VERSION 5.7 ;
  NOWIREEXTENSIONATPIN ON ;
  DIVIDERCHAR "/" ;
  BUSBITCHARS "[]" ;
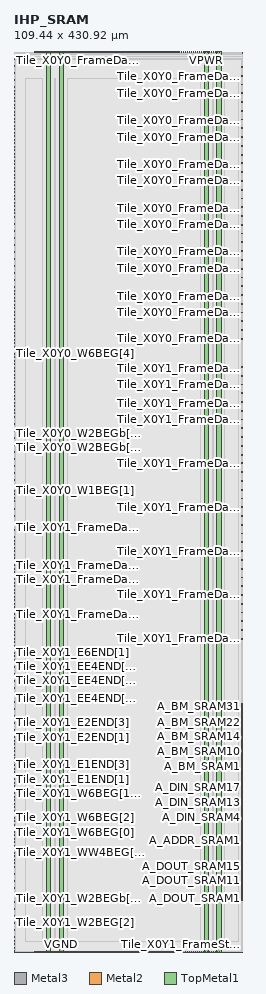
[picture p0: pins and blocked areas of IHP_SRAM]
MACRO IHP_SRAM
  CLASS BLOCK ;
  FOREIGN IHP_SRAM ;
  ORIGIN 0.000 0.000 ;
  SIZE 109.440 BY 430.920 ;
  PIN A_ADDR_SRAM0
    DIRECTION OUTPUT ;
    USE SIGNAL ;
    ANTENNADIFFAREA 0.708600 ;
    PORT
      LAYER Metal3 ;
        RECT 109.040 52.300 109.440 52.700 ;
    END
  END A_ADDR_SRAM0
  PIN A_ADDR_SRAM1
    DIRECTION OUTPUT ;
    USE SIGNAL ;
    ANTENNADIFFAREA 0.708600 ;
    PORT
      LAYER Metal3 ;
        RECT 109.040 53.140 109.440 53.540 ;
    END
  END A_ADDR_SRAM1
  PIN A_ADDR_SRAM2
    DIRECTION OUTPUT ;
    USE SIGNAL ;
    ANTENNADIFFAREA 0.708600 ;
    PORT
      LAYER Metal3 ;
        RECT 109.040 53.980 109.440 54.380 ;
    END
  END A_ADDR_SRAM2
  PIN A_ADDR_SRAM3
    DIRECTION OUTPUT ;
    USE SIGNAL ;
    ANTENNADIFFAREA 0.708600 ;
    PORT
      LAYER Metal3 ;
        RECT 109.040 54.820 109.440 55.220 ;
    END
  END A_ADDR_SRAM3
  PIN A_ADDR_SRAM4
    DIRECTION OUTPUT ;
    USE SIGNAL ;
    ANTENNADIFFAREA 0.708600 ;
    PORT
      LAYER Metal3 ;
        RECT 109.040 55.660 109.440 56.060 ;
    END
  END A_ADDR_SRAM4
  PIN A_ADDR_SRAM5
    DIRECTION OUTPUT ;
    USE SIGNAL ;
    ANTENNADIFFAREA 0.708600 ;
    PORT
      LAYER Metal3 ;
        RECT 109.040 56.500 109.440 56.900 ;
    END
  END A_ADDR_SRAM5
  PIN A_ADDR_SRAM6
    DIRECTION OUTPUT ;
    USE SIGNAL ;
    ANTENNADIFFAREA 0.708600 ;
    PORT
      LAYER Metal3 ;
        RECT 109.040 57.340 109.440 57.740 ;
    END
  END A_ADDR_SRAM6
  PIN A_ADDR_SRAM7
    DIRECTION OUTPUT ;
    USE SIGNAL ;
    ANTENNADIFFAREA 0.708600 ;
    PORT
      LAYER Metal3 ;
        RECT 109.040 58.180 109.440 58.580 ;
    END
  END A_ADDR_SRAM7
  PIN A_ADDR_SRAM8
    DIRECTION OUTPUT ;
    USE SIGNAL ;
    ANTENNADIFFAREA 0.708600 ;
    PORT
      LAYER Metal3 ;
        RECT 109.040 59.020 109.440 59.420 ;
    END
  END A_ADDR_SRAM8
  PIN A_ADDR_SRAM9
    DIRECTION OUTPUT ;
    USE SIGNAL ;
    ANTENNADIFFAREA 0.708600 ;
    PORT
      LAYER Metal3 ;
        RECT 109.040 59.860 109.440 60.260 ;
    END
  END A_ADDR_SRAM9
  PIN A_BM_SRAM0
    DIRECTION OUTPUT ;
    USE SIGNAL ;
    ANTENNADIFFAREA 0.708600 ;
    PORT
      LAYER Metal3 ;
        RECT 109.040 87.580 109.440 87.980 ;
    END
  END A_BM_SRAM0
  PIN A_BM_SRAM1
    DIRECTION OUTPUT ;
    USE SIGNAL ;
    ANTENNADIFFAREA 0.708600 ;
    PORT
      LAYER Metal3 ;
        RECT 109.040 88.420 109.440 88.820 ;
    END
  END A_BM_SRAM1
  PIN A_BM_SRAM10
    DIRECTION OUTPUT ;
    USE SIGNAL ;
    ANTENNADIFFAREA 0.708600 ;
    PORT
      LAYER Metal3 ;
        RECT 109.040 95.980 109.440 96.380 ;
    END
  END A_BM_SRAM10
  PIN A_BM_SRAM11
    DIRECTION OUTPUT ;
    USE SIGNAL ;
    ANTENNADIFFAREA 0.708600 ;
    PORT
      LAYER Metal3 ;
        RECT 109.040 96.820 109.440 97.220 ;
    END
  END A_BM_SRAM11
  PIN A_BM_SRAM12
    DIRECTION OUTPUT ;
    USE SIGNAL ;
    ANTENNADIFFAREA 0.708600 ;
    PORT
      LAYER Metal3 ;
        RECT 109.040 97.660 109.440 98.060 ;
    END
  END A_BM_SRAM12
  PIN A_BM_SRAM13
    DIRECTION OUTPUT ;
    USE SIGNAL ;
    ANTENNADIFFAREA 0.708600 ;
    PORT
      LAYER Metal3 ;
        RECT 109.040 98.500 109.440 98.900 ;
    END
  END A_BM_SRAM13
  PIN A_BM_SRAM14
    DIRECTION OUTPUT ;
    USE SIGNAL ;
    ANTENNADIFFAREA 0.708600 ;
    PORT
      LAYER Metal3 ;
        RECT 109.040 99.340 109.440 99.740 ;
    END
  END A_BM_SRAM14
  PIN A_BM_SRAM15
    DIRECTION OUTPUT ;
    USE SIGNAL ;
    ANTENNADIFFAREA 0.708600 ;
    PORT
      LAYER Metal3 ;
        RECT 109.040 100.180 109.440 100.580 ;
    END
  END A_BM_SRAM15
  PIN A_BM_SRAM16
    DIRECTION OUTPUT ;
    USE SIGNAL ;
    ANTENNADIFFAREA 0.708600 ;
    PORT
      LAYER Metal3 ;
        RECT 109.040 101.020 109.440 101.420 ;
    END
  END A_BM_SRAM16
  PIN A_BM_SRAM17
    DIRECTION OUTPUT ;
    USE SIGNAL ;
    ANTENNADIFFAREA 0.708600 ;
    PORT
      LAYER Metal3 ;
        RECT 109.040 101.860 109.440 102.260 ;
    END
  END A_BM_SRAM17
  PIN A_BM_SRAM18
    DIRECTION OUTPUT ;
    USE SIGNAL ;
    ANTENNADIFFAREA 0.708600 ;
    PORT
      LAYER Metal3 ;
        RECT 109.040 102.700 109.440 103.100 ;
    END
  END A_BM_SRAM18
  PIN A_BM_SRAM19
    DIRECTION OUTPUT ;
    USE SIGNAL ;
    ANTENNADIFFAREA 0.708600 ;
    PORT
      LAYER Metal3 ;
        RECT 109.040 103.540 109.440 103.940 ;
    END
  END A_BM_SRAM19
  PIN A_BM_SRAM2
    DIRECTION OUTPUT ;
    USE SIGNAL ;
    ANTENNADIFFAREA 0.708600 ;
    PORT
      LAYER Metal3 ;
        RECT 109.040 89.260 109.440 89.660 ;
    END
  END A_BM_SRAM2
  PIN A_BM_SRAM20
    DIRECTION OUTPUT ;
    USE SIGNAL ;
    ANTENNADIFFAREA 0.708600 ;
    PORT
      LAYER Metal3 ;
        RECT 109.040 104.380 109.440 104.780 ;
    END
  END A_BM_SRAM20
  PIN A_BM_SRAM21
    DIRECTION OUTPUT ;
    USE SIGNAL ;
    ANTENNADIFFAREA 0.708600 ;
    PORT
      LAYER Metal3 ;
        RECT 109.040 105.220 109.440 105.620 ;
    END
  END A_BM_SRAM21
  PIN A_BM_SRAM22
    DIRECTION OUTPUT ;
    USE SIGNAL ;
    ANTENNADIFFAREA 0.708600 ;
    PORT
      LAYER Metal3 ;
        RECT 109.040 106.060 109.440 106.460 ;
    END
  END A_BM_SRAM22
  PIN A_BM_SRAM23
    DIRECTION OUTPUT ;
    USE SIGNAL ;
    ANTENNADIFFAREA 0.708600 ;
    PORT
      LAYER Metal3 ;
        RECT 109.040 106.900 109.440 107.300 ;
    END
  END A_BM_SRAM23
  PIN A_BM_SRAM24
    DIRECTION OUTPUT ;
    USE SIGNAL ;
    ANTENNADIFFAREA 0.708600 ;
    PORT
      LAYER Metal3 ;
        RECT 109.040 107.740 109.440 108.140 ;
    END
  END A_BM_SRAM24
  PIN A_BM_SRAM25
    DIRECTION OUTPUT ;
    USE SIGNAL ;
    ANTENNADIFFAREA 0.708600 ;
    PORT
      LAYER Metal3 ;
        RECT 109.040 108.580 109.440 108.980 ;
    END
  END A_BM_SRAM25
  PIN A_BM_SRAM26
    DIRECTION OUTPUT ;
    USE SIGNAL ;
    ANTENNADIFFAREA 0.708600 ;
    PORT
      LAYER Metal3 ;
        RECT 109.040 109.420 109.440 109.820 ;
    END
  END A_BM_SRAM26
  PIN A_BM_SRAM27
    DIRECTION OUTPUT ;
    USE SIGNAL ;
    ANTENNADIFFAREA 0.708600 ;
    PORT
      LAYER Metal3 ;
        RECT 109.040 110.260 109.440 110.660 ;
    END
  END A_BM_SRAM27
  PIN A_BM_SRAM28
    DIRECTION OUTPUT ;
    USE SIGNAL ;
    ANTENNADIFFAREA 0.708600 ;
    PORT
      LAYER Metal3 ;
        RECT 109.040 111.100 109.440 111.500 ;
    END
  END A_BM_SRAM28
  PIN A_BM_SRAM29
    DIRECTION OUTPUT ;
    USE SIGNAL ;
    ANTENNADIFFAREA 0.708600 ;
    PORT
      LAYER Metal3 ;
        RECT 109.040 111.940 109.440 112.340 ;
    END
  END A_BM_SRAM29
  PIN A_BM_SRAM3
    DIRECTION OUTPUT ;
    USE SIGNAL ;
    ANTENNADIFFAREA 0.708600 ;
    PORT
      LAYER Metal3 ;
        RECT 109.040 90.100 109.440 90.500 ;
    END
  END A_BM_SRAM3
  PIN A_BM_SRAM30
    DIRECTION OUTPUT ;
    USE SIGNAL ;
    ANTENNADIFFAREA 0.708600 ;
    PORT
      LAYER Metal3 ;
        RECT 109.040 112.780 109.440 113.180 ;
    END
  END A_BM_SRAM30
  PIN A_BM_SRAM31
    DIRECTION OUTPUT ;
    USE SIGNAL ;
    ANTENNADIFFAREA 0.708600 ;
    PORT
      LAYER Metal3 ;
        RECT 109.040 113.620 109.440 114.020 ;
    END
  END A_BM_SRAM31
  PIN A_BM_SRAM4
    DIRECTION OUTPUT ;
    USE SIGNAL ;
    ANTENNADIFFAREA 0.708600 ;
    PORT
      LAYER Metal3 ;
        RECT 109.040 90.940 109.440 91.340 ;
    END
  END A_BM_SRAM4
  PIN A_BM_SRAM5
    DIRECTION OUTPUT ;
    USE SIGNAL ;
    ANTENNADIFFAREA 0.708600 ;
    PORT
      LAYER Metal3 ;
        RECT 109.040 91.780 109.440 92.180 ;
    END
  END A_BM_SRAM5
  PIN A_BM_SRAM6
    DIRECTION OUTPUT ;
    USE SIGNAL ;
    ANTENNADIFFAREA 0.708600 ;
    PORT
      LAYER Metal3 ;
        RECT 109.040 92.620 109.440 93.020 ;
    END
  END A_BM_SRAM6
  PIN A_BM_SRAM7
    DIRECTION OUTPUT ;
    USE SIGNAL ;
    ANTENNADIFFAREA 0.708600 ;
    PORT
      LAYER Metal3 ;
        RECT 109.040 93.460 109.440 93.860 ;
    END
  END A_BM_SRAM7
  PIN A_BM_SRAM8
    DIRECTION OUTPUT ;
    USE SIGNAL ;
    ANTENNADIFFAREA 0.708600 ;
    PORT
      LAYER Metal3 ;
        RECT 109.040 94.300 109.440 94.700 ;
    END
  END A_BM_SRAM8
  PIN A_BM_SRAM9
    DIRECTION OUTPUT ;
    USE SIGNAL ;
    ANTENNADIFFAREA 0.708600 ;
    PORT
      LAYER Metal3 ;
        RECT 109.040 95.140 109.440 95.540 ;
    END
  END A_BM_SRAM9
  PIN A_CLK_SRAM
    DIRECTION OUTPUT ;
    USE SIGNAL ;
    ANTENNADIFFAREA 0.708600 ;
    PORT
      LAYER Metal3 ;
        RECT 109.040 116.980 109.440 117.380 ;
    END
  END A_CLK_SRAM
  PIN A_DIN_SRAM0
    DIRECTION OUTPUT ;
    USE SIGNAL ;
    ANTENNADIFFAREA 0.708600 ;
    PORT
      LAYER Metal3 ;
        RECT 109.040 60.700 109.440 61.100 ;
    END
  END A_DIN_SRAM0
  PIN A_DIN_SRAM1
    DIRECTION OUTPUT ;
    USE SIGNAL ;
    ANTENNADIFFAREA 0.708600 ;
    PORT
      LAYER Metal3 ;
        RECT 109.040 61.540 109.440 61.940 ;
    END
  END A_DIN_SRAM1
  PIN A_DIN_SRAM10
    DIRECTION OUTPUT ;
    USE SIGNAL ;
    ANTENNADIFFAREA 0.708600 ;
    PORT
      LAYER Metal3 ;
        RECT 109.040 69.100 109.440 69.500 ;
    END
  END A_DIN_SRAM10
  PIN A_DIN_SRAM11
    DIRECTION OUTPUT ;
    USE SIGNAL ;
    ANTENNADIFFAREA 0.708600 ;
    PORT
      LAYER Metal3 ;
        RECT 109.040 69.940 109.440 70.340 ;
    END
  END A_DIN_SRAM11
  PIN A_DIN_SRAM12
    DIRECTION OUTPUT ;
    USE SIGNAL ;
    ANTENNADIFFAREA 0.708600 ;
    PORT
      LAYER Metal3 ;
        RECT 109.040 70.780 109.440 71.180 ;
    END
  END A_DIN_SRAM12
  PIN A_DIN_SRAM13
    DIRECTION OUTPUT ;
    USE SIGNAL ;
    ANTENNADIFFAREA 0.708600 ;
    PORT
      LAYER Metal3 ;
        RECT 109.040 71.620 109.440 72.020 ;
    END
  END A_DIN_SRAM13
  PIN A_DIN_SRAM14
    DIRECTION OUTPUT ;
    USE SIGNAL ;
    ANTENNADIFFAREA 0.708600 ;
    PORT
      LAYER Metal3 ;
        RECT 109.040 72.460 109.440 72.860 ;
    END
  END A_DIN_SRAM14
  PIN A_DIN_SRAM15
    DIRECTION OUTPUT ;
    USE SIGNAL ;
    ANTENNADIFFAREA 0.708600 ;
    PORT
      LAYER Metal3 ;
        RECT 109.040 73.300 109.440 73.700 ;
    END
  END A_DIN_SRAM15
  PIN A_DIN_SRAM16
    DIRECTION OUTPUT ;
    USE SIGNAL ;
    ANTENNADIFFAREA 0.708600 ;
    PORT
      LAYER Metal3 ;
        RECT 109.040 74.140 109.440 74.540 ;
    END
  END A_DIN_SRAM16
  PIN A_DIN_SRAM17
    DIRECTION OUTPUT ;
    USE SIGNAL ;
    ANTENNADIFFAREA 0.708600 ;
    PORT
      LAYER Metal3 ;
        RECT 109.040 74.980 109.440 75.380 ;
    END
  END A_DIN_SRAM17
  PIN A_DIN_SRAM18
    DIRECTION OUTPUT ;
    USE SIGNAL ;
    ANTENNADIFFAREA 0.708600 ;
    PORT
      LAYER Metal3 ;
        RECT 109.040 75.820 109.440 76.220 ;
    END
  END A_DIN_SRAM18
  PIN A_DIN_SRAM19
    DIRECTION OUTPUT ;
    USE SIGNAL ;
    ANTENNADIFFAREA 0.708600 ;
    PORT
      LAYER Metal3 ;
        RECT 109.040 76.660 109.440 77.060 ;
    END
  END A_DIN_SRAM19
  PIN A_DIN_SRAM2
    DIRECTION OUTPUT ;
    USE SIGNAL ;
    ANTENNADIFFAREA 0.708600 ;
    PORT
      LAYER Metal3 ;
        RECT 109.040 62.380 109.440 62.780 ;
    END
  END A_DIN_SRAM2
  PIN A_DIN_SRAM20
    DIRECTION OUTPUT ;
    USE SIGNAL ;
    ANTENNADIFFAREA 0.708600 ;
    PORT
      LAYER Metal3 ;
        RECT 109.040 77.500 109.440 77.900 ;
    END
  END A_DIN_SRAM20
  PIN A_DIN_SRAM21
    DIRECTION OUTPUT ;
    USE SIGNAL ;
    ANTENNADIFFAREA 0.708600 ;
    PORT
      LAYER Metal3 ;
        RECT 109.040 78.340 109.440 78.740 ;
    END
  END A_DIN_SRAM21
  PIN A_DIN_SRAM22
    DIRECTION OUTPUT ;
    USE SIGNAL ;
    ANTENNADIFFAREA 0.708600 ;
    PORT
      LAYER Metal3 ;
        RECT 109.040 79.180 109.440 79.580 ;
    END
  END A_DIN_SRAM22
  PIN A_DIN_SRAM23
    DIRECTION OUTPUT ;
    USE SIGNAL ;
    ANTENNADIFFAREA 0.708600 ;
    PORT
      LAYER Metal3 ;
        RECT 109.040 80.020 109.440 80.420 ;
    END
  END A_DIN_SRAM23
  PIN A_DIN_SRAM24
    DIRECTION OUTPUT ;
    USE SIGNAL ;
    ANTENNADIFFAREA 0.708600 ;
    PORT
      LAYER Metal3 ;
        RECT 109.040 80.860 109.440 81.260 ;
    END
  END A_DIN_SRAM24
  PIN A_DIN_SRAM25
    DIRECTION OUTPUT ;
    USE SIGNAL ;
    ANTENNADIFFAREA 0.708600 ;
    PORT
      LAYER Metal3 ;
        RECT 109.040 81.700 109.440 82.100 ;
    END
  END A_DIN_SRAM25
  PIN A_DIN_SRAM26
    DIRECTION OUTPUT ;
    USE SIGNAL ;
    ANTENNADIFFAREA 0.708600 ;
    PORT
      LAYER Metal3 ;
        RECT 109.040 82.540 109.440 82.940 ;
    END
  END A_DIN_SRAM26
  PIN A_DIN_SRAM27
    DIRECTION OUTPUT ;
    USE SIGNAL ;
    ANTENNADIFFAREA 0.708600 ;
    PORT
      LAYER Metal3 ;
        RECT 109.040 83.380 109.440 83.780 ;
    END
  END A_DIN_SRAM27
  PIN A_DIN_SRAM28
    DIRECTION OUTPUT ;
    USE SIGNAL ;
    ANTENNADIFFAREA 0.708600 ;
    PORT
      LAYER Metal3 ;
        RECT 109.040 84.220 109.440 84.620 ;
    END
  END A_DIN_SRAM28
  PIN A_DIN_SRAM29
    DIRECTION OUTPUT ;
    USE SIGNAL ;
    ANTENNADIFFAREA 0.708600 ;
    PORT
      LAYER Metal3 ;
        RECT 109.040 85.060 109.440 85.460 ;
    END
  END A_DIN_SRAM29
  PIN A_DIN_SRAM3
    DIRECTION OUTPUT ;
    USE SIGNAL ;
    ANTENNADIFFAREA 0.708600 ;
    PORT
      LAYER Metal3 ;
        RECT 109.040 63.220 109.440 63.620 ;
    END
  END A_DIN_SRAM3
  PIN A_DIN_SRAM30
    DIRECTION OUTPUT ;
    USE SIGNAL ;
    ANTENNADIFFAREA 0.708600 ;
    PORT
      LAYER Metal3 ;
        RECT 109.040 85.900 109.440 86.300 ;
    END
  END A_DIN_SRAM30
  PIN A_DIN_SRAM31
    DIRECTION OUTPUT ;
    USE SIGNAL ;
    ANTENNADIFFAREA 0.708600 ;
    PORT
      LAYER Metal3 ;
        RECT 109.040 86.740 109.440 87.140 ;
    END
  END A_DIN_SRAM31
  PIN A_DIN_SRAM4
    DIRECTION OUTPUT ;
    USE SIGNAL ;
    ANTENNADIFFAREA 0.708600 ;
    PORT
      LAYER Metal3 ;
        RECT 109.040 64.060 109.440 64.460 ;
    END
  END A_DIN_SRAM4
  PIN A_DIN_SRAM5
    DIRECTION OUTPUT ;
    USE SIGNAL ;
    ANTENNADIFFAREA 0.708600 ;
    PORT
      LAYER Metal3 ;
        RECT 109.040 64.900 109.440 65.300 ;
    END
  END A_DIN_SRAM5
  PIN A_DIN_SRAM6
    DIRECTION OUTPUT ;
    USE SIGNAL ;
    ANTENNADIFFAREA 0.708600 ;
    PORT
      LAYER Metal3 ;
        RECT 109.040 65.740 109.440 66.140 ;
    END
  END A_DIN_SRAM6
  PIN A_DIN_SRAM7
    DIRECTION OUTPUT ;
    USE SIGNAL ;
    ANTENNADIFFAREA 0.708600 ;
    PORT
      LAYER Metal3 ;
        RECT 109.040 66.580 109.440 66.980 ;
    END
  END A_DIN_SRAM7
  PIN A_DIN_SRAM8
    DIRECTION OUTPUT ;
    USE SIGNAL ;
    ANTENNADIFFAREA 0.708600 ;
    PORT
      LAYER Metal3 ;
        RECT 109.040 67.420 109.440 67.820 ;
    END
  END A_DIN_SRAM8
  PIN A_DIN_SRAM9
    DIRECTION OUTPUT ;
    USE SIGNAL ;
    ANTENNADIFFAREA 0.708600 ;
    PORT
      LAYER Metal3 ;
        RECT 109.040 68.260 109.440 68.660 ;
    END
  END A_DIN_SRAM9
  PIN A_DOUT_SRAM0
    DIRECTION INPUT ;
    USE SIGNAL ;
    ANTENNAGATEAREA 1.279200 ;
    PORT
      LAYER Metal3 ;
        RECT 109.040 24.580 109.440 24.980 ;
    END
  END A_DOUT_SRAM0
  PIN A_DOUT_SRAM1
    DIRECTION INPUT ;
    USE SIGNAL ;
    ANTENNAGATEAREA 1.279200 ;
    PORT
      LAYER Metal3 ;
        RECT 109.040 25.420 109.440 25.820 ;
    END
  END A_DOUT_SRAM1
  PIN A_DOUT_SRAM10
    DIRECTION INPUT ;
    USE SIGNAL ;
    ANTENNAGATEAREA 0.852800 ;
    PORT
      LAYER Metal3 ;
        RECT 109.040 32.980 109.440 33.380 ;
    END
  END A_DOUT_SRAM10
  PIN A_DOUT_SRAM11
    DIRECTION INPUT ;
    USE SIGNAL ;
    ANTENNAGATEAREA 0.852800 ;
    PORT
      LAYER Metal3 ;
        RECT 109.040 33.820 109.440 34.220 ;
    END
  END A_DOUT_SRAM11
  PIN A_DOUT_SRAM12
    DIRECTION INPUT ;
    USE SIGNAL ;
    ANTENNAGATEAREA 0.852800 ;
    PORT
      LAYER Metal3 ;
        RECT 109.040 34.660 109.440 35.060 ;
    END
  END A_DOUT_SRAM12
  PIN A_DOUT_SRAM13
    DIRECTION INPUT ;
    USE SIGNAL ;
    ANTENNAGATEAREA 0.852800 ;
    PORT
      LAYER Metal3 ;
        RECT 109.040 35.500 109.440 35.900 ;
    END
  END A_DOUT_SRAM13
  PIN A_DOUT_SRAM14
    DIRECTION INPUT ;
    USE SIGNAL ;
    ANTENNAGATEAREA 0.852800 ;
    PORT
      LAYER Metal3 ;
        RECT 109.040 36.340 109.440 36.740 ;
    END
  END A_DOUT_SRAM14
  PIN A_DOUT_SRAM15
    DIRECTION INPUT ;
    USE SIGNAL ;
    ANTENNAGATEAREA 0.852800 ;
    PORT
      LAYER Metal3 ;
        RECT 109.040 37.180 109.440 37.580 ;
    END
  END A_DOUT_SRAM15
  PIN A_DOUT_SRAM16
    DIRECTION INPUT ;
    USE SIGNAL ;
    ANTENNAGATEAREA 1.279200 ;
    PORT
      LAYER Metal3 ;
        RECT 109.040 38.020 109.440 38.420 ;
    END
  END A_DOUT_SRAM16
  PIN A_DOUT_SRAM17
    DIRECTION INPUT ;
    USE SIGNAL ;
    ANTENNAGATEAREA 1.279200 ;
    PORT
      LAYER Metal3 ;
        RECT 109.040 38.860 109.440 39.260 ;
    END
  END A_DOUT_SRAM17
  PIN A_DOUT_SRAM18
    DIRECTION INPUT ;
    USE SIGNAL ;
    ANTENNAGATEAREA 5.538000 ;
    ANTENNADIFFAREA 14.107800 ;
    PORT
      LAYER Metal3 ;
        RECT 109.040 39.700 109.440 40.100 ;
    END
  END A_DOUT_SRAM18
  PIN A_DOUT_SRAM19
    DIRECTION INPUT ;
    USE SIGNAL ;
    ANTENNAGATEAREA 4.929600 ;
    ANTENNADIFFAREA 12.092400 ;
    PORT
      LAYER Metal3 ;
        RECT 109.040 40.540 109.440 40.940 ;
    END
  END A_DOUT_SRAM19
  PIN A_DOUT_SRAM2
    DIRECTION INPUT ;
    USE SIGNAL ;
    ANTENNAGATEAREA 1.279200 ;
    PORT
      LAYER Metal3 ;
        RECT 109.040 26.260 109.440 26.660 ;
    END
  END A_DOUT_SRAM2
  PIN A_DOUT_SRAM20
    DIRECTION INPUT ;
    USE SIGNAL ;
    ANTENNAGATEAREA 1.279200 ;
    PORT
      LAYER Metal3 ;
        RECT 109.040 41.380 109.440 41.780 ;
    END
  END A_DOUT_SRAM20
  PIN A_DOUT_SRAM21
    DIRECTION INPUT ;
    USE SIGNAL ;
    ANTENNAGATEAREA 1.279200 ;
    PORT
      LAYER Metal3 ;
        RECT 109.040 42.220 109.440 42.620 ;
    END
  END A_DOUT_SRAM21
  PIN A_DOUT_SRAM22
    DIRECTION INPUT ;
    USE SIGNAL ;
    ANTENNAGATEAREA 1.279200 ;
    PORT
      LAYER Metal3 ;
        RECT 109.040 43.060 109.440 43.460 ;
    END
  END A_DOUT_SRAM22
  PIN A_DOUT_SRAM23
    DIRECTION INPUT ;
    USE SIGNAL ;
    ANTENNAGATEAREA 1.279200 ;
    PORT
      LAYER Metal3 ;
        RECT 109.040 43.900 109.440 44.300 ;
    END
  END A_DOUT_SRAM23
  PIN A_DOUT_SRAM24
    DIRECTION INPUT ;
    USE SIGNAL ;
    ANTENNAGATEAREA 1.066000 ;
    PORT
      LAYER Metal3 ;
        RECT 109.040 44.740 109.440 45.140 ;
    END
  END A_DOUT_SRAM24
  PIN A_DOUT_SRAM25
    DIRECTION INPUT ;
    USE SIGNAL ;
    ANTENNAGATEAREA 0.639600 ;
    PORT
      LAYER Metal3 ;
        RECT 109.040 45.580 109.440 45.980 ;
    END
  END A_DOUT_SRAM25
  PIN A_DOUT_SRAM26
    DIRECTION INPUT ;
    USE SIGNAL ;
    ANTENNAGATEAREA 0.852800 ;
    PORT
      LAYER Metal3 ;
        RECT 109.040 46.420 109.440 46.820 ;
    END
  END A_DOUT_SRAM26
  PIN A_DOUT_SRAM27
    DIRECTION INPUT ;
    USE SIGNAL ;
    ANTENNAGATEAREA 0.852800 ;
    PORT
      LAYER Metal3 ;
        RECT 109.040 47.260 109.440 47.660 ;
    END
  END A_DOUT_SRAM27
  PIN A_DOUT_SRAM28
    DIRECTION INPUT ;
    USE SIGNAL ;
    ANTENNAGATEAREA 3.894800 ;
    ANTENNADIFFAREA 10.077000 ;
    PORT
      LAYER Metal3 ;
        RECT 109.040 48.100 109.440 48.500 ;
    END
  END A_DOUT_SRAM28
  PIN A_DOUT_SRAM29
    DIRECTION INPUT ;
    USE SIGNAL ;
    ANTENNAGATEAREA 0.852800 ;
    PORT
      LAYER Metal3 ;
        RECT 109.040 48.940 109.440 49.340 ;
    END
  END A_DOUT_SRAM29
  PIN A_DOUT_SRAM3
    DIRECTION INPUT ;
    USE SIGNAL ;
    ANTENNAGATEAREA 1.279200 ;
    PORT
      LAYER Metal3 ;
        RECT 109.040 27.100 109.440 27.500 ;
    END
  END A_DOUT_SRAM3
  PIN A_DOUT_SRAM30
    DIRECTION INPUT ;
    USE SIGNAL ;
    ANTENNAGATEAREA 0.852800 ;
    PORT
      LAYER Metal3 ;
        RECT 109.040 49.780 109.440 50.180 ;
    END
  END A_DOUT_SRAM30
  PIN A_DOUT_SRAM31
    DIRECTION INPUT ;
    USE SIGNAL ;
    ANTENNAGATEAREA 0.852800 ;
    PORT
      LAYER Metal3 ;
        RECT 109.040 50.620 109.440 51.020 ;
    END
  END A_DOUT_SRAM31
  PIN A_DOUT_SRAM4
    DIRECTION INPUT ;
    USE SIGNAL ;
    ANTENNAGATEAREA 1.279200 ;
    PORT
      LAYER Metal3 ;
        RECT 109.040 27.940 109.440 28.340 ;
    END
  END A_DOUT_SRAM4
  PIN A_DOUT_SRAM5
    DIRECTION INPUT ;
    USE SIGNAL ;
    ANTENNAGATEAREA 1.279200 ;
    PORT
      LAYER Metal3 ;
        RECT 109.040 28.780 109.440 29.180 ;
    END
  END A_DOUT_SRAM5
  PIN A_DOUT_SRAM6
    DIRECTION INPUT ;
    USE SIGNAL ;
    ANTENNAGATEAREA 1.279200 ;
    PORT
      LAYER Metal3 ;
        RECT 109.040 29.620 109.440 30.020 ;
    END
  END A_DOUT_SRAM6
  PIN A_DOUT_SRAM7
    DIRECTION INPUT ;
    USE SIGNAL ;
    ANTENNAGATEAREA 1.279200 ;
    PORT
      LAYER Metal3 ;
        RECT 109.040 30.460 109.440 30.860 ;
    END
  END A_DOUT_SRAM7
  PIN A_DOUT_SRAM8
    DIRECTION INPUT ;
    USE SIGNAL ;
    ANTENNAGATEAREA 0.852800 ;
    PORT
      LAYER Metal3 ;
        RECT 109.040 31.300 109.440 31.700 ;
    END
  END A_DOUT_SRAM8
  PIN A_DOUT_SRAM9
    DIRECTION INPUT ;
    USE SIGNAL ;
    ANTENNAGATEAREA 0.852800 ;
    PORT
      LAYER Metal3 ;
        RECT 109.040 32.140 109.440 32.540 ;
    END
  END A_DOUT_SRAM9
  PIN A_MEN_SRAM
    DIRECTION OUTPUT ;
    USE SIGNAL ;
    ANTENNADIFFAREA 0.708600 ;
    PORT
      LAYER Metal3 ;
        RECT 109.040 115.300 109.440 115.700 ;
    END
  END A_MEN_SRAM
  PIN A_REN_SRAM
    DIRECTION OUTPUT ;
    USE SIGNAL ;
    ANTENNADIFFAREA 0.708600 ;
    PORT
      LAYER Metal3 ;
        RECT 109.040 116.140 109.440 116.540 ;
    END
  END A_REN_SRAM
  PIN A_TIE_HIGH_SRAM
    DIRECTION OUTPUT ;
    USE SIGNAL ;
    ANTENNADIFFAREA 0.392700 ;
    PORT
      LAYER Metal3 ;
        RECT 109.040 117.820 109.440 118.220 ;
    END
  END A_TIE_HIGH_SRAM
  PIN A_TIE_LOW_SRAM
    DIRECTION OUTPUT ;
    USE SIGNAL ;
    ANTENNADIFFAREA 0.299200 ;
    PORT
      LAYER Metal3 ;
        RECT 109.040 118.660 109.440 119.060 ;
    END
  END A_TIE_LOW_SRAM
  PIN A_WEN_SRAM
    DIRECTION OUTPUT ;
    USE SIGNAL ;
    ANTENNADIFFAREA 0.708600 ;
    PORT
      LAYER Metal3 ;
        RECT 109.040 114.460 109.440 114.860 ;
    END
  END A_WEN_SRAM
  PIN CONFIGURED_top
    DIRECTION INPUT ;
    USE SIGNAL ;
    ANTENNAGATEAREA 0.279000 ;
    PORT
      LAYER Metal3 ;
        RECT 109.040 51.460 109.440 51.860 ;
    END
  END CONFIGURED_top
  PIN Tile_X0Y0_E1END[0]
    DIRECTION INPUT ;
    USE SIGNAL ;
    ANTENNAGATEAREA 1.492400 ;
    PORT
      LAYER Metal3 ;
        RECT 0.000 296.320 0.400 296.720 ;
    END
  END Tile_X0Y0_E1END[0]
  PIN Tile_X0Y0_E1END[1]
    DIRECTION INPUT ;
    USE SIGNAL ;
    ANTENNAGATEAREA 1.492400 ;
    PORT
      LAYER Metal3 ;
        RECT 0.000 298.000 0.400 298.400 ;
    END
  END Tile_X0Y0_E1END[1]
  PIN Tile_X0Y0_E1END[2]
    DIRECTION INPUT ;
    USE SIGNAL ;
    ANTENNAGATEAREA 1.492400 ;
    PORT
      LAYER Metal3 ;
        RECT 0.000 299.680 0.400 300.080 ;
    END
  END Tile_X0Y0_E1END[2]
  PIN Tile_X0Y0_E1END[3]
    DIRECTION INPUT ;
    USE SIGNAL ;
    ANTENNAGATEAREA 1.492400 ;
    PORT
      LAYER Metal3 ;
        RECT 0.000 301.360 0.400 301.760 ;
    END
  END Tile_X0Y0_E1END[3]
  PIN Tile_X0Y0_E2END[0]
    DIRECTION INPUT ;
    USE SIGNAL ;
    ANTENNAGATEAREA 0.668200 ;
    PORT
      LAYER Metal3 ;
        RECT 0.000 316.480 0.400 316.880 ;
    END
  END Tile_X0Y0_E2END[0]
  PIN Tile_X0Y0_E2END[1]
    DIRECTION INPUT ;
    USE SIGNAL ;
    ANTENNAGATEAREA 0.668200 ;
    PORT
      LAYER Metal3 ;
        RECT 0.000 318.160 0.400 318.560 ;
    END
  END Tile_X0Y0_E2END[1]
  PIN Tile_X0Y0_E2END[2]
    DIRECTION INPUT ;
    USE SIGNAL ;
    ANTENNAGATEAREA 0.668200 ;
    PORT
      LAYER Metal3 ;
        RECT 0.000 319.840 0.400 320.240 ;
    END
  END Tile_X0Y0_E2END[2]
  PIN Tile_X0Y0_E2END[3]
    DIRECTION INPUT ;
    USE SIGNAL ;
    ANTENNAGATEAREA 0.668200 ;
    PORT
      LAYER Metal3 ;
        RECT 0.000 321.520 0.400 321.920 ;
    END
  END Tile_X0Y0_E2END[3]
  PIN Tile_X0Y0_E2END[4]
    DIRECTION INPUT ;
    USE SIGNAL ;
    ANTENNAGATEAREA 0.668200 ;
    PORT
      LAYER Metal3 ;
        RECT 0.000 323.200 0.400 323.600 ;
    END
  END Tile_X0Y0_E2END[4]
  PIN Tile_X0Y0_E2END[5]
    DIRECTION INPUT ;
    USE SIGNAL ;
    ANTENNAGATEAREA 0.426400 ;
    PORT
      LAYER Metal3 ;
        RECT 0.000 324.880 0.400 325.280 ;
    END
  END Tile_X0Y0_E2END[5]
  PIN Tile_X0Y0_E2END[6]
    DIRECTION INPUT ;
    USE SIGNAL ;
    ANTENNAGATEAREA 0.426400 ;
    PORT
      LAYER Metal3 ;
        RECT 0.000 326.560 0.400 326.960 ;
    END
  END Tile_X0Y0_E2END[6]
  PIN Tile_X0Y0_E2END[7]
    DIRECTION INPUT ;
    USE SIGNAL ;
    ANTENNAGATEAREA 0.426400 ;
    PORT
      LAYER Metal3 ;
        RECT 0.000 328.240 0.400 328.640 ;
    END
  END Tile_X0Y0_E2END[7]
  PIN Tile_X0Y0_E2MID[0]
    DIRECTION INPUT ;
    USE SIGNAL ;
    ANTENNAGATEAREA 0.672100 ;
    PORT
      LAYER Metal3 ;
        RECT 0.000 303.040 0.400 303.440 ;
    END
  END Tile_X0Y0_E2MID[0]
  PIN Tile_X0Y0_E2MID[1]
    DIRECTION INPUT ;
    USE SIGNAL ;
    ANTENNAGATEAREA 0.672100 ;
    PORT
      LAYER Metal3 ;
        RECT 0.000 304.720 0.400 305.120 ;
    END
  END Tile_X0Y0_E2MID[1]
  PIN Tile_X0Y0_E2MID[2]
    DIRECTION INPUT ;
    USE SIGNAL ;
    ANTENNAGATEAREA 0.672100 ;
    PORT
      LAYER Metal3 ;
        RECT 0.000 306.400 0.400 306.800 ;
    END
  END Tile_X0Y0_E2MID[2]
  PIN Tile_X0Y0_E2MID[3]
    DIRECTION INPUT ;
    USE SIGNAL ;
    ANTENNAGATEAREA 0.672100 ;
    PORT
      LAYER Metal3 ;
        RECT 0.000 308.080 0.400 308.480 ;
    END
  END Tile_X0Y0_E2MID[3]
  PIN Tile_X0Y0_E2MID[4]
    DIRECTION INPUT ;
    USE SIGNAL ;
    ANTENNAGATEAREA 0.672100 ;
    PORT
      LAYER Metal3 ;
        RECT 0.000 309.760 0.400 310.160 ;
    END
  END Tile_X0Y0_E2MID[4]
  PIN Tile_X0Y0_E2MID[5]
    DIRECTION INPUT ;
    USE SIGNAL ;
    ANTENNAGATEAREA 0.426400 ;
    PORT
      LAYER Metal3 ;
        RECT 0.000 311.440 0.400 311.840 ;
    END
  END Tile_X0Y0_E2MID[5]
  PIN Tile_X0Y0_E2MID[6]
    DIRECTION INPUT ;
    USE SIGNAL ;
    ANTENNAGATEAREA 0.426400 ;
    PORT
      LAYER Metal3 ;
        RECT 0.000 313.120 0.400 313.520 ;
    END
  END Tile_X0Y0_E2MID[6]
  PIN Tile_X0Y0_E2MID[7]
    DIRECTION INPUT ;
    USE SIGNAL ;
    ANTENNAGATEAREA 0.426400 ;
    PORT
      LAYER Metal3 ;
        RECT 0.000 314.800 0.400 315.200 ;
    END
  END Tile_X0Y0_E2MID[7]
  PIN Tile_X0Y0_E6END[0]
    DIRECTION INPUT ;
    USE SIGNAL ;
    ANTENNAGATEAREA 0.881400 ;
    PORT
      LAYER Metal3 ;
        RECT 0.000 356.800 0.400 357.200 ;
    END
  END Tile_X0Y0_E6END[0]
  PIN Tile_X0Y0_E6END[10]
    DIRECTION INPUT ;
    USE SIGNAL ;
    ANTENNAGATEAREA 1.066000 ;
    PORT
      LAYER Metal3 ;
        RECT 0.000 373.600 0.400 374.000 ;
    END
  END Tile_X0Y0_E6END[10]
  PIN Tile_X0Y0_E6END[11]
    DIRECTION INPUT ;
    USE SIGNAL ;
    ANTENNAGATEAREA 1.066000 ;
    PORT
      LAYER Metal3 ;
        RECT 0.000 375.280 0.400 375.680 ;
    END
  END Tile_X0Y0_E6END[11]
  PIN Tile_X0Y0_E6END[1]
    DIRECTION INPUT ;
    USE SIGNAL ;
    ANTENNAGATEAREA 0.881400 ;
    PORT
      LAYER Metal3 ;
        RECT 0.000 358.480 0.400 358.880 ;
    END
  END Tile_X0Y0_E6END[1]
  PIN Tile_X0Y0_E6END[2]
    DIRECTION INPUT ;
    USE SIGNAL ;
    ANTENNAGATEAREA 0.881400 ;
    PORT
      LAYER Metal3 ;
        RECT 0.000 360.160 0.400 360.560 ;
    END
  END Tile_X0Y0_E6END[2]
  PIN Tile_X0Y0_E6END[3]
    DIRECTION INPUT ;
    USE SIGNAL ;
    ANTENNAGATEAREA 0.881400 ;
    PORT
      LAYER Metal3 ;
        RECT 0.000 361.840 0.400 362.240 ;
    END
  END Tile_X0Y0_E6END[3]
  PIN Tile_X0Y0_E6END[4]
    DIRECTION INPUT ;
    USE SIGNAL ;
    ANTENNAGATEAREA 1.066000 ;
    PORT
      LAYER Metal3 ;
        RECT 0.000 363.520 0.400 363.920 ;
    END
  END Tile_X0Y0_E6END[4]
  PIN Tile_X0Y0_E6END[5]
    DIRECTION INPUT ;
    USE SIGNAL ;
    ANTENNAGATEAREA 1.066000 ;
    PORT
      LAYER Metal3 ;
        RECT 0.000 365.200 0.400 365.600 ;
    END
  END Tile_X0Y0_E6END[5]
  PIN Tile_X0Y0_E6END[6]
    DIRECTION INPUT ;
    USE SIGNAL ;
    ANTENNAGATEAREA 1.066000 ;
    PORT
      LAYER Metal3 ;
        RECT 0.000 366.880 0.400 367.280 ;
    END
  END Tile_X0Y0_E6END[6]
  PIN Tile_X0Y0_E6END[7]
    DIRECTION INPUT ;
    USE SIGNAL ;
    ANTENNAGATEAREA 1.066000 ;
    PORT
      LAYER Metal3 ;
        RECT 0.000 368.560 0.400 368.960 ;
    END
  END Tile_X0Y0_E6END[7]
  PIN Tile_X0Y0_E6END[8]
    DIRECTION INPUT ;
    USE SIGNAL ;
    ANTENNAGATEAREA 1.066000 ;
    PORT
      LAYER Metal3 ;
        RECT 0.000 370.240 0.400 370.640 ;
    END
  END Tile_X0Y0_E6END[8]
  PIN Tile_X0Y0_E6END[9]
    DIRECTION INPUT ;
    USE SIGNAL ;
    ANTENNAGATEAREA 1.066000 ;
    PORT
      LAYER Metal3 ;
        RECT 0.000 371.920 0.400 372.320 ;
    END
  END Tile_X0Y0_E6END[9]
  PIN Tile_X0Y0_EE4END[0]
    DIRECTION INPUT ;
    USE SIGNAL ;
    ANTENNAGATEAREA 1.066000 ;
    PORT
      LAYER Metal3 ;
        RECT 0.000 329.920 0.400 330.320 ;
    END
  END Tile_X0Y0_EE4END[0]
  PIN Tile_X0Y0_EE4END[10]
    DIRECTION INPUT ;
    USE SIGNAL ;
    ANTENNAGATEAREA 0.852800 ;
    PORT
      LAYER Metal3 ;
        RECT 0.000 346.720 0.400 347.120 ;
    END
  END Tile_X0Y0_EE4END[10]
  PIN Tile_X0Y0_EE4END[11]
    DIRECTION INPUT ;
    USE SIGNAL ;
    ANTENNAGATEAREA 0.852800 ;
    PORT
      LAYER Metal3 ;
        RECT 0.000 348.400 0.400 348.800 ;
    END
  END Tile_X0Y0_EE4END[11]
  PIN Tile_X0Y0_EE4END[12]
    DIRECTION INPUT ;
    USE SIGNAL ;
    ANTENNAGATEAREA 1.066000 ;
    PORT
      LAYER Metal3 ;
        RECT 0.000 350.080 0.400 350.480 ;
    END
  END Tile_X0Y0_EE4END[12]
  PIN Tile_X0Y0_EE4END[13]
    DIRECTION INPUT ;
    USE SIGNAL ;
    ANTENNAGATEAREA 1.066000 ;
    PORT
      LAYER Metal3 ;
        RECT 0.000 351.760 0.400 352.160 ;
    END
  END Tile_X0Y0_EE4END[13]
  PIN Tile_X0Y0_EE4END[14]
    DIRECTION INPUT ;
    USE SIGNAL ;
    ANTENNAGATEAREA 1.066000 ;
    PORT
      LAYER Metal3 ;
        RECT 0.000 353.440 0.400 353.840 ;
    END
  END Tile_X0Y0_EE4END[14]
  PIN Tile_X0Y0_EE4END[15]
    DIRECTION INPUT ;
    USE SIGNAL ;
    ANTENNAGATEAREA 1.066000 ;
    PORT
      LAYER Metal3 ;
        RECT 0.000 355.120 0.400 355.520 ;
    END
  END Tile_X0Y0_EE4END[15]
  PIN Tile_X0Y0_EE4END[1]
    DIRECTION INPUT ;
    USE SIGNAL ;
    ANTENNAGATEAREA 1.066000 ;
    PORT
      LAYER Metal3 ;
        RECT 0.000 331.600 0.400 332.000 ;
    END
  END Tile_X0Y0_EE4END[1]
  PIN Tile_X0Y0_EE4END[2]
    DIRECTION INPUT ;
    USE SIGNAL ;
    ANTENNAGATEAREA 1.066000 ;
    PORT
      LAYER Metal3 ;
        RECT 0.000 333.280 0.400 333.680 ;
    END
  END Tile_X0Y0_EE4END[2]
  PIN Tile_X0Y0_EE4END[3]
    DIRECTION INPUT ;
    USE SIGNAL ;
    ANTENNAGATEAREA 1.066000 ;
    PORT
      LAYER Metal3 ;
        RECT 0.000 334.960 0.400 335.360 ;
    END
  END Tile_X0Y0_EE4END[3]
  PIN Tile_X0Y0_EE4END[4]
    DIRECTION INPUT ;
    USE SIGNAL ;
    ANTENNAGATEAREA 0.852800 ;
    PORT
      LAYER Metal3 ;
        RECT 0.000 336.640 0.400 337.040 ;
    END
  END Tile_X0Y0_EE4END[4]
  PIN Tile_X0Y0_EE4END[5]
    DIRECTION INPUT ;
    USE SIGNAL ;
    ANTENNAGATEAREA 0.852800 ;
    PORT
      LAYER Metal3 ;
        RECT 0.000 338.320 0.400 338.720 ;
    END
  END Tile_X0Y0_EE4END[5]
  PIN Tile_X0Y0_EE4END[6]
    DIRECTION INPUT ;
    USE SIGNAL ;
    ANTENNAGATEAREA 0.852800 ;
    PORT
      LAYER Metal3 ;
        RECT 0.000 340.000 0.400 340.400 ;
    END
  END Tile_X0Y0_EE4END[6]
  PIN Tile_X0Y0_EE4END[7]
    DIRECTION INPUT ;
    USE SIGNAL ;
    ANTENNAGATEAREA 0.852800 ;
    PORT
      LAYER Metal3 ;
        RECT 0.000 341.680 0.400 342.080 ;
    END
  END Tile_X0Y0_EE4END[7]
  PIN Tile_X0Y0_EE4END[8]
    DIRECTION INPUT ;
    USE SIGNAL ;
    ANTENNAGATEAREA 0.852800 ;
    PORT
      LAYER Metal3 ;
        RECT 0.000 343.360 0.400 343.760 ;
    END
  END Tile_X0Y0_EE4END[8]
  PIN Tile_X0Y0_EE4END[9]
    DIRECTION INPUT ;
    USE SIGNAL ;
    ANTENNAGATEAREA 0.852800 ;
    PORT
      LAYER Metal3 ;
        RECT 0.000 345.040 0.400 345.440 ;
    END
  END Tile_X0Y0_EE4END[9]
  PIN Tile_X0Y0_FrameData[0]
    DIRECTION INPUT ;
    USE SIGNAL ;
    ANTENNAGATEAREA 1.807000 ;
    PORT
      LAYER Metal3 ;
        RECT 0.000 376.960 0.400 377.360 ;
    END
  END Tile_X0Y0_FrameData[0]
  PIN Tile_X0Y0_FrameData[10]
    DIRECTION INPUT ;
    USE SIGNAL ;
    ANTENNAGATEAREA 1.807000 ;
    PORT
      LAYER Metal3 ;
        RECT 0.000 393.760 0.400 394.160 ;
    END
  END Tile_X0Y0_FrameData[10]
  PIN Tile_X0Y0_FrameData[11]
    DIRECTION INPUT ;
    USE SIGNAL ;
    ANTENNAGATEAREA 1.807000 ;
    PORT
      LAYER Metal3 ;
        RECT 0.000 395.440 0.400 395.840 ;
    END
  END Tile_X0Y0_FrameData[11]
  PIN Tile_X0Y0_FrameData[12]
    DIRECTION INPUT ;
    USE SIGNAL ;
    ANTENNAGATEAREA 1.807000 ;
    PORT
      LAYER Metal3 ;
        RECT 0.000 397.120 0.400 397.520 ;
    END
  END Tile_X0Y0_FrameData[12]
  PIN Tile_X0Y0_FrameData[13]
    DIRECTION INPUT ;
    USE SIGNAL ;
    ANTENNAGATEAREA 1.807000 ;
    PORT
      LAYER Metal3 ;
        RECT 0.000 398.800 0.400 399.200 ;
    END
  END Tile_X0Y0_FrameData[13]
  PIN Tile_X0Y0_FrameData[14]
    DIRECTION INPUT ;
    USE SIGNAL ;
    ANTENNAGATEAREA 1.807000 ;
    PORT
      LAYER Metal3 ;
        RECT 0.000 400.480 0.400 400.880 ;
    END
  END Tile_X0Y0_FrameData[14]
  PIN Tile_X0Y0_FrameData[15]
    DIRECTION INPUT ;
    USE SIGNAL ;
    ANTENNAGATEAREA 1.807000 ;
    PORT
      LAYER Metal3 ;
        RECT 0.000 402.160 0.400 402.560 ;
    END
  END Tile_X0Y0_FrameData[15]
  PIN Tile_X0Y0_FrameData[16]
    DIRECTION INPUT ;
    USE SIGNAL ;
    ANTENNAGATEAREA 1.807000 ;
    PORT
      LAYER Metal3 ;
        RECT 0.000 403.840 0.400 404.240 ;
    END
  END Tile_X0Y0_FrameData[16]
  PIN Tile_X0Y0_FrameData[17]
    DIRECTION INPUT ;
    USE SIGNAL ;
    ANTENNAGATEAREA 1.807000 ;
    PORT
      LAYER Metal3 ;
        RECT 0.000 405.520 0.400 405.920 ;
    END
  END Tile_X0Y0_FrameData[17]
  PIN Tile_X0Y0_FrameData[18]
    DIRECTION INPUT ;
    USE SIGNAL ;
    ANTENNAGATEAREA 1.807000 ;
    PORT
      LAYER Metal3 ;
        RECT 0.000 407.200 0.400 407.600 ;
    END
  END Tile_X0Y0_FrameData[18]
  PIN Tile_X0Y0_FrameData[19]
    DIRECTION INPUT ;
    USE SIGNAL ;
    ANTENNAGATEAREA 1.807000 ;
    PORT
      LAYER Metal3 ;
        RECT 0.000 408.880 0.400 409.280 ;
    END
  END Tile_X0Y0_FrameData[19]
  PIN Tile_X0Y0_FrameData[1]
    DIRECTION INPUT ;
    USE SIGNAL ;
    ANTENNAGATEAREA 1.807000 ;
    PORT
      LAYER Metal3 ;
        RECT 0.000 378.640 0.400 379.040 ;
    END
  END Tile_X0Y0_FrameData[1]
  PIN Tile_X0Y0_FrameData[20]
    DIRECTION INPUT ;
    USE SIGNAL ;
    ANTENNAGATEAREA 1.807000 ;
    PORT
      LAYER Metal3 ;
        RECT 0.000 410.560 0.400 410.960 ;
    END
  END Tile_X0Y0_FrameData[20]
  PIN Tile_X0Y0_FrameData[21]
    DIRECTION INPUT ;
    USE SIGNAL ;
    ANTENNAGATEAREA 1.807000 ;
    PORT
      LAYER Metal3 ;
        RECT 0.000 412.240 0.400 412.640 ;
    END
  END Tile_X0Y0_FrameData[21]
  PIN Tile_X0Y0_FrameData[22]
    DIRECTION INPUT ;
    USE SIGNAL ;
    ANTENNAGATEAREA 1.987700 ;
    PORT
      LAYER Metal3 ;
        RECT 0.000 413.920 0.400 414.320 ;
    END
  END Tile_X0Y0_FrameData[22]
  PIN Tile_X0Y0_FrameData[23]
    DIRECTION INPUT ;
    USE SIGNAL ;
    ANTENNAGATEAREA 1.987700 ;
    PORT
      LAYER Metal3 ;
        RECT 0.000 415.600 0.400 416.000 ;
    END
  END Tile_X0Y0_FrameData[23]
  PIN Tile_X0Y0_FrameData[24]
    DIRECTION INPUT ;
    USE SIGNAL ;
    ANTENNAGATEAREA 1.987700 ;
    PORT
      LAYER Metal3 ;
        RECT 0.000 417.280 0.400 417.680 ;
    END
  END Tile_X0Y0_FrameData[24]
  PIN Tile_X0Y0_FrameData[25]
    DIRECTION INPUT ;
    USE SIGNAL ;
    ANTENNAGATEAREA 1.987700 ;
    PORT
      LAYER Metal3 ;
        RECT 0.000 418.960 0.400 419.360 ;
    END
  END Tile_X0Y0_FrameData[25]
  PIN Tile_X0Y0_FrameData[26]
    DIRECTION INPUT ;
    USE SIGNAL ;
    ANTENNAGATEAREA 1.987700 ;
    PORT
      LAYER Metal3 ;
        RECT 0.000 420.640 0.400 421.040 ;
    END
  END Tile_X0Y0_FrameData[26]
  PIN Tile_X0Y0_FrameData[27]
    DIRECTION INPUT ;
    USE SIGNAL ;
    ANTENNAGATEAREA 1.987700 ;
    PORT
      LAYER Metal3 ;
        RECT 0.000 422.320 0.400 422.720 ;
    END
  END Tile_X0Y0_FrameData[27]
  PIN Tile_X0Y0_FrameData[28]
    DIRECTION INPUT ;
    USE SIGNAL ;
    ANTENNAGATEAREA 1.987700 ;
    PORT
      LAYER Metal3 ;
        RECT 0.000 424.000 0.400 424.400 ;
    END
  END Tile_X0Y0_FrameData[28]
  PIN Tile_X0Y0_FrameData[29]
    DIRECTION INPUT ;
    USE SIGNAL ;
    ANTENNAGATEAREA 1.987700 ;
    PORT
      LAYER Metal3 ;
        RECT 0.000 425.680 0.400 426.080 ;
    END
  END Tile_X0Y0_FrameData[29]
  PIN Tile_X0Y0_FrameData[2]
    DIRECTION INPUT ;
    USE SIGNAL ;
    ANTENNAGATEAREA 1.807000 ;
    PORT
      LAYER Metal3 ;
        RECT 0.000 380.320 0.400 380.720 ;
    END
  END Tile_X0Y0_FrameData[2]
  PIN Tile_X0Y0_FrameData[30]
    DIRECTION INPUT ;
    USE SIGNAL ;
    ANTENNAGATEAREA 1.987700 ;
    PORT
      LAYER Metal3 ;
        RECT 0.000 427.360 0.400 427.760 ;
    END
  END Tile_X0Y0_FrameData[30]
  PIN Tile_X0Y0_FrameData[31]
    DIRECTION INPUT ;
    USE SIGNAL ;
    ANTENNAGATEAREA 1.987700 ;
    PORT
      LAYER Metal3 ;
        RECT 0.000 429.040 0.400 429.440 ;
    END
  END Tile_X0Y0_FrameData[31]
  PIN Tile_X0Y0_FrameData[3]
    DIRECTION INPUT ;
    USE SIGNAL ;
    ANTENNAGATEAREA 1.807000 ;
    PORT
      LAYER Metal3 ;
        RECT 0.000 382.000 0.400 382.400 ;
    END
  END Tile_X0Y0_FrameData[3]
  PIN Tile_X0Y0_FrameData[4]
    DIRECTION INPUT ;
    USE SIGNAL ;
    ANTENNAGATEAREA 1.807000 ;
    PORT
      LAYER Metal3 ;
        RECT 0.000 383.680 0.400 384.080 ;
    END
  END Tile_X0Y0_FrameData[4]
  PIN Tile_X0Y0_FrameData[5]
    DIRECTION INPUT ;
    USE SIGNAL ;
    ANTENNAGATEAREA 1.807000 ;
    PORT
      LAYER Metal3 ;
        RECT 0.000 385.360 0.400 385.760 ;
    END
  END Tile_X0Y0_FrameData[5]
  PIN Tile_X0Y0_FrameData[6]
    DIRECTION INPUT ;
    USE SIGNAL ;
    ANTENNAGATEAREA 1.807000 ;
    PORT
      LAYER Metal3 ;
        RECT 0.000 387.040 0.400 387.440 ;
    END
  END Tile_X0Y0_FrameData[6]
  PIN Tile_X0Y0_FrameData[7]
    DIRECTION INPUT ;
    USE SIGNAL ;
    ANTENNAGATEAREA 1.807000 ;
    PORT
      LAYER Metal3 ;
        RECT 0.000 388.720 0.400 389.120 ;
    END
  END Tile_X0Y0_FrameData[7]
  PIN Tile_X0Y0_FrameData[8]
    DIRECTION INPUT ;
    USE SIGNAL ;
    ANTENNAGATEAREA 1.807000 ;
    PORT
      LAYER Metal3 ;
        RECT 0.000 390.400 0.400 390.800 ;
    END
  END Tile_X0Y0_FrameData[8]
  PIN Tile_X0Y0_FrameData[9]
    DIRECTION INPUT ;
    USE SIGNAL ;
    ANTENNAGATEAREA 1.807000 ;
    PORT
      LAYER Metal3 ;
        RECT 0.000 392.080 0.400 392.480 ;
    END
  END Tile_X0Y0_FrameData[9]
  PIN Tile_X0Y0_FrameData_O[0]
    DIRECTION OUTPUT ;
    USE SIGNAL ;
    ANTENNADIFFAREA 0.708600 ;
    PORT
      LAYER Metal3 ;
        RECT 109.040 293.380 109.440 293.780 ;
    END
  END Tile_X0Y0_FrameData_O[0]
  PIN Tile_X0Y0_FrameData_O[10]
    DIRECTION OUTPUT ;
    USE SIGNAL ;
    ANTENNADIFFAREA 0.708600 ;
    PORT
      LAYER Metal3 ;
        RECT 109.040 335.380 109.440 335.780 ;
    END
  END Tile_X0Y0_FrameData_O[10]
  PIN Tile_X0Y0_FrameData_O[11]
    DIRECTION OUTPUT ;
    USE SIGNAL ;
    ANTENNADIFFAREA 0.708600 ;
    PORT
      LAYER Metal3 ;
        RECT 109.040 339.580 109.440 339.980 ;
    END
  END Tile_X0Y0_FrameData_O[11]
  PIN Tile_X0Y0_FrameData_O[12]
    DIRECTION OUTPUT ;
    USE SIGNAL ;
    ANTENNADIFFAREA 0.708600 ;
    PORT
      LAYER Metal3 ;
        RECT 109.040 343.780 109.440 344.180 ;
    END
  END Tile_X0Y0_FrameData_O[12]
  PIN Tile_X0Y0_FrameData_O[13]
    DIRECTION OUTPUT ;
    USE SIGNAL ;
    ANTENNADIFFAREA 0.708600 ;
    PORT
      LAYER Metal3 ;
        RECT 109.040 347.980 109.440 348.380 ;
    END
  END Tile_X0Y0_FrameData_O[13]
  PIN Tile_X0Y0_FrameData_O[14]
    DIRECTION OUTPUT ;
    USE SIGNAL ;
    ANTENNADIFFAREA 0.708600 ;
    PORT
      LAYER Metal3 ;
        RECT 109.040 352.180 109.440 352.580 ;
    END
  END Tile_X0Y0_FrameData_O[14]
  PIN Tile_X0Y0_FrameData_O[15]
    DIRECTION OUTPUT ;
    USE SIGNAL ;
    ANTENNADIFFAREA 0.708600 ;
    PORT
      LAYER Metal3 ;
        RECT 109.040 356.380 109.440 356.780 ;
    END
  END Tile_X0Y0_FrameData_O[15]
  PIN Tile_X0Y0_FrameData_O[16]
    DIRECTION OUTPUT ;
    USE SIGNAL ;
    ANTENNADIFFAREA 0.708600 ;
    PORT
      LAYER Metal3 ;
        RECT 109.040 360.580 109.440 360.980 ;
    END
  END Tile_X0Y0_FrameData_O[16]
  PIN Tile_X0Y0_FrameData_O[17]
    DIRECTION OUTPUT ;
    USE SIGNAL ;
    ANTENNADIFFAREA 0.708600 ;
    PORT
      LAYER Metal3 ;
        RECT 109.040 364.780 109.440 365.180 ;
    END
  END Tile_X0Y0_FrameData_O[17]
  PIN Tile_X0Y0_FrameData_O[18]
    DIRECTION OUTPUT ;
    USE SIGNAL ;
    ANTENNADIFFAREA 0.708600 ;
    PORT
      LAYER Metal3 ;
        RECT 109.040 368.980 109.440 369.380 ;
    END
  END Tile_X0Y0_FrameData_O[18]
  PIN Tile_X0Y0_FrameData_O[19]
    DIRECTION OUTPUT ;
    USE SIGNAL ;
    ANTENNADIFFAREA 0.708600 ;
    PORT
      LAYER Metal3 ;
        RECT 109.040 373.180 109.440 373.580 ;
    END
  END Tile_X0Y0_FrameData_O[19]
  PIN Tile_X0Y0_FrameData_O[1]
    DIRECTION OUTPUT ;
    USE SIGNAL ;
    ANTENNADIFFAREA 0.708600 ;
    PORT
      LAYER Metal3 ;
        RECT 109.040 297.580 109.440 297.980 ;
    END
  END Tile_X0Y0_FrameData_O[1]
  PIN Tile_X0Y0_FrameData_O[20]
    DIRECTION OUTPUT ;
    USE SIGNAL ;
    ANTENNADIFFAREA 0.708600 ;
    PORT
      LAYER Metal3 ;
        RECT 109.040 377.380 109.440 377.780 ;
    END
  END Tile_X0Y0_FrameData_O[20]
  PIN Tile_X0Y0_FrameData_O[21]
    DIRECTION OUTPUT ;
    USE SIGNAL ;
    ANTENNADIFFAREA 0.708600 ;
    PORT
      LAYER Metal3 ;
        RECT 109.040 381.580 109.440 381.980 ;
    END
  END Tile_X0Y0_FrameData_O[21]
  PIN Tile_X0Y0_FrameData_O[22]
    DIRECTION OUTPUT ;
    USE SIGNAL ;
    ANTENNADIFFAREA 0.708600 ;
    PORT
      LAYER Metal3 ;
        RECT 109.040 385.780 109.440 386.180 ;
    END
  END Tile_X0Y0_FrameData_O[22]
  PIN Tile_X0Y0_FrameData_O[23]
    DIRECTION OUTPUT ;
    USE SIGNAL ;
    ANTENNADIFFAREA 0.708600 ;
    PORT
      LAYER Metal3 ;
        RECT 109.040 389.980 109.440 390.380 ;
    END
  END Tile_X0Y0_FrameData_O[23]
  PIN Tile_X0Y0_FrameData_O[24]
    DIRECTION OUTPUT ;
    USE SIGNAL ;
    ANTENNADIFFAREA 0.708600 ;
    PORT
      LAYER Metal3 ;
        RECT 109.040 394.180 109.440 394.580 ;
    END
  END Tile_X0Y0_FrameData_O[24]
  PIN Tile_X0Y0_FrameData_O[25]
    DIRECTION OUTPUT ;
    USE SIGNAL ;
    ANTENNADIFFAREA 0.708600 ;
    PORT
      LAYER Metal3 ;
        RECT 109.040 398.380 109.440 398.780 ;
    END
  END Tile_X0Y0_FrameData_O[25]
  PIN Tile_X0Y0_FrameData_O[26]
    DIRECTION OUTPUT ;
    USE SIGNAL ;
    ANTENNADIFFAREA 0.708600 ;
    PORT
      LAYER Metal3 ;
        RECT 109.040 402.580 109.440 402.980 ;
    END
  END Tile_X0Y0_FrameData_O[26]
  PIN Tile_X0Y0_FrameData_O[27]
    DIRECTION OUTPUT ;
    USE SIGNAL ;
    ANTENNADIFFAREA 0.708600 ;
    PORT
      LAYER Metal3 ;
        RECT 109.040 406.780 109.440 407.180 ;
    END
  END Tile_X0Y0_FrameData_O[27]
  PIN Tile_X0Y0_FrameData_O[28]
    DIRECTION OUTPUT ;
    USE SIGNAL ;
    ANTENNADIFFAREA 0.708600 ;
    PORT
      LAYER Metal3 ;
        RECT 109.040 410.980 109.440 411.380 ;
    END
  END Tile_X0Y0_FrameData_O[28]
  PIN Tile_X0Y0_FrameData_O[29]
    DIRECTION OUTPUT ;
    USE SIGNAL ;
    ANTENNADIFFAREA 0.708600 ;
    PORT
      LAYER Metal3 ;
        RECT 109.040 415.180 109.440 415.580 ;
    END
  END Tile_X0Y0_FrameData_O[29]
  PIN Tile_X0Y0_FrameData_O[2]
    DIRECTION OUTPUT ;
    USE SIGNAL ;
    ANTENNADIFFAREA 0.708600 ;
    PORT
      LAYER Metal3 ;
        RECT 109.040 301.780 109.440 302.180 ;
    END
  END Tile_X0Y0_FrameData_O[2]
  PIN Tile_X0Y0_FrameData_O[30]
    DIRECTION OUTPUT ;
    USE SIGNAL ;
    ANTENNADIFFAREA 0.708600 ;
    PORT
      LAYER Metal3 ;
        RECT 109.040 419.380 109.440 419.780 ;
    END
  END Tile_X0Y0_FrameData_O[30]
  PIN Tile_X0Y0_FrameData_O[31]
    DIRECTION OUTPUT ;
    USE SIGNAL ;
    ANTENNADIFFAREA 0.708600 ;
    PORT
      LAYER Metal3 ;
        RECT 109.040 423.580 109.440 423.980 ;
    END
  END Tile_X0Y0_FrameData_O[31]
  PIN Tile_X0Y0_FrameData_O[3]
    DIRECTION OUTPUT ;
    USE SIGNAL ;
    ANTENNADIFFAREA 0.708600 ;
    PORT
      LAYER Metal3 ;
        RECT 109.040 305.980 109.440 306.380 ;
    END
  END Tile_X0Y0_FrameData_O[3]
  PIN Tile_X0Y0_FrameData_O[4]
    DIRECTION OUTPUT ;
    USE SIGNAL ;
    ANTENNADIFFAREA 0.708600 ;
    PORT
      LAYER Metal3 ;
        RECT 109.040 310.180 109.440 310.580 ;
    END
  END Tile_X0Y0_FrameData_O[4]
  PIN Tile_X0Y0_FrameData_O[5]
    DIRECTION OUTPUT ;
    USE SIGNAL ;
    ANTENNADIFFAREA 0.708600 ;
    PORT
      LAYER Metal3 ;
        RECT 109.040 314.380 109.440 314.780 ;
    END
  END Tile_X0Y0_FrameData_O[5]
  PIN Tile_X0Y0_FrameData_O[6]
    DIRECTION OUTPUT ;
    USE SIGNAL ;
    ANTENNADIFFAREA 0.708600 ;
    PORT
      LAYER Metal3 ;
        RECT 109.040 318.580 109.440 318.980 ;
    END
  END Tile_X0Y0_FrameData_O[6]
  PIN Tile_X0Y0_FrameData_O[7]
    DIRECTION OUTPUT ;
    USE SIGNAL ;
    ANTENNADIFFAREA 0.708600 ;
    PORT
      LAYER Metal3 ;
        RECT 109.040 322.780 109.440 323.180 ;
    END
  END Tile_X0Y0_FrameData_O[7]
  PIN Tile_X0Y0_FrameData_O[8]
    DIRECTION OUTPUT ;
    USE SIGNAL ;
    ANTENNADIFFAREA 0.708600 ;
    PORT
      LAYER Metal3 ;
        RECT 109.040 326.980 109.440 327.380 ;
    END
  END Tile_X0Y0_FrameData_O[8]
  PIN Tile_X0Y0_FrameData_O[9]
    DIRECTION OUTPUT ;
    USE SIGNAL ;
    ANTENNADIFFAREA 0.708600 ;
    PORT
      LAYER Metal3 ;
        RECT 109.040 331.180 109.440 331.580 ;
    END
  END Tile_X0Y0_FrameData_O[9]
  PIN Tile_X0Y0_FrameStrobe_O[0]
    DIRECTION OUTPUT ;
    USE SIGNAL ;
    ANTENNADIFFAREA 0.708600 ;
    PORT
      LAYER Metal2 ;
        RECT 79.960 430.520 80.360 430.920 ;
    END
  END Tile_X0Y0_FrameStrobe_O[0]
  PIN Tile_X0Y0_FrameStrobe_O[10]
    DIRECTION OUTPUT ;
    USE SIGNAL ;
    ANTENNADIFFAREA 0.708600 ;
    PORT
      LAYER Metal2 ;
        RECT 89.560 430.520 89.960 430.920 ;
    END
  END Tile_X0Y0_FrameStrobe_O[10]
  PIN Tile_X0Y0_FrameStrobe_O[11]
    DIRECTION OUTPUT ;
    USE SIGNAL ;
    ANTENNADIFFAREA 0.708600 ;
    PORT
      LAYER Metal2 ;
        RECT 90.520 430.520 90.920 430.920 ;
    END
  END Tile_X0Y0_FrameStrobe_O[11]
  PIN Tile_X0Y0_FrameStrobe_O[12]
    DIRECTION OUTPUT ;
    USE SIGNAL ;
    ANTENNADIFFAREA 0.708600 ;
    PORT
      LAYER Metal2 ;
        RECT 91.480 430.520 91.880 430.920 ;
    END
  END Tile_X0Y0_FrameStrobe_O[12]
  PIN Tile_X0Y0_FrameStrobe_O[13]
    DIRECTION OUTPUT ;
    USE SIGNAL ;
    ANTENNADIFFAREA 0.708600 ;
    PORT
      LAYER Metal2 ;
        RECT 92.440 430.520 92.840 430.920 ;
    END
  END Tile_X0Y0_FrameStrobe_O[13]
  PIN Tile_X0Y0_FrameStrobe_O[14]
    DIRECTION OUTPUT ;
    USE SIGNAL ;
    ANTENNADIFFAREA 0.708600 ;
    PORT
      LAYER Metal2 ;
        RECT 93.400 430.520 93.800 430.920 ;
    END
  END Tile_X0Y0_FrameStrobe_O[14]
  PIN Tile_X0Y0_FrameStrobe_O[15]
    DIRECTION OUTPUT ;
    USE SIGNAL ;
    ANTENNADIFFAREA 0.708600 ;
    PORT
      LAYER Metal2 ;
        RECT 94.360 430.520 94.760 430.920 ;
    END
  END Tile_X0Y0_FrameStrobe_O[15]
  PIN Tile_X0Y0_FrameStrobe_O[16]
    DIRECTION OUTPUT ;
    USE SIGNAL ;
    ANTENNADIFFAREA 0.708600 ;
    PORT
      LAYER Metal2 ;
        RECT 95.320 430.520 95.720 430.920 ;
    END
  END Tile_X0Y0_FrameStrobe_O[16]
  PIN Tile_X0Y0_FrameStrobe_O[17]
    DIRECTION OUTPUT ;
    USE SIGNAL ;
    ANTENNADIFFAREA 0.708600 ;
    PORT
      LAYER Metal2 ;
        RECT 96.280 430.520 96.680 430.920 ;
    END
  END Tile_X0Y0_FrameStrobe_O[17]
  PIN Tile_X0Y0_FrameStrobe_O[18]
    DIRECTION OUTPUT ;
    USE SIGNAL ;
    ANTENNADIFFAREA 0.708600 ;
    PORT
      LAYER Metal2 ;
        RECT 97.240 430.520 97.640 430.920 ;
    END
  END Tile_X0Y0_FrameStrobe_O[18]
  PIN Tile_X0Y0_FrameStrobe_O[19]
    DIRECTION OUTPUT ;
    USE SIGNAL ;
    ANTENNADIFFAREA 0.708600 ;
    PORT
      LAYER Metal2 ;
        RECT 98.200 430.520 98.600 430.920 ;
    END
  END Tile_X0Y0_FrameStrobe_O[19]
  PIN Tile_X0Y0_FrameStrobe_O[1]
    DIRECTION OUTPUT ;
    USE SIGNAL ;
    ANTENNADIFFAREA 0.708600 ;
    PORT
      LAYER Metal2 ;
        RECT 80.920 430.520 81.320 430.920 ;
    END
  END Tile_X0Y0_FrameStrobe_O[1]
  PIN Tile_X0Y0_FrameStrobe_O[2]
    DIRECTION OUTPUT ;
    USE SIGNAL ;
    ANTENNADIFFAREA 0.708600 ;
    PORT
      LAYER Metal2 ;
        RECT 81.880 430.520 82.280 430.920 ;
    END
  END Tile_X0Y0_FrameStrobe_O[2]
  PIN Tile_X0Y0_FrameStrobe_O[3]
    DIRECTION OUTPUT ;
    USE SIGNAL ;
    ANTENNADIFFAREA 0.708600 ;
    PORT
      LAYER Metal2 ;
        RECT 82.840 430.520 83.240 430.920 ;
    END
  END Tile_X0Y0_FrameStrobe_O[3]
  PIN Tile_X0Y0_FrameStrobe_O[4]
    DIRECTION OUTPUT ;
    USE SIGNAL ;
    ANTENNADIFFAREA 0.708600 ;
    PORT
      LAYER Metal2 ;
        RECT 83.800 430.520 84.200 430.920 ;
    END
  END Tile_X0Y0_FrameStrobe_O[4]
  PIN Tile_X0Y0_FrameStrobe_O[5]
    DIRECTION OUTPUT ;
    USE SIGNAL ;
    ANTENNADIFFAREA 0.708600 ;
    PORT
      LAYER Metal2 ;
        RECT 84.760 430.520 85.160 430.920 ;
    END
  END Tile_X0Y0_FrameStrobe_O[5]
  PIN Tile_X0Y0_FrameStrobe_O[6]
    DIRECTION OUTPUT ;
    USE SIGNAL ;
    ANTENNADIFFAREA 0.708600 ;
    PORT
      LAYER Metal2 ;
        RECT 85.720 430.520 86.120 430.920 ;
    END
  END Tile_X0Y0_FrameStrobe_O[6]
  PIN Tile_X0Y0_FrameStrobe_O[7]
    DIRECTION OUTPUT ;
    USE SIGNAL ;
    ANTENNADIFFAREA 0.708600 ;
    PORT
      LAYER Metal2 ;
        RECT 86.680 430.520 87.080 430.920 ;
    END
  END Tile_X0Y0_FrameStrobe_O[7]
  PIN Tile_X0Y0_FrameStrobe_O[8]
    DIRECTION OUTPUT ;
    USE SIGNAL ;
    ANTENNADIFFAREA 0.708600 ;
    PORT
      LAYER Metal2 ;
        RECT 87.640 430.520 88.040 430.920 ;
    END
  END Tile_X0Y0_FrameStrobe_O[8]
  PIN Tile_X0Y0_FrameStrobe_O[9]
    DIRECTION OUTPUT ;
    USE SIGNAL ;
    ANTENNADIFFAREA 0.708600 ;
    PORT
      LAYER Metal2 ;
        RECT 88.600 430.520 89.000 430.920 ;
    END
  END Tile_X0Y0_FrameStrobe_O[9]
  PIN Tile_X0Y0_N1BEG[0]
    DIRECTION OUTPUT ;
    USE SIGNAL ;
    ANTENNADIFFAREA 0.708600 ;
    PORT
      LAYER Metal2 ;
        RECT 9.880 430.520 10.280 430.920 ;
    END
  END Tile_X0Y0_N1BEG[0]
  PIN Tile_X0Y0_N1BEG[1]
    DIRECTION OUTPUT ;
    USE SIGNAL ;
    ANTENNADIFFAREA 0.708600 ;
    PORT
      LAYER Metal2 ;
        RECT 10.840 430.520 11.240 430.920 ;
    END
  END Tile_X0Y0_N1BEG[1]
  PIN Tile_X0Y0_N1BEG[2]
    DIRECTION OUTPUT ;
    USE SIGNAL ;
    ANTENNADIFFAREA 0.708600 ;
    PORT
      LAYER Metal2 ;
        RECT 11.800 430.520 12.200 430.920 ;
    END
  END Tile_X0Y0_N1BEG[2]
  PIN Tile_X0Y0_N1BEG[3]
    DIRECTION OUTPUT ;
    USE SIGNAL ;
    ANTENNADIFFAREA 0.708600 ;
    PORT
      LAYER Metal2 ;
        RECT 12.760 430.520 13.160 430.920 ;
    END
  END Tile_X0Y0_N1BEG[3]
  PIN Tile_X0Y0_N2BEG[0]
    DIRECTION OUTPUT ;
    USE SIGNAL ;
    ANTENNADIFFAREA 0.708600 ;
    PORT
      LAYER Metal2 ;
        RECT 13.720 430.520 14.120 430.920 ;
    END
  END Tile_X0Y0_N2BEG[0]
  PIN Tile_X0Y0_N2BEG[1]
    DIRECTION OUTPUT ;
    USE SIGNAL ;
    ANTENNADIFFAREA 0.708600 ;
    PORT
      LAYER Metal2 ;
        RECT 14.680 430.520 15.080 430.920 ;
    END
  END Tile_X0Y0_N2BEG[1]
  PIN Tile_X0Y0_N2BEG[2]
    DIRECTION OUTPUT ;
    USE SIGNAL ;
    ANTENNADIFFAREA 0.708600 ;
    PORT
      LAYER Metal2 ;
        RECT 15.640 430.520 16.040 430.920 ;
    END
  END Tile_X0Y0_N2BEG[2]
  PIN Tile_X0Y0_N2BEG[3]
    DIRECTION OUTPUT ;
    USE SIGNAL ;
    ANTENNADIFFAREA 0.708600 ;
    PORT
      LAYER Metal2 ;
        RECT 16.600 430.520 17.000 430.920 ;
    END
  END Tile_X0Y0_N2BEG[3]
  PIN Tile_X0Y0_N2BEG[4]
    DIRECTION OUTPUT ;
    USE SIGNAL ;
    ANTENNADIFFAREA 0.708600 ;
    PORT
      LAYER Metal2 ;
        RECT 17.560 430.520 17.960 430.920 ;
    END
  END Tile_X0Y0_N2BEG[4]
  PIN Tile_X0Y0_N2BEG[5]
    DIRECTION OUTPUT ;
    USE SIGNAL ;
    ANTENNADIFFAREA 0.708600 ;
    PORT
      LAYER Metal2 ;
        RECT 18.520 430.520 18.920 430.920 ;
    END
  END Tile_X0Y0_N2BEG[5]
  PIN Tile_X0Y0_N2BEG[6]
    DIRECTION OUTPUT ;
    USE SIGNAL ;
    ANTENNADIFFAREA 0.708600 ;
    PORT
      LAYER Metal2 ;
        RECT 19.480 430.520 19.880 430.920 ;
    END
  END Tile_X0Y0_N2BEG[6]
  PIN Tile_X0Y0_N2BEG[7]
    DIRECTION OUTPUT ;
    USE SIGNAL ;
    ANTENNADIFFAREA 0.708600 ;
    PORT
      LAYER Metal2 ;
        RECT 20.440 430.520 20.840 430.920 ;
    END
  END Tile_X0Y0_N2BEG[7]
  PIN Tile_X0Y0_N2BEGb[0]
    DIRECTION OUTPUT ;
    USE SIGNAL ;
    ANTENNADIFFAREA 0.708600 ;
    PORT
      LAYER Metal2 ;
        RECT 21.400 430.520 21.800 430.920 ;
    END
  END Tile_X0Y0_N2BEGb[0]
  PIN Tile_X0Y0_N2BEGb[1]
    DIRECTION OUTPUT ;
    USE SIGNAL ;
    ANTENNADIFFAREA 0.708600 ;
    PORT
      LAYER Metal2 ;
        RECT 22.360 430.520 22.760 430.920 ;
    END
  END Tile_X0Y0_N2BEGb[1]
  PIN Tile_X0Y0_N2BEGb[2]
    DIRECTION OUTPUT ;
    USE SIGNAL ;
    ANTENNADIFFAREA 0.708600 ;
    PORT
      LAYER Metal2 ;
        RECT 23.320 430.520 23.720 430.920 ;
    END
  END Tile_X0Y0_N2BEGb[2]
  PIN Tile_X0Y0_N2BEGb[3]
    DIRECTION OUTPUT ;
    USE SIGNAL ;
    ANTENNADIFFAREA 0.708600 ;
    PORT
      LAYER Metal2 ;
        RECT 24.280 430.520 24.680 430.920 ;
    END
  END Tile_X0Y0_N2BEGb[3]
  PIN Tile_X0Y0_N2BEGb[4]
    DIRECTION OUTPUT ;
    USE SIGNAL ;
    ANTENNADIFFAREA 0.708600 ;
    PORT
      LAYER Metal2 ;
        RECT 25.240 430.520 25.640 430.920 ;
    END
  END Tile_X0Y0_N2BEGb[4]
  PIN Tile_X0Y0_N2BEGb[5]
    DIRECTION OUTPUT ;
    USE SIGNAL ;
    ANTENNADIFFAREA 0.708600 ;
    PORT
      LAYER Metal2 ;
        RECT 26.200 430.520 26.600 430.920 ;
    END
  END Tile_X0Y0_N2BEGb[5]
  PIN Tile_X0Y0_N2BEGb[6]
    DIRECTION OUTPUT ;
    USE SIGNAL ;
    ANTENNADIFFAREA 0.708600 ;
    PORT
      LAYER Metal2 ;
        RECT 27.160 430.520 27.560 430.920 ;
    END
  END Tile_X0Y0_N2BEGb[6]
  PIN Tile_X0Y0_N2BEGb[7]
    DIRECTION OUTPUT ;
    USE SIGNAL ;
    ANTENNADIFFAREA 0.708600 ;
    PORT
      LAYER Metal2 ;
        RECT 28.120 430.520 28.520 430.920 ;
    END
  END Tile_X0Y0_N2BEGb[7]
  PIN Tile_X0Y0_N4BEG[0]
    DIRECTION OUTPUT ;
    USE SIGNAL ;
    ANTENNADIFFAREA 0.708600 ;
    PORT
      LAYER Metal2 ;
        RECT 29.080 430.520 29.480 430.920 ;
    END
  END Tile_X0Y0_N4BEG[0]
  PIN Tile_X0Y0_N4BEG[10]
    DIRECTION OUTPUT ;
    USE SIGNAL ;
    ANTENNADIFFAREA 0.708600 ;
    PORT
      LAYER Metal2 ;
        RECT 38.680 430.520 39.080 430.920 ;
    END
  END Tile_X0Y0_N4BEG[10]
  PIN Tile_X0Y0_N4BEG[11]
    DIRECTION OUTPUT ;
    USE SIGNAL ;
    ANTENNADIFFAREA 0.708600 ;
    PORT
      LAYER Metal2 ;
        RECT 39.640 430.520 40.040 430.920 ;
    END
  END Tile_X0Y0_N4BEG[11]
  PIN Tile_X0Y0_N4BEG[12]
    DIRECTION OUTPUT ;
    USE SIGNAL ;
    ANTENNADIFFAREA 0.708600 ;
    PORT
      LAYER Metal2 ;
        RECT 40.600 430.520 41.000 430.920 ;
    END
  END Tile_X0Y0_N4BEG[12]
  PIN Tile_X0Y0_N4BEG[13]
    DIRECTION OUTPUT ;
    USE SIGNAL ;
    ANTENNADIFFAREA 0.708600 ;
    PORT
      LAYER Metal2 ;
        RECT 41.560 430.520 41.960 430.920 ;
    END
  END Tile_X0Y0_N4BEG[13]
  PIN Tile_X0Y0_N4BEG[14]
    DIRECTION OUTPUT ;
    USE SIGNAL ;
    ANTENNADIFFAREA 0.708600 ;
    PORT
      LAYER Metal2 ;
        RECT 42.520 430.520 42.920 430.920 ;
    END
  END Tile_X0Y0_N4BEG[14]
  PIN Tile_X0Y0_N4BEG[15]
    DIRECTION OUTPUT ;
    USE SIGNAL ;
    ANTENNADIFFAREA 0.708600 ;
    PORT
      LAYER Metal2 ;
        RECT 43.480 430.520 43.880 430.920 ;
    END
  END Tile_X0Y0_N4BEG[15]
  PIN Tile_X0Y0_N4BEG[1]
    DIRECTION OUTPUT ;
    USE SIGNAL ;
    ANTENNADIFFAREA 0.708600 ;
    PORT
      LAYER Metal2 ;
        RECT 30.040 430.520 30.440 430.920 ;
    END
  END Tile_X0Y0_N4BEG[1]
  PIN Tile_X0Y0_N4BEG[2]
    DIRECTION OUTPUT ;
    USE SIGNAL ;
    ANTENNADIFFAREA 0.708600 ;
    PORT
      LAYER Metal2 ;
        RECT 31.000 430.520 31.400 430.920 ;
    END
  END Tile_X0Y0_N4BEG[2]
  PIN Tile_X0Y0_N4BEG[3]
    DIRECTION OUTPUT ;
    USE SIGNAL ;
    ANTENNADIFFAREA 0.708600 ;
    PORT
      LAYER Metal2 ;
        RECT 31.960 430.520 32.360 430.920 ;
    END
  END Tile_X0Y0_N4BEG[3]
  PIN Tile_X0Y0_N4BEG[4]
    DIRECTION OUTPUT ;
    USE SIGNAL ;
    ANTENNADIFFAREA 0.708600 ;
    PORT
      LAYER Metal2 ;
        RECT 32.920 430.520 33.320 430.920 ;
    END
  END Tile_X0Y0_N4BEG[4]
  PIN Tile_X0Y0_N4BEG[5]
    DIRECTION OUTPUT ;
    USE SIGNAL ;
    ANTENNADIFFAREA 0.708600 ;
    PORT
      LAYER Metal2 ;
        RECT 33.880 430.520 34.280 430.920 ;
    END
  END Tile_X0Y0_N4BEG[5]
  PIN Tile_X0Y0_N4BEG[6]
    DIRECTION OUTPUT ;
    USE SIGNAL ;
    ANTENNADIFFAREA 0.708600 ;
    PORT
      LAYER Metal2 ;
        RECT 34.840 430.520 35.240 430.920 ;
    END
  END Tile_X0Y0_N4BEG[6]
  PIN Tile_X0Y0_N4BEG[7]
    DIRECTION OUTPUT ;
    USE SIGNAL ;
    ANTENNADIFFAREA 0.708600 ;
    PORT
      LAYER Metal2 ;
        RECT 35.800 430.520 36.200 430.920 ;
    END
  END Tile_X0Y0_N4BEG[7]
  PIN Tile_X0Y0_N4BEG[8]
    DIRECTION OUTPUT ;
    USE SIGNAL ;
    ANTENNADIFFAREA 0.708600 ;
    PORT
      LAYER Metal2 ;
        RECT 36.760 430.520 37.160 430.920 ;
    END
  END Tile_X0Y0_N4BEG[8]
  PIN Tile_X0Y0_N4BEG[9]
    DIRECTION OUTPUT ;
    USE SIGNAL ;
    ANTENNADIFFAREA 0.708600 ;
    PORT
      LAYER Metal2 ;
        RECT 37.720 430.520 38.120 430.920 ;
    END
  END Tile_X0Y0_N4BEG[9]
  PIN Tile_X0Y0_S1END[0]
    DIRECTION INPUT ;
    USE SIGNAL ;
    ANTENNAGATEAREA 1.307800 ;
    PORT
      LAYER Metal2 ;
        RECT 44.440 430.520 44.840 430.920 ;
    END
  END Tile_X0Y0_S1END[0]
  PIN Tile_X0Y0_S1END[1]
    DIRECTION INPUT ;
    USE SIGNAL ;
    ANTENNAGATEAREA 1.307800 ;
    PORT
      LAYER Metal2 ;
        RECT 45.400 430.520 45.800 430.920 ;
    END
  END Tile_X0Y0_S1END[1]
  PIN Tile_X0Y0_S1END[2]
    DIRECTION INPUT ;
    USE SIGNAL ;
    ANTENNAGATEAREA 1.307800 ;
    PORT
      LAYER Metal2 ;
        RECT 46.360 430.520 46.760 430.920 ;
    END
  END Tile_X0Y0_S1END[2]
  PIN Tile_X0Y0_S1END[3]
    DIRECTION INPUT ;
    USE SIGNAL ;
    ANTENNAGATEAREA 1.307800 ;
    PORT
      LAYER Metal2 ;
        RECT 47.320 430.520 47.720 430.920 ;
    END
  END Tile_X0Y0_S1END[3]
  PIN Tile_X0Y0_S2END[0]
    DIRECTION INPUT ;
    USE SIGNAL ;
    ANTENNAGATEAREA 0.213200 ;
    PORT
      LAYER Metal2 ;
        RECT 55.960 430.520 56.360 430.920 ;
    END
  END Tile_X0Y0_S2END[0]
  PIN Tile_X0Y0_S2END[1]
    DIRECTION INPUT ;
    USE SIGNAL ;
    ANTENNAGATEAREA 0.213200 ;
    PORT
      LAYER Metal2 ;
        RECT 56.920 430.520 57.320 430.920 ;
    END
  END Tile_X0Y0_S2END[1]
  PIN Tile_X0Y0_S2END[2]
    DIRECTION INPUT ;
    USE SIGNAL ;
    ANTENNAGATEAREA 0.213200 ;
    PORT
      LAYER Metal2 ;
        RECT 57.880 430.520 58.280 430.920 ;
    END
  END Tile_X0Y0_S2END[2]
  PIN Tile_X0Y0_S2END[3]
    DIRECTION INPUT ;
    USE SIGNAL ;
    ANTENNAGATEAREA 0.213200 ;
    PORT
      LAYER Metal2 ;
        RECT 58.840 430.520 59.240 430.920 ;
    END
  END Tile_X0Y0_S2END[3]
  PIN Tile_X0Y0_S2END[4]
    DIRECTION INPUT ;
    USE SIGNAL ;
    ANTENNAGATEAREA 0.213200 ;
    PORT
      LAYER Metal2 ;
        RECT 59.800 430.520 60.200 430.920 ;
    END
  END Tile_X0Y0_S2END[4]
  PIN Tile_X0Y0_S2END[5]
    DIRECTION INPUT ;
    USE SIGNAL ;
    ANTENNAGATEAREA 0.213200 ;
    PORT
      LAYER Metal2 ;
        RECT 60.760 430.520 61.160 430.920 ;
    END
  END Tile_X0Y0_S2END[5]
  PIN Tile_X0Y0_S2END[6]
    DIRECTION INPUT ;
    USE SIGNAL ;
    ANTENNAGATEAREA 0.213200 ;
    PORT
      LAYER Metal2 ;
        RECT 61.720 430.520 62.120 430.920 ;
    END
  END Tile_X0Y0_S2END[6]
  PIN Tile_X0Y0_S2END[7]
    DIRECTION INPUT ;
    USE SIGNAL ;
    ANTENNAGATEAREA 0.213200 ;
    PORT
      LAYER Metal2 ;
        RECT 62.680 430.520 63.080 430.920 ;
    END
  END Tile_X0Y0_S2END[7]
  PIN Tile_X0Y0_S2MID[0]
    DIRECTION INPUT ;
    USE SIGNAL ;
    ANTENNAGATEAREA 0.426400 ;
    PORT
      LAYER Metal2 ;
        RECT 48.280 430.520 48.680 430.920 ;
    END
  END Tile_X0Y0_S2MID[0]
  PIN Tile_X0Y0_S2MID[1]
    DIRECTION INPUT ;
    USE SIGNAL ;
    ANTENNAGATEAREA 0.426400 ;
    PORT
      LAYER Metal2 ;
        RECT 49.240 430.520 49.640 430.920 ;
    END
  END Tile_X0Y0_S2MID[1]
  PIN Tile_X0Y0_S2MID[2]
    DIRECTION INPUT ;
    USE SIGNAL ;
    ANTENNAGATEAREA 0.910000 ;
    PORT
      LAYER Metal2 ;
        RECT 50.200 430.520 50.600 430.920 ;
    END
  END Tile_X0Y0_S2MID[2]
  PIN Tile_X0Y0_S2MID[3]
    DIRECTION INPUT ;
    USE SIGNAL ;
    ANTENNAGATEAREA 1.127900 ;
    PORT
      LAYER Metal2 ;
        RECT 51.160 430.520 51.560 430.920 ;
    END
  END Tile_X0Y0_S2MID[3]
  PIN Tile_X0Y0_S2MID[4]
    DIRECTION INPUT ;
    USE SIGNAL ;
    ANTENNAGATEAREA 0.426400 ;
    PORT
      LAYER Metal2 ;
        RECT 52.120 430.520 52.520 430.920 ;
    END
  END Tile_X0Y0_S2MID[4]
  PIN Tile_X0Y0_S2MID[5]
    DIRECTION INPUT ;
    USE SIGNAL ;
    ANTENNAGATEAREA 3.468400 ;
    ANTENNADIFFAREA 10.077000 ;
    PORT
      LAYER Metal2 ;
        RECT 53.080 430.520 53.480 430.920 ;
    END
  END Tile_X0Y0_S2MID[5]
  PIN Tile_X0Y0_S2MID[6]
    DIRECTION INPUT ;
    USE SIGNAL ;
    ANTENNAGATEAREA 0.426400 ;
    PORT
      LAYER Metal2 ;
        RECT 54.040 430.520 54.440 430.920 ;
    END
  END Tile_X0Y0_S2MID[6]
  PIN Tile_X0Y0_S2MID[7]
    DIRECTION INPUT ;
    USE SIGNAL ;
    ANTENNAGATEAREA 1.643200 ;
    ANTENNADIFFAREA 4.030800 ;
    PORT
      LAYER Metal2 ;
        RECT 55.000 430.520 55.400 430.920 ;
    END
  END Tile_X0Y0_S2MID[7]
  PIN Tile_X0Y0_S4END[0]
    DIRECTION INPUT ;
    USE SIGNAL ;
    ANTENNAGATEAREA 1.066000 ;
    PORT
      LAYER Metal2 ;
        RECT 63.640 430.520 64.040 430.920 ;
    END
  END Tile_X0Y0_S4END[0]
  PIN Tile_X0Y0_S4END[10]
    DIRECTION INPUT ;
    USE SIGNAL ;
    ANTENNAGATEAREA 2.005900 ;
    ANTENNADIFFAREA 6.046200 ;
    PORT
      LAYER Metal2 ;
        RECT 73.240 430.520 73.640 430.920 ;
    END
  END Tile_X0Y0_S4END[10]
  PIN Tile_X0Y0_S4END[11]
    DIRECTION INPUT ;
    USE SIGNAL ;
    ANTENNAGATEAREA 0.180700 ;
    PORT
      LAYER Metal2 ;
        RECT 74.200 430.520 74.600 430.920 ;
    END
  END Tile_X0Y0_S4END[11]
  PIN Tile_X0Y0_S4END[12]
    DIRECTION INPUT ;
    USE SIGNAL ;
    ANTENNAGATEAREA 0.180700 ;
    PORT
      LAYER Metal2 ;
        RECT 75.160 430.520 75.560 430.920 ;
    END
  END Tile_X0Y0_S4END[12]
  PIN Tile_X0Y0_S4END[13]
    DIRECTION INPUT ;
    USE SIGNAL ;
    ANTENNAGATEAREA 0.180700 ;
    PORT
      LAYER Metal2 ;
        RECT 76.120 430.520 76.520 430.920 ;
    END
  END Tile_X0Y0_S4END[13]
  PIN Tile_X0Y0_S4END[14]
    DIRECTION INPUT ;
    USE SIGNAL ;
    ANTENNAGATEAREA 0.180700 ;
    PORT
      LAYER Metal2 ;
        RECT 77.080 430.520 77.480 430.920 ;
    END
  END Tile_X0Y0_S4END[14]
  PIN Tile_X0Y0_S4END[15]
    DIRECTION INPUT ;
    USE SIGNAL ;
    ANTENNAGATEAREA 0.180700 ;
    PORT
      LAYER Metal2 ;
        RECT 78.040 430.520 78.440 430.920 ;
    END
  END Tile_X0Y0_S4END[15]
  PIN Tile_X0Y0_S4END[1]
    DIRECTION INPUT ;
    USE SIGNAL ;
    ANTENNAGATEAREA 1.066000 ;
    PORT
      LAYER Metal2 ;
        RECT 64.600 430.520 65.000 430.920 ;
    END
  END Tile_X0Y0_S4END[1]
  PIN Tile_X0Y0_S4END[2]
    DIRECTION INPUT ;
    USE SIGNAL ;
    ANTENNAGATEAREA 1.066000 ;
    PORT
      LAYER Metal2 ;
        RECT 65.560 430.520 65.960 430.920 ;
    END
  END Tile_X0Y0_S4END[2]
  PIN Tile_X0Y0_S4END[3]
    DIRECTION INPUT ;
    USE SIGNAL ;
    ANTENNAGATEAREA 1.066000 ;
    PORT
      LAYER Metal2 ;
        RECT 66.520 430.520 66.920 430.920 ;
    END
  END Tile_X0Y0_S4END[3]
  PIN Tile_X0Y0_S4END[4]
    DIRECTION INPUT ;
    USE SIGNAL ;
    ANTENNAGATEAREA 1.066000 ;
    PORT
      LAYER Metal2 ;
        RECT 67.480 430.520 67.880 430.920 ;
    END
  END Tile_X0Y0_S4END[4]
  PIN Tile_X0Y0_S4END[5]
    DIRECTION INPUT ;
    USE SIGNAL ;
    ANTENNAGATEAREA 1.066000 ;
    PORT
      LAYER Metal2 ;
        RECT 68.440 430.520 68.840 430.920 ;
    END
  END Tile_X0Y0_S4END[5]
  PIN Tile_X0Y0_S4END[6]
    DIRECTION INPUT ;
    USE SIGNAL ;
    ANTENNAGATEAREA 1.066000 ;
    PORT
      LAYER Metal2 ;
        RECT 69.400 430.520 69.800 430.920 ;
    END
  END Tile_X0Y0_S4END[6]
  PIN Tile_X0Y0_S4END[7]
    DIRECTION INPUT ;
    USE SIGNAL ;
    ANTENNAGATEAREA 1.066000 ;
    PORT
      LAYER Metal2 ;
        RECT 70.360 430.520 70.760 430.920 ;
    END
  END Tile_X0Y0_S4END[7]
  PIN Tile_X0Y0_S4END[8]
    DIRECTION INPUT ;
    USE SIGNAL ;
    ANTENNAGATEAREA 0.789100 ;
    ANTENNADIFFAREA 2.015400 ;
    PORT
      LAYER Metal2 ;
        RECT 71.320 430.520 71.720 430.920 ;
    END
  END Tile_X0Y0_S4END[8]
  PIN Tile_X0Y0_S4END[9]
    DIRECTION INPUT ;
    USE SIGNAL ;
    ANTENNAGATEAREA 0.789100 ;
    ANTENNADIFFAREA 2.015400 ;
    PORT
      LAYER Metal2 ;
        RECT 72.280 430.520 72.680 430.920 ;
    END
  END Tile_X0Y0_S4END[9]
  PIN Tile_X0Y0_UserCLKo
    DIRECTION OUTPUT ;
    USE SIGNAL ;
    ANTENNADIFFAREA 0.708600 ;
    PORT
      LAYER Metal2 ;
        RECT 79.000 430.520 79.400 430.920 ;
    END
  END Tile_X0Y0_UserCLKo
  PIN Tile_X0Y0_W1BEG[0]
    DIRECTION OUTPUT ;
    USE SIGNAL ;
    ANTENNADIFFAREA 0.708600 ;
    PORT
      LAYER Metal3 ;
        RECT 0.000 215.680 0.400 216.080 ;
    END
  END Tile_X0Y0_W1BEG[0]
  PIN Tile_X0Y0_W1BEG[1]
    DIRECTION OUTPUT ;
    USE SIGNAL ;
    ANTENNADIFFAREA 0.708600 ;
    PORT
      LAYER Metal3 ;
        RECT 0.000 217.360 0.400 217.760 ;
    END
  END Tile_X0Y0_W1BEG[1]
  PIN Tile_X0Y0_W1BEG[2]
    DIRECTION OUTPUT ;
    USE SIGNAL ;
    ANTENNADIFFAREA 0.708600 ;
    PORT
      LAYER Metal3 ;
        RECT 0.000 219.040 0.400 219.440 ;
    END
  END Tile_X0Y0_W1BEG[2]
  PIN Tile_X0Y0_W1BEG[3]
    DIRECTION OUTPUT ;
    USE SIGNAL ;
    ANTENNADIFFAREA 0.708600 ;
    PORT
      LAYER Metal3 ;
        RECT 0.000 220.720 0.400 221.120 ;
    END
  END Tile_X0Y0_W1BEG[3]
  PIN Tile_X0Y0_W2BEG[0]
    DIRECTION OUTPUT ;
    USE SIGNAL ;
    ANTENNADIFFAREA 0.708600 ;
    PORT
      LAYER Metal3 ;
        RECT 0.000 222.400 0.400 222.800 ;
    END
  END Tile_X0Y0_W2BEG[0]
  PIN Tile_X0Y0_W2BEG[1]
    DIRECTION OUTPUT ;
    USE SIGNAL ;
    ANTENNADIFFAREA 0.708600 ;
    PORT
      LAYER Metal3 ;
        RECT 0.000 224.080 0.400 224.480 ;
    END
  END Tile_X0Y0_W2BEG[1]
  PIN Tile_X0Y0_W2BEG[2]
    DIRECTION OUTPUT ;
    USE SIGNAL ;
    ANTENNADIFFAREA 0.708600 ;
    PORT
      LAYER Metal3 ;
        RECT 0.000 225.760 0.400 226.160 ;
    END
  END Tile_X0Y0_W2BEG[2]
  PIN Tile_X0Y0_W2BEG[3]
    DIRECTION OUTPUT ;
    USE SIGNAL ;
    ANTENNADIFFAREA 0.708600 ;
    PORT
      LAYER Metal3 ;
        RECT 0.000 227.440 0.400 227.840 ;
    END
  END Tile_X0Y0_W2BEG[3]
  PIN Tile_X0Y0_W2BEG[4]
    DIRECTION OUTPUT ;
    USE SIGNAL ;
    ANTENNADIFFAREA 0.708600 ;
    PORT
      LAYER Metal3 ;
        RECT 0.000 229.120 0.400 229.520 ;
    END
  END Tile_X0Y0_W2BEG[4]
  PIN Tile_X0Y0_W2BEG[5]
    DIRECTION OUTPUT ;
    USE SIGNAL ;
    ANTENNADIFFAREA 0.708600 ;
    PORT
      LAYER Metal3 ;
        RECT 0.000 230.800 0.400 231.200 ;
    END
  END Tile_X0Y0_W2BEG[5]
  PIN Tile_X0Y0_W2BEG[6]
    DIRECTION OUTPUT ;
    USE SIGNAL ;
    ANTENNADIFFAREA 0.708600 ;
    PORT
      LAYER Metal3 ;
        RECT 0.000 232.480 0.400 232.880 ;
    END
  END Tile_X0Y0_W2BEG[6]
  PIN Tile_X0Y0_W2BEG[7]
    DIRECTION OUTPUT ;
    USE SIGNAL ;
    ANTENNADIFFAREA 0.708600 ;
    PORT
      LAYER Metal3 ;
        RECT 0.000 234.160 0.400 234.560 ;
    END
  END Tile_X0Y0_W2BEG[7]
  PIN Tile_X0Y0_W2BEGb[0]
    DIRECTION OUTPUT ;
    USE SIGNAL ;
    ANTENNADIFFAREA 0.708600 ;
    PORT
      LAYER Metal3 ;
        RECT 0.000 235.840 0.400 236.240 ;
    END
  END Tile_X0Y0_W2BEGb[0]
  PIN Tile_X0Y0_W2BEGb[1]
    DIRECTION OUTPUT ;
    USE SIGNAL ;
    ANTENNADIFFAREA 0.708600 ;
    PORT
      LAYER Metal3 ;
        RECT 0.000 237.520 0.400 237.920 ;
    END
  END Tile_X0Y0_W2BEGb[1]
  PIN Tile_X0Y0_W2BEGb[2]
    DIRECTION OUTPUT ;
    USE SIGNAL ;
    ANTENNADIFFAREA 0.708600 ;
    PORT
      LAYER Metal3 ;
        RECT 0.000 239.200 0.400 239.600 ;
    END
  END Tile_X0Y0_W2BEGb[2]
  PIN Tile_X0Y0_W2BEGb[3]
    DIRECTION OUTPUT ;
    USE SIGNAL ;
    ANTENNADIFFAREA 0.708600 ;
    PORT
      LAYER Metal3 ;
        RECT 0.000 240.880 0.400 241.280 ;
    END
  END Tile_X0Y0_W2BEGb[3]
  PIN Tile_X0Y0_W2BEGb[4]
    DIRECTION OUTPUT ;
    USE SIGNAL ;
    ANTENNADIFFAREA 0.708600 ;
    PORT
      LAYER Metal3 ;
        RECT 0.000 242.560 0.400 242.960 ;
    END
  END Tile_X0Y0_W2BEGb[4]
  PIN Tile_X0Y0_W2BEGb[5]
    DIRECTION OUTPUT ;
    USE SIGNAL ;
    ANTENNADIFFAREA 0.708600 ;
    PORT
      LAYER Metal3 ;
        RECT 0.000 244.240 0.400 244.640 ;
    END
  END Tile_X0Y0_W2BEGb[5]
  PIN Tile_X0Y0_W2BEGb[6]
    DIRECTION OUTPUT ;
    USE SIGNAL ;
    ANTENNADIFFAREA 0.708600 ;
    PORT
      LAYER Metal3 ;
        RECT 0.000 245.920 0.400 246.320 ;
    END
  END Tile_X0Y0_W2BEGb[6]
  PIN Tile_X0Y0_W2BEGb[7]
    DIRECTION OUTPUT ;
    USE SIGNAL ;
    ANTENNADIFFAREA 0.708600 ;
    PORT
      LAYER Metal3 ;
        RECT 0.000 247.600 0.400 248.000 ;
    END
  END Tile_X0Y0_W2BEGb[7]
  PIN Tile_X0Y0_W6BEG[0]
    DIRECTION OUTPUT ;
    USE SIGNAL ;
    ANTENNADIFFAREA 0.708600 ;
    PORT
      LAYER Metal3 ;
        RECT 0.000 276.160 0.400 276.560 ;
    END
  END Tile_X0Y0_W6BEG[0]
  PIN Tile_X0Y0_W6BEG[10]
    DIRECTION OUTPUT ;
    USE SIGNAL ;
    ANTENNADIFFAREA 0.708600 ;
    PORT
      LAYER Metal3 ;
        RECT 0.000 292.960 0.400 293.360 ;
    END
  END Tile_X0Y0_W6BEG[10]
  PIN Tile_X0Y0_W6BEG[11]
    DIRECTION OUTPUT ;
    USE SIGNAL ;
    ANTENNADIFFAREA 0.708600 ;
    PORT
      LAYER Metal3 ;
        RECT 0.000 294.640 0.400 295.040 ;
    END
  END Tile_X0Y0_W6BEG[11]
  PIN Tile_X0Y0_W6BEG[1]
    DIRECTION OUTPUT ;
    USE SIGNAL ;
    ANTENNADIFFAREA 0.708600 ;
    PORT
      LAYER Metal3 ;
        RECT 0.000 277.840 0.400 278.240 ;
    END
  END Tile_X0Y0_W6BEG[1]
  PIN Tile_X0Y0_W6BEG[2]
    DIRECTION OUTPUT ;
    USE SIGNAL ;
    ANTENNADIFFAREA 0.708600 ;
    PORT
      LAYER Metal3 ;
        RECT 0.000 279.520 0.400 279.920 ;
    END
  END Tile_X0Y0_W6BEG[2]
  PIN Tile_X0Y0_W6BEG[3]
    DIRECTION OUTPUT ;
    USE SIGNAL ;
    ANTENNADIFFAREA 0.708600 ;
    PORT
      LAYER Metal3 ;
        RECT 0.000 281.200 0.400 281.600 ;
    END
  END Tile_X0Y0_W6BEG[3]
  PIN Tile_X0Y0_W6BEG[4]
    DIRECTION OUTPUT ;
    USE SIGNAL ;
    ANTENNADIFFAREA 0.708600 ;
    PORT
      LAYER Metal3 ;
        RECT 0.000 282.880 0.400 283.280 ;
    END
  END Tile_X0Y0_W6BEG[4]
  PIN Tile_X0Y0_W6BEG[5]
    DIRECTION OUTPUT ;
    USE SIGNAL ;
    ANTENNADIFFAREA 0.708600 ;
    PORT
      LAYER Metal3 ;
        RECT 0.000 284.560 0.400 284.960 ;
    END
  END Tile_X0Y0_W6BEG[5]
  PIN Tile_X0Y0_W6BEG[6]
    DIRECTION OUTPUT ;
    USE SIGNAL ;
    ANTENNADIFFAREA 0.708600 ;
    PORT
      LAYER Metal3 ;
        RECT 0.000 286.240 0.400 286.640 ;
    END
  END Tile_X0Y0_W6BEG[6]
  PIN Tile_X0Y0_W6BEG[7]
    DIRECTION OUTPUT ;
    USE SIGNAL ;
    ANTENNADIFFAREA 0.708600 ;
    PORT
      LAYER Metal3 ;
        RECT 0.000 287.920 0.400 288.320 ;
    END
  END Tile_X0Y0_W6BEG[7]
  PIN Tile_X0Y0_W6BEG[8]
    DIRECTION OUTPUT ;
    USE SIGNAL ;
    ANTENNADIFFAREA 0.708600 ;
    PORT
      LAYER Metal3 ;
        RECT 0.000 289.600 0.400 290.000 ;
    END
  END Tile_X0Y0_W6BEG[8]
  PIN Tile_X0Y0_W6BEG[9]
    DIRECTION OUTPUT ;
    USE SIGNAL ;
    ANTENNADIFFAREA 0.708600 ;
    PORT
      LAYER Metal3 ;
        RECT 0.000 291.280 0.400 291.680 ;
    END
  END Tile_X0Y0_W6BEG[9]
  PIN Tile_X0Y0_WW4BEG[0]
    DIRECTION OUTPUT ;
    USE SIGNAL ;
    ANTENNADIFFAREA 0.708600 ;
    PORT
      LAYER Metal3 ;
        RECT 0.000 249.280 0.400 249.680 ;
    END
  END Tile_X0Y0_WW4BEG[0]
  PIN Tile_X0Y0_WW4BEG[10]
    DIRECTION OUTPUT ;
    USE SIGNAL ;
    ANTENNADIFFAREA 0.708600 ;
    PORT
      LAYER Metal3 ;
        RECT 0.000 266.080 0.400 266.480 ;
    END
  END Tile_X0Y0_WW4BEG[10]
  PIN Tile_X0Y0_WW4BEG[11]
    DIRECTION OUTPUT ;
    USE SIGNAL ;
    ANTENNADIFFAREA 0.708600 ;
    PORT
      LAYER Metal3 ;
        RECT 0.000 267.760 0.400 268.160 ;
    END
  END Tile_X0Y0_WW4BEG[11]
  PIN Tile_X0Y0_WW4BEG[12]
    DIRECTION OUTPUT ;
    USE SIGNAL ;
    ANTENNADIFFAREA 0.708600 ;
    PORT
      LAYER Metal3 ;
        RECT 0.000 269.440 0.400 269.840 ;
    END
  END Tile_X0Y0_WW4BEG[12]
  PIN Tile_X0Y0_WW4BEG[13]
    DIRECTION OUTPUT ;
    USE SIGNAL ;
    ANTENNADIFFAREA 0.708600 ;
    PORT
      LAYER Metal3 ;
        RECT 0.000 271.120 0.400 271.520 ;
    END
  END Tile_X0Y0_WW4BEG[13]
  PIN Tile_X0Y0_WW4BEG[14]
    DIRECTION OUTPUT ;
    USE SIGNAL ;
    ANTENNADIFFAREA 0.708600 ;
    PORT
      LAYER Metal3 ;
        RECT 0.000 272.800 0.400 273.200 ;
    END
  END Tile_X0Y0_WW4BEG[14]
  PIN Tile_X0Y0_WW4BEG[15]
    DIRECTION OUTPUT ;
    USE SIGNAL ;
    ANTENNADIFFAREA 0.708600 ;
    PORT
      LAYER Metal3 ;
        RECT 0.000 274.480 0.400 274.880 ;
    END
  END Tile_X0Y0_WW4BEG[15]
  PIN Tile_X0Y0_WW4BEG[1]
    DIRECTION OUTPUT ;
    USE SIGNAL ;
    ANTENNADIFFAREA 0.708600 ;
    PORT
      LAYER Metal3 ;
        RECT 0.000 250.960 0.400 251.360 ;
    END
  END Tile_X0Y0_WW4BEG[1]
  PIN Tile_X0Y0_WW4BEG[2]
    DIRECTION OUTPUT ;
    USE SIGNAL ;
    ANTENNADIFFAREA 0.708600 ;
    PORT
      LAYER Metal3 ;
        RECT 0.000 252.640 0.400 253.040 ;
    END
  END Tile_X0Y0_WW4BEG[2]
  PIN Tile_X0Y0_WW4BEG[3]
    DIRECTION OUTPUT ;
    USE SIGNAL ;
    ANTENNADIFFAREA 0.708600 ;
    PORT
      LAYER Metal3 ;
        RECT 0.000 254.320 0.400 254.720 ;
    END
  END Tile_X0Y0_WW4BEG[3]
  PIN Tile_X0Y0_WW4BEG[4]
    DIRECTION OUTPUT ;
    USE SIGNAL ;
    ANTENNADIFFAREA 0.708600 ;
    PORT
      LAYER Metal3 ;
        RECT 0.000 256.000 0.400 256.400 ;
    END
  END Tile_X0Y0_WW4BEG[4]
  PIN Tile_X0Y0_WW4BEG[5]
    DIRECTION OUTPUT ;
    USE SIGNAL ;
    ANTENNADIFFAREA 0.708600 ;
    PORT
      LAYER Metal3 ;
        RECT 0.000 257.680 0.400 258.080 ;
    END
  END Tile_X0Y0_WW4BEG[5]
  PIN Tile_X0Y0_WW4BEG[6]
    DIRECTION OUTPUT ;
    USE SIGNAL ;
    ANTENNADIFFAREA 0.708600 ;
    PORT
      LAYER Metal3 ;
        RECT 0.000 259.360 0.400 259.760 ;
    END
  END Tile_X0Y0_WW4BEG[6]
  PIN Tile_X0Y0_WW4BEG[7]
    DIRECTION OUTPUT ;
    USE SIGNAL ;
    ANTENNADIFFAREA 0.708600 ;
    PORT
      LAYER Metal3 ;
        RECT 0.000 261.040 0.400 261.440 ;
    END
  END Tile_X0Y0_WW4BEG[7]
  PIN Tile_X0Y0_WW4BEG[8]
    DIRECTION OUTPUT ;
    USE SIGNAL ;
    ANTENNADIFFAREA 0.708600 ;
    PORT
      LAYER Metal3 ;
        RECT 0.000 262.720 0.400 263.120 ;
    END
  END Tile_X0Y0_WW4BEG[8]
  PIN Tile_X0Y0_WW4BEG[9]
    DIRECTION OUTPUT ;
    USE SIGNAL ;
    ANTENNADIFFAREA 0.708600 ;
    PORT
      LAYER Metal3 ;
        RECT 0.000 264.400 0.400 264.800 ;
    END
  END Tile_X0Y0_WW4BEG[9]
  PIN Tile_X0Y1_E1END[0]
    DIRECTION INPUT ;
    USE SIGNAL ;
    ANTENNAGATEAREA 1.518400 ;
    PORT
      LAYER Metal3 ;
        RECT 0.000 80.860 0.400 81.260 ;
    END
  END Tile_X0Y1_E1END[0]
  PIN Tile_X0Y1_E1END[1]
    DIRECTION INPUT ;
    USE SIGNAL ;
    ANTENNAGATEAREA 1.518400 ;
    PORT
      LAYER Metal3 ;
        RECT 0.000 82.540 0.400 82.940 ;
    END
  END Tile_X0Y1_E1END[1]
  PIN Tile_X0Y1_E1END[2]
    DIRECTION INPUT ;
    USE SIGNAL ;
    ANTENNAGATEAREA 1.518400 ;
    PORT
      LAYER Metal3 ;
        RECT 0.000 84.220 0.400 84.620 ;
    END
  END Tile_X0Y1_E1END[2]
  PIN Tile_X0Y1_E1END[3]
    DIRECTION INPUT ;
    USE SIGNAL ;
    ANTENNAGATEAREA 1.518400 ;
    PORT
      LAYER Metal3 ;
        RECT 0.000 85.900 0.400 86.300 ;
    END
  END Tile_X0Y1_E1END[3]
  PIN Tile_X0Y1_E2END[0]
    DIRECTION INPUT ;
    USE SIGNAL ;
    ANTENNAGATEAREA 0.668200 ;
    PORT
      LAYER Metal3 ;
        RECT 0.000 101.020 0.400 101.420 ;
    END
  END Tile_X0Y1_E2END[0]
  PIN Tile_X0Y1_E2END[1]
    DIRECTION INPUT ;
    USE SIGNAL ;
    ANTENNAGATEAREA 1.336400 ;
    PORT
      LAYER Metal3 ;
        RECT 0.000 102.700 0.400 103.100 ;
    END
  END Tile_X0Y1_E2END[1]
  PIN Tile_X0Y1_E2END[2]
    DIRECTION INPUT ;
    USE SIGNAL ;
    ANTENNAGATEAREA 1.336400 ;
    PORT
      LAYER Metal3 ;
        RECT 0.000 104.380 0.400 104.780 ;
    END
  END Tile_X0Y1_E2END[2]
  PIN Tile_X0Y1_E2END[3]
    DIRECTION INPUT ;
    USE SIGNAL ;
    ANTENNAGATEAREA 1.438600 ;
    PORT
      LAYER Metal3 ;
        RECT 0.000 106.060 0.400 106.460 ;
    END
  END Tile_X0Y1_E2END[3]
  PIN Tile_X0Y1_E2END[4]
    DIRECTION INPUT ;
    USE SIGNAL ;
    ANTENNAGATEAREA 1.357200 ;
    PORT
      LAYER Metal3 ;
        RECT 0.000 107.740 0.400 108.140 ;
    END
  END Tile_X0Y1_E2END[4]
  PIN Tile_X0Y1_E2END[5]
    DIRECTION INPUT ;
    USE SIGNAL ;
    ANTENNAGATEAREA 1.151800 ;
    PORT
      LAYER Metal3 ;
        RECT 0.000 109.420 0.400 109.820 ;
    END
  END Tile_X0Y1_E2END[5]
  PIN Tile_X0Y1_E2END[6]
    DIRECTION INPUT ;
    USE SIGNAL ;
    ANTENNAGATEAREA 0.426400 ;
    PORT
      LAYER Metal3 ;
        RECT 0.000 111.100 0.400 111.500 ;
    END
  END Tile_X0Y1_E2END[6]
  PIN Tile_X0Y1_E2END[7]
    DIRECTION INPUT ;
    USE SIGNAL ;
    ANTENNAGATEAREA 0.426400 ;
    PORT
      LAYER Metal3 ;
        RECT 0.000 112.780 0.400 113.180 ;
    END
  END Tile_X0Y1_E2END[7]
  PIN Tile_X0Y1_E2MID[0]
    DIRECTION INPUT ;
    USE SIGNAL ;
    ANTENNAGATEAREA 1.225900 ;
    PORT
      LAYER Metal3 ;
        RECT 0.000 87.580 0.400 87.980 ;
    END
  END Tile_X0Y1_E2MID[0]
  PIN Tile_X0Y1_E2MID[1]
    DIRECTION INPUT ;
    USE SIGNAL ;
    ANTENNAGATEAREA 0.607100 ;
    PORT
      LAYER Metal3 ;
        RECT 0.000 89.260 0.400 89.660 ;
    END
  END Tile_X0Y1_E2MID[1]
  PIN Tile_X0Y1_E2MID[2]
    DIRECTION INPUT ;
    USE SIGNAL ;
    ANTENNAGATEAREA 0.607100 ;
    PORT
      LAYER Metal3 ;
        RECT 0.000 90.940 0.400 91.340 ;
    END
  END Tile_X0Y1_E2MID[2]
  PIN Tile_X0Y1_E2MID[3]
    DIRECTION INPUT ;
    USE SIGNAL ;
    ANTENNAGATEAREA 1.123200 ;
    PORT
      LAYER Metal3 ;
        RECT 0.000 92.620 0.400 93.020 ;
    END
  END Tile_X0Y1_E2MID[3]
  PIN Tile_X0Y1_E2MID[4]
    DIRECTION INPUT ;
    USE SIGNAL ;
    ANTENNAGATEAREA 0.607100 ;
    PORT
      LAYER Metal3 ;
        RECT 0.000 94.300 0.400 94.700 ;
    END
  END Tile_X0Y1_E2MID[4]
  PIN Tile_X0Y1_E2MID[5]
    DIRECTION INPUT ;
    USE SIGNAL ;
    ANTENNAGATEAREA 0.426400 ;
    PORT
      LAYER Metal3 ;
        RECT 0.000 95.980 0.400 96.380 ;
    END
  END Tile_X0Y1_E2MID[5]
  PIN Tile_X0Y1_E2MID[6]
    DIRECTION INPUT ;
    USE SIGNAL ;
    ANTENNAGATEAREA 1.123200 ;
    PORT
      LAYER Metal3 ;
        RECT 0.000 97.660 0.400 98.060 ;
    END
  END Tile_X0Y1_E2MID[6]
  PIN Tile_X0Y1_E2MID[7]
    DIRECTION INPUT ;
    USE SIGNAL ;
    ANTENNAGATEAREA 0.426400 ;
    PORT
      LAYER Metal3 ;
        RECT 0.000 99.340 0.400 99.740 ;
    END
  END Tile_X0Y1_E2MID[7]
  PIN Tile_X0Y1_E6END[0]
    DIRECTION INPUT ;
    USE SIGNAL ;
    ANTENNAGATEAREA 0.881400 ;
    PORT
      LAYER Metal3 ;
        RECT 0.000 141.340 0.400 141.740 ;
    END
  END Tile_X0Y1_E6END[0]
  PIN Tile_X0Y1_E6END[10]
    DIRECTION INPUT ;
    USE SIGNAL ;
    ANTENNAGATEAREA 1.131800 ;
    PORT
      LAYER Metal3 ;
        RECT 0.000 158.140 0.400 158.540 ;
    END
  END Tile_X0Y1_E6END[10]
  PIN Tile_X0Y1_E6END[11]
    DIRECTION INPUT ;
    USE SIGNAL ;
    ANTENNAGATEAREA 1.131800 ;
    PORT
      LAYER Metal3 ;
        RECT 0.000 159.820 0.400 160.220 ;
    END
  END Tile_X0Y1_E6END[11]
  PIN Tile_X0Y1_E6END[1]
    DIRECTION INPUT ;
    USE SIGNAL ;
    ANTENNAGATEAREA 0.881400 ;
    PORT
      LAYER Metal3 ;
        RECT 0.000 143.020 0.400 143.420 ;
    END
  END Tile_X0Y1_E6END[1]
  PIN Tile_X0Y1_E6END[2]
    DIRECTION INPUT ;
    USE SIGNAL ;
    ANTENNAGATEAREA 0.881400 ;
    PORT
      LAYER Metal3 ;
        RECT 0.000 144.700 0.400 145.100 ;
    END
  END Tile_X0Y1_E6END[2]
  PIN Tile_X0Y1_E6END[3]
    DIRECTION INPUT ;
    USE SIGNAL ;
    ANTENNAGATEAREA 0.881400 ;
    PORT
      LAYER Metal3 ;
        RECT 0.000 146.380 0.400 146.780 ;
    END
  END Tile_X0Y1_E6END[3]
  PIN Tile_X0Y1_E6END[4]
    DIRECTION INPUT ;
    USE SIGNAL ;
    ANTENNAGATEAREA 1.131800 ;
    PORT
      LAYER Metal3 ;
        RECT 0.000 148.060 0.400 148.460 ;
    END
  END Tile_X0Y1_E6END[4]
  PIN Tile_X0Y1_E6END[5]
    DIRECTION INPUT ;
    USE SIGNAL ;
    ANTENNAGATEAREA 1.131800 ;
    PORT
      LAYER Metal3 ;
        RECT 0.000 149.740 0.400 150.140 ;
    END
  END Tile_X0Y1_E6END[5]
  PIN Tile_X0Y1_E6END[6]
    DIRECTION INPUT ;
    USE SIGNAL ;
    ANTENNAGATEAREA 1.131800 ;
    PORT
      LAYER Metal3 ;
        RECT 0.000 151.420 0.400 151.820 ;
    END
  END Tile_X0Y1_E6END[6]
  PIN Tile_X0Y1_E6END[7]
    DIRECTION INPUT ;
    USE SIGNAL ;
    ANTENNAGATEAREA 1.131800 ;
    PORT
      LAYER Metal3 ;
        RECT 0.000 153.100 0.400 153.500 ;
    END
  END Tile_X0Y1_E6END[7]
  PIN Tile_X0Y1_E6END[8]
    DIRECTION INPUT ;
    USE SIGNAL ;
    ANTENNAGATEAREA 1.131800 ;
    PORT
      LAYER Metal3 ;
        RECT 0.000 154.780 0.400 155.180 ;
    END
  END Tile_X0Y1_E6END[8]
  PIN Tile_X0Y1_E6END[9]
    DIRECTION INPUT ;
    USE SIGNAL ;
    ANTENNAGATEAREA 1.131800 ;
    PORT
      LAYER Metal3 ;
        RECT 0.000 156.460 0.400 156.860 ;
    END
  END Tile_X0Y1_E6END[9]
  PIN Tile_X0Y1_EE4END[0]
    DIRECTION INPUT ;
    USE SIGNAL ;
    ANTENNAGATEAREA 1.079000 ;
    PORT
      LAYER Metal3 ;
        RECT 0.000 114.460 0.400 114.860 ;
    END
  END Tile_X0Y1_EE4END[0]
  PIN Tile_X0Y1_EE4END[10]
    DIRECTION INPUT ;
    USE SIGNAL ;
    ANTENNAGATEAREA 0.852800 ;
    PORT
      LAYER Metal3 ;
        RECT 0.000 131.260 0.400 131.660 ;
    END
  END Tile_X0Y1_EE4END[10]
  PIN Tile_X0Y1_EE4END[11]
    DIRECTION INPUT ;
    USE SIGNAL ;
    ANTENNAGATEAREA 0.852800 ;
    PORT
      LAYER Metal3 ;
        RECT 0.000 132.940 0.400 133.340 ;
    END
  END Tile_X0Y1_EE4END[11]
  PIN Tile_X0Y1_EE4END[12]
    DIRECTION INPUT ;
    USE SIGNAL ;
    ANTENNAGATEAREA 1.079000 ;
    PORT
      LAYER Metal3 ;
        RECT 0.000 134.620 0.400 135.020 ;
    END
  END Tile_X0Y1_EE4END[12]
  PIN Tile_X0Y1_EE4END[13]
    DIRECTION INPUT ;
    USE SIGNAL ;
    ANTENNAGATEAREA 1.079000 ;
    PORT
      LAYER Metal3 ;
        RECT 0.000 136.300 0.400 136.700 ;
    END
  END Tile_X0Y1_EE4END[13]
  PIN Tile_X0Y1_EE4END[14]
    DIRECTION INPUT ;
    USE SIGNAL ;
    ANTENNAGATEAREA 1.079000 ;
    PORT
      LAYER Metal3 ;
        RECT 0.000 137.980 0.400 138.380 ;
    END
  END Tile_X0Y1_EE4END[14]
  PIN Tile_X0Y1_EE4END[15]
    DIRECTION INPUT ;
    USE SIGNAL ;
    ANTENNAGATEAREA 1.079000 ;
    PORT
      LAYER Metal3 ;
        RECT 0.000 139.660 0.400 140.060 ;
    END
  END Tile_X0Y1_EE4END[15]
  PIN Tile_X0Y1_EE4END[1]
    DIRECTION INPUT ;
    USE SIGNAL ;
    ANTENNAGATEAREA 1.079000 ;
    PORT
      LAYER Metal3 ;
        RECT 0.000 116.140 0.400 116.540 ;
    END
  END Tile_X0Y1_EE4END[1]
  PIN Tile_X0Y1_EE4END[2]
    DIRECTION INPUT ;
    USE SIGNAL ;
    ANTENNAGATEAREA 1.079000 ;
    PORT
      LAYER Metal3 ;
        RECT 0.000 117.820 0.400 118.220 ;
    END
  END Tile_X0Y1_EE4END[2]
  PIN Tile_X0Y1_EE4END[3]
    DIRECTION INPUT ;
    USE SIGNAL ;
    ANTENNAGATEAREA 1.079000 ;
    PORT
      LAYER Metal3 ;
        RECT 0.000 119.500 0.400 119.900 ;
    END
  END Tile_X0Y1_EE4END[3]
  PIN Tile_X0Y1_EE4END[4]
    DIRECTION INPUT ;
    USE SIGNAL ;
    ANTENNAGATEAREA 0.852800 ;
    PORT
      LAYER Metal3 ;
        RECT 0.000 121.180 0.400 121.580 ;
    END
  END Tile_X0Y1_EE4END[4]
  PIN Tile_X0Y1_EE4END[5]
    DIRECTION INPUT ;
    USE SIGNAL ;
    ANTENNAGATEAREA 0.852800 ;
    PORT
      LAYER Metal3 ;
        RECT 0.000 122.860 0.400 123.260 ;
    END
  END Tile_X0Y1_EE4END[5]
  PIN Tile_X0Y1_EE4END[6]
    DIRECTION INPUT ;
    USE SIGNAL ;
    ANTENNAGATEAREA 0.852800 ;
    PORT
      LAYER Metal3 ;
        RECT 0.000 124.540 0.400 124.940 ;
    END
  END Tile_X0Y1_EE4END[6]
  PIN Tile_X0Y1_EE4END[7]
    DIRECTION INPUT ;
    USE SIGNAL ;
    ANTENNAGATEAREA 0.852800 ;
    PORT
      LAYER Metal3 ;
        RECT 0.000 126.220 0.400 126.620 ;
    END
  END Tile_X0Y1_EE4END[7]
  PIN Tile_X0Y1_EE4END[8]
    DIRECTION INPUT ;
    USE SIGNAL ;
    ANTENNAGATEAREA 0.852800 ;
    PORT
      LAYER Metal3 ;
        RECT 0.000 127.900 0.400 128.300 ;
    END
  END Tile_X0Y1_EE4END[8]
  PIN Tile_X0Y1_EE4END[9]
    DIRECTION INPUT ;
    USE SIGNAL ;
    ANTENNAGATEAREA 0.852800 ;
    PORT
      LAYER Metal3 ;
        RECT 0.000 129.580 0.400 129.980 ;
    END
  END Tile_X0Y1_EE4END[9]
  PIN Tile_X0Y1_FrameData[0]
    DIRECTION INPUT ;
    USE SIGNAL ;
    ANTENNAGATEAREA 1.807000 ;
    PORT
      LAYER Metal3 ;
        RECT 0.000 161.500 0.400 161.900 ;
    END
  END Tile_X0Y1_FrameData[0]
  PIN Tile_X0Y1_FrameData[10]
    DIRECTION INPUT ;
    USE SIGNAL ;
    ANTENNAGATEAREA 1.987700 ;
    PORT
      LAYER Metal3 ;
        RECT 0.000 178.300 0.400 178.700 ;
    END
  END Tile_X0Y1_FrameData[10]
  PIN Tile_X0Y1_FrameData[11]
    DIRECTION INPUT ;
    USE SIGNAL ;
    ANTENNAGATEAREA 1.987700 ;
    PORT
      LAYER Metal3 ;
        RECT 0.000 179.980 0.400 180.380 ;
    END
  END Tile_X0Y1_FrameData[11]
  PIN Tile_X0Y1_FrameData[12]
    DIRECTION INPUT ;
    USE SIGNAL ;
    ANTENNAGATEAREA 1.987700 ;
    PORT
      LAYER Metal3 ;
        RECT 0.000 181.660 0.400 182.060 ;
    END
  END Tile_X0Y1_FrameData[12]
  PIN Tile_X0Y1_FrameData[13]
    DIRECTION INPUT ;
    USE SIGNAL ;
    ANTENNAGATEAREA 1.987700 ;
    PORT
      LAYER Metal3 ;
        RECT 0.000 183.340 0.400 183.740 ;
    END
  END Tile_X0Y1_FrameData[13]
  PIN Tile_X0Y1_FrameData[14]
    DIRECTION INPUT ;
    USE SIGNAL ;
    ANTENNAGATEAREA 1.987700 ;
    PORT
      LAYER Metal3 ;
        RECT 0.000 185.020 0.400 185.420 ;
    END
  END Tile_X0Y1_FrameData[14]
  PIN Tile_X0Y1_FrameData[15]
    DIRECTION INPUT ;
    USE SIGNAL ;
    ANTENNAGATEAREA 1.987700 ;
    PORT
      LAYER Metal3 ;
        RECT 0.000 186.700 0.400 187.100 ;
    END
  END Tile_X0Y1_FrameData[15]
  PIN Tile_X0Y1_FrameData[16]
    DIRECTION INPUT ;
    USE SIGNAL ;
    ANTENNAGATEAREA 1.987700 ;
    PORT
      LAYER Metal3 ;
        RECT 0.000 188.380 0.400 188.780 ;
    END
  END Tile_X0Y1_FrameData[16]
  PIN Tile_X0Y1_FrameData[17]
    DIRECTION INPUT ;
    USE SIGNAL ;
    ANTENNAGATEAREA 1.987700 ;
    PORT
      LAYER Metal3 ;
        RECT 0.000 190.060 0.400 190.460 ;
    END
  END Tile_X0Y1_FrameData[17]
  PIN Tile_X0Y1_FrameData[18]
    DIRECTION INPUT ;
    USE SIGNAL ;
    ANTENNAGATEAREA 1.987700 ;
    PORT
      LAYER Metal3 ;
        RECT 0.000 191.740 0.400 192.140 ;
    END
  END Tile_X0Y1_FrameData[18]
  PIN Tile_X0Y1_FrameData[19]
    DIRECTION INPUT ;
    USE SIGNAL ;
    ANTENNAGATEAREA 1.987700 ;
    PORT
      LAYER Metal3 ;
        RECT 0.000 193.420 0.400 193.820 ;
    END
  END Tile_X0Y1_FrameData[19]
  PIN Tile_X0Y1_FrameData[1]
    DIRECTION INPUT ;
    USE SIGNAL ;
    ANTENNAGATEAREA 1.807000 ;
    PORT
      LAYER Metal3 ;
        RECT 0.000 163.180 0.400 163.580 ;
    END
  END Tile_X0Y1_FrameData[1]
  PIN Tile_X0Y1_FrameData[20]
    DIRECTION INPUT ;
    USE SIGNAL ;
    ANTENNAGATEAREA 1.987700 ;
    PORT
      LAYER Metal3 ;
        RECT 0.000 195.100 0.400 195.500 ;
    END
  END Tile_X0Y1_FrameData[20]
  PIN Tile_X0Y1_FrameData[21]
    DIRECTION INPUT ;
    USE SIGNAL ;
    ANTENNAGATEAREA 1.987700 ;
    PORT
      LAYER Metal3 ;
        RECT 0.000 196.780 0.400 197.180 ;
    END
  END Tile_X0Y1_FrameData[21]
  PIN Tile_X0Y1_FrameData[22]
    DIRECTION INPUT ;
    USE SIGNAL ;
    ANTENNAGATEAREA 1.987700 ;
    PORT
      LAYER Metal3 ;
        RECT 0.000 198.460 0.400 198.860 ;
    END
  END Tile_X0Y1_FrameData[22]
  PIN Tile_X0Y1_FrameData[23]
    DIRECTION INPUT ;
    USE SIGNAL ;
    ANTENNAGATEAREA 1.987700 ;
    PORT
      LAYER Metal3 ;
        RECT 0.000 200.140 0.400 200.540 ;
    END
  END Tile_X0Y1_FrameData[23]
  PIN Tile_X0Y1_FrameData[24]
    DIRECTION INPUT ;
    USE SIGNAL ;
    ANTENNAGATEAREA 1.987700 ;
    PORT
      LAYER Metal3 ;
        RECT 0.000 201.820 0.400 202.220 ;
    END
  END Tile_X0Y1_FrameData[24]
  PIN Tile_X0Y1_FrameData[25]
    DIRECTION INPUT ;
    USE SIGNAL ;
    ANTENNAGATEAREA 1.987700 ;
    PORT
      LAYER Metal3 ;
        RECT 0.000 203.500 0.400 203.900 ;
    END
  END Tile_X0Y1_FrameData[25]
  PIN Tile_X0Y1_FrameData[26]
    DIRECTION INPUT ;
    USE SIGNAL ;
    ANTENNAGATEAREA 1.987700 ;
    PORT
      LAYER Metal3 ;
        RECT 0.000 205.180 0.400 205.580 ;
    END
  END Tile_X0Y1_FrameData[26]
  PIN Tile_X0Y1_FrameData[27]
    DIRECTION INPUT ;
    USE SIGNAL ;
    ANTENNAGATEAREA 1.987700 ;
    PORT
      LAYER Metal3 ;
        RECT 0.000 206.860 0.400 207.260 ;
    END
  END Tile_X0Y1_FrameData[27]
  PIN Tile_X0Y1_FrameData[28]
    DIRECTION INPUT ;
    USE SIGNAL ;
    ANTENNAGATEAREA 1.987700 ;
    PORT
      LAYER Metal3 ;
        RECT 0.000 208.540 0.400 208.940 ;
    END
  END Tile_X0Y1_FrameData[28]
  PIN Tile_X0Y1_FrameData[29]
    DIRECTION INPUT ;
    USE SIGNAL ;
    ANTENNAGATEAREA 1.987700 ;
    PORT
      LAYER Metal3 ;
        RECT 0.000 210.220 0.400 210.620 ;
    END
  END Tile_X0Y1_FrameData[29]
  PIN Tile_X0Y1_FrameData[2]
    DIRECTION INPUT ;
    USE SIGNAL ;
    ANTENNAGATEAREA 1.807000 ;
    PORT
      LAYER Metal3 ;
        RECT 0.000 164.860 0.400 165.260 ;
    END
  END Tile_X0Y1_FrameData[2]
  PIN Tile_X0Y1_FrameData[30]
    DIRECTION INPUT ;
    USE SIGNAL ;
    ANTENNAGATEAREA 1.987700 ;
    PORT
      LAYER Metal3 ;
        RECT 0.000 211.900 0.400 212.300 ;
    END
  END Tile_X0Y1_FrameData[30]
  PIN Tile_X0Y1_FrameData[31]
    DIRECTION INPUT ;
    USE SIGNAL ;
    ANTENNAGATEAREA 1.987700 ;
    PORT
      LAYER Metal3 ;
        RECT 0.000 213.580 0.400 213.980 ;
    END
  END Tile_X0Y1_FrameData[31]
  PIN Tile_X0Y1_FrameData[3]
    DIRECTION INPUT ;
    USE SIGNAL ;
    ANTENNAGATEAREA 1.807000 ;
    PORT
      LAYER Metal3 ;
        RECT 0.000 166.540 0.400 166.940 ;
    END
  END Tile_X0Y1_FrameData[3]
  PIN Tile_X0Y1_FrameData[4]
    DIRECTION INPUT ;
    USE SIGNAL ;
    ANTENNAGATEAREA 1.807000 ;
    PORT
      LAYER Metal3 ;
        RECT 0.000 168.220 0.400 168.620 ;
    END
  END Tile_X0Y1_FrameData[4]
  PIN Tile_X0Y1_FrameData[5]
    DIRECTION INPUT ;
    USE SIGNAL ;
    ANTENNAGATEAREA 1.807000 ;
    PORT
      LAYER Metal3 ;
        RECT 0.000 169.900 0.400 170.300 ;
    END
  END Tile_X0Y1_FrameData[5]
  PIN Tile_X0Y1_FrameData[6]
    DIRECTION INPUT ;
    USE SIGNAL ;
    ANTENNAGATEAREA 1.807000 ;
    PORT
      LAYER Metal3 ;
        RECT 0.000 171.580 0.400 171.980 ;
    END
  END Tile_X0Y1_FrameData[6]
  PIN Tile_X0Y1_FrameData[7]
    DIRECTION INPUT ;
    USE SIGNAL ;
    ANTENNAGATEAREA 1.807000 ;
    PORT
      LAYER Metal3 ;
        RECT 0.000 173.260 0.400 173.660 ;
    END
  END Tile_X0Y1_FrameData[7]
  PIN Tile_X0Y1_FrameData[8]
    DIRECTION INPUT ;
    USE SIGNAL ;
    ANTENNAGATEAREA 1.807000 ;
    PORT
      LAYER Metal3 ;
        RECT 0.000 174.940 0.400 175.340 ;
    END
  END Tile_X0Y1_FrameData[8]
  PIN Tile_X0Y1_FrameData[9]
    DIRECTION INPUT ;
    USE SIGNAL ;
    ANTENNAGATEAREA 1.807000 ;
    PORT
      LAYER Metal3 ;
        RECT 0.000 176.620 0.400 177.020 ;
    END
  END Tile_X0Y1_FrameData[9]
  PIN Tile_X0Y1_FrameData_O[0]
    DIRECTION OUTPUT ;
    USE SIGNAL ;
    ANTENNADIFFAREA 0.708600 ;
    PORT
      LAYER Metal3 ;
        RECT 109.040 149.740 109.440 150.140 ;
    END
  END Tile_X0Y1_FrameData_O[0]
  PIN Tile_X0Y1_FrameData_O[10]
    DIRECTION OUTPUT ;
    USE SIGNAL ;
    ANTENNADIFFAREA 0.708600 ;
    PORT
      LAYER Metal3 ;
        RECT 109.040 191.740 109.440 192.140 ;
    END
  END Tile_X0Y1_FrameData_O[10]
  PIN Tile_X0Y1_FrameData_O[11]
    DIRECTION OUTPUT ;
    USE SIGNAL ;
    ANTENNADIFFAREA 0.708600 ;
    PORT
      LAYER Metal3 ;
        RECT 109.040 195.940 109.440 196.340 ;
    END
  END Tile_X0Y1_FrameData_O[11]
  PIN Tile_X0Y1_FrameData_O[12]
    DIRECTION OUTPUT ;
    USE SIGNAL ;
    ANTENNADIFFAREA 0.708600 ;
    PORT
      LAYER Metal3 ;
        RECT 109.040 200.140 109.440 200.540 ;
    END
  END Tile_X0Y1_FrameData_O[12]
  PIN Tile_X0Y1_FrameData_O[13]
    DIRECTION OUTPUT ;
    USE SIGNAL ;
    ANTENNADIFFAREA 0.708600 ;
    PORT
      LAYER Metal3 ;
        RECT 109.040 204.340 109.440 204.740 ;
    END
  END Tile_X0Y1_FrameData_O[13]
  PIN Tile_X0Y1_FrameData_O[14]
    DIRECTION OUTPUT ;
    USE SIGNAL ;
    ANTENNADIFFAREA 0.708600 ;
    PORT
      LAYER Metal3 ;
        RECT 109.040 208.540 109.440 208.940 ;
    END
  END Tile_X0Y1_FrameData_O[14]
  PIN Tile_X0Y1_FrameData_O[15]
    DIRECTION OUTPUT ;
    USE SIGNAL ;
    ANTENNADIFFAREA 0.708600 ;
    PORT
      LAYER Metal3 ;
        RECT 109.040 212.740 109.440 213.140 ;
    END
  END Tile_X0Y1_FrameData_O[15]
  PIN Tile_X0Y1_FrameData_O[16]
    DIRECTION OUTPUT ;
    USE SIGNAL ;
    ANTENNADIFFAREA 0.708600 ;
    PORT
      LAYER Metal3 ;
        RECT 109.040 216.940 109.440 217.340 ;
    END
  END Tile_X0Y1_FrameData_O[16]
  PIN Tile_X0Y1_FrameData_O[17]
    DIRECTION OUTPUT ;
    USE SIGNAL ;
    ANTENNADIFFAREA 0.708600 ;
    PORT
      LAYER Metal3 ;
        RECT 109.040 221.140 109.440 221.540 ;
    END
  END Tile_X0Y1_FrameData_O[17]
  PIN Tile_X0Y1_FrameData_O[18]
    DIRECTION OUTPUT ;
    USE SIGNAL ;
    ANTENNADIFFAREA 0.708600 ;
    PORT
      LAYER Metal3 ;
        RECT 109.040 225.340 109.440 225.740 ;
    END
  END Tile_X0Y1_FrameData_O[18]
  PIN Tile_X0Y1_FrameData_O[19]
    DIRECTION OUTPUT ;
    USE SIGNAL ;
    ANTENNADIFFAREA 0.708600 ;
    PORT
      LAYER Metal3 ;
        RECT 109.040 229.540 109.440 229.940 ;
    END
  END Tile_X0Y1_FrameData_O[19]
  PIN Tile_X0Y1_FrameData_O[1]
    DIRECTION OUTPUT ;
    USE SIGNAL ;
    ANTENNADIFFAREA 0.708600 ;
    PORT
      LAYER Metal3 ;
        RECT 109.040 153.940 109.440 154.340 ;
    END
  END Tile_X0Y1_FrameData_O[1]
  PIN Tile_X0Y1_FrameData_O[20]
    DIRECTION OUTPUT ;
    USE SIGNAL ;
    ANTENNADIFFAREA 0.708600 ;
    PORT
      LAYER Metal3 ;
        RECT 109.040 233.740 109.440 234.140 ;
    END
  END Tile_X0Y1_FrameData_O[20]
  PIN Tile_X0Y1_FrameData_O[21]
    DIRECTION OUTPUT ;
    USE SIGNAL ;
    ANTENNADIFFAREA 0.708600 ;
    PORT
      LAYER Metal3 ;
        RECT 109.040 237.940 109.440 238.340 ;
    END
  END Tile_X0Y1_FrameData_O[21]
  PIN Tile_X0Y1_FrameData_O[22]
    DIRECTION OUTPUT ;
    USE SIGNAL ;
    ANTENNADIFFAREA 0.708600 ;
    PORT
      LAYER Metal3 ;
        RECT 109.040 242.140 109.440 242.540 ;
    END
  END Tile_X0Y1_FrameData_O[22]
  PIN Tile_X0Y1_FrameData_O[23]
    DIRECTION OUTPUT ;
    USE SIGNAL ;
    ANTENNADIFFAREA 0.708600 ;
    PORT
      LAYER Metal3 ;
        RECT 109.040 246.340 109.440 246.740 ;
    END
  END Tile_X0Y1_FrameData_O[23]
  PIN Tile_X0Y1_FrameData_O[24]
    DIRECTION OUTPUT ;
    USE SIGNAL ;
    ANTENNADIFFAREA 0.708600 ;
    PORT
      LAYER Metal3 ;
        RECT 109.040 250.540 109.440 250.940 ;
    END
  END Tile_X0Y1_FrameData_O[24]
  PIN Tile_X0Y1_FrameData_O[25]
    DIRECTION OUTPUT ;
    USE SIGNAL ;
    ANTENNADIFFAREA 0.708600 ;
    PORT
      LAYER Metal3 ;
        RECT 109.040 254.740 109.440 255.140 ;
    END
  END Tile_X0Y1_FrameData_O[25]
  PIN Tile_X0Y1_FrameData_O[26]
    DIRECTION OUTPUT ;
    USE SIGNAL ;
    ANTENNADIFFAREA 0.708600 ;
    PORT
      LAYER Metal3 ;
        RECT 109.040 258.940 109.440 259.340 ;
    END
  END Tile_X0Y1_FrameData_O[26]
  PIN Tile_X0Y1_FrameData_O[27]
    DIRECTION OUTPUT ;
    USE SIGNAL ;
    ANTENNADIFFAREA 0.708600 ;
    PORT
      LAYER Metal3 ;
        RECT 109.040 263.140 109.440 263.540 ;
    END
  END Tile_X0Y1_FrameData_O[27]
  PIN Tile_X0Y1_FrameData_O[28]
    DIRECTION OUTPUT ;
    USE SIGNAL ;
    ANTENNADIFFAREA 0.708600 ;
    PORT
      LAYER Metal3 ;
        RECT 109.040 267.340 109.440 267.740 ;
    END
  END Tile_X0Y1_FrameData_O[28]
  PIN Tile_X0Y1_FrameData_O[29]
    DIRECTION OUTPUT ;
    USE SIGNAL ;
    ANTENNADIFFAREA 0.708600 ;
    PORT
      LAYER Metal3 ;
        RECT 109.040 271.540 109.440 271.940 ;
    END
  END Tile_X0Y1_FrameData_O[29]
  PIN Tile_X0Y1_FrameData_O[2]
    DIRECTION OUTPUT ;
    USE SIGNAL ;
    ANTENNADIFFAREA 0.708600 ;
    PORT
      LAYER Metal3 ;
        RECT 109.040 158.140 109.440 158.540 ;
    END
  END Tile_X0Y1_FrameData_O[2]
  PIN Tile_X0Y1_FrameData_O[30]
    DIRECTION OUTPUT ;
    USE SIGNAL ;
    ANTENNADIFFAREA 0.708600 ;
    PORT
      LAYER Metal3 ;
        RECT 109.040 275.740 109.440 276.140 ;
    END
  END Tile_X0Y1_FrameData_O[30]
  PIN Tile_X0Y1_FrameData_O[31]
    DIRECTION OUTPUT ;
    USE SIGNAL ;
    ANTENNADIFFAREA 0.708600 ;
    PORT
      LAYER Metal3 ;
        RECT 109.040 279.940 109.440 280.340 ;
    END
  END Tile_X0Y1_FrameData_O[31]
  PIN Tile_X0Y1_FrameData_O[3]
    DIRECTION OUTPUT ;
    USE SIGNAL ;
    ANTENNADIFFAREA 0.708600 ;
    PORT
      LAYER Metal3 ;
        RECT 109.040 162.340 109.440 162.740 ;
    END
  END Tile_X0Y1_FrameData_O[3]
  PIN Tile_X0Y1_FrameData_O[4]
    DIRECTION OUTPUT ;
    USE SIGNAL ;
    ANTENNADIFFAREA 0.708600 ;
    PORT
      LAYER Metal3 ;
        RECT 109.040 166.540 109.440 166.940 ;
    END
  END Tile_X0Y1_FrameData_O[4]
  PIN Tile_X0Y1_FrameData_O[5]
    DIRECTION OUTPUT ;
    USE SIGNAL ;
    ANTENNADIFFAREA 0.708600 ;
    PORT
      LAYER Metal3 ;
        RECT 109.040 170.740 109.440 171.140 ;
    END
  END Tile_X0Y1_FrameData_O[5]
  PIN Tile_X0Y1_FrameData_O[6]
    DIRECTION OUTPUT ;
    USE SIGNAL ;
    ANTENNADIFFAREA 0.708600 ;
    PORT
      LAYER Metal3 ;
        RECT 109.040 174.940 109.440 175.340 ;
    END
  END Tile_X0Y1_FrameData_O[6]
  PIN Tile_X0Y1_FrameData_O[7]
    DIRECTION OUTPUT ;
    USE SIGNAL ;
    ANTENNADIFFAREA 0.708600 ;
    PORT
      LAYER Metal3 ;
        RECT 109.040 179.140 109.440 179.540 ;
    END
  END Tile_X0Y1_FrameData_O[7]
  PIN Tile_X0Y1_FrameData_O[8]
    DIRECTION OUTPUT ;
    USE SIGNAL ;
    ANTENNADIFFAREA 0.708600 ;
    PORT
      LAYER Metal3 ;
        RECT 109.040 183.340 109.440 183.740 ;
    END
  END Tile_X0Y1_FrameData_O[8]
  PIN Tile_X0Y1_FrameData_O[9]
    DIRECTION OUTPUT ;
    USE SIGNAL ;
    ANTENNADIFFAREA 0.708600 ;
    PORT
      LAYER Metal3 ;
        RECT 109.040 187.540 109.440 187.940 ;
    END
  END Tile_X0Y1_FrameData_O[9]
  PIN Tile_X0Y1_FrameStrobe[0]
    DIRECTION INPUT ;
    USE SIGNAL ;
    ANTENNAGATEAREA 13.326300 ;
    PORT
      LAYER Metal2 ;
        RECT 79.960 0.000 80.360 0.400 ;
    END
  END Tile_X0Y1_FrameStrobe[0]
  PIN Tile_X0Y1_FrameStrobe[10]
    DIRECTION INPUT ;
    USE SIGNAL ;
    ANTENNAGATEAREA 0.789100 ;
    ANTENNADIFFAREA 2.015400 ;
    PORT
      LAYER Metal2 ;
        RECT 89.560 0.000 89.960 0.400 ;
    END
  END Tile_X0Y1_FrameStrobe[10]
  PIN Tile_X0Y1_FrameStrobe[11]
    DIRECTION INPUT ;
    USE SIGNAL ;
    ANTENNAGATEAREA 0.789100 ;
    ANTENNADIFFAREA 2.015400 ;
    PORT
      LAYER Metal2 ;
        RECT 90.520 0.000 90.920 0.400 ;
    END
  END Tile_X0Y1_FrameStrobe[11]
  PIN Tile_X0Y1_FrameStrobe[12]
    DIRECTION INPUT ;
    USE SIGNAL ;
    ANTENNAGATEAREA 0.180700 ;
    PORT
      LAYER Metal2 ;
        RECT 91.480 0.000 91.880 0.400 ;
    END
  END Tile_X0Y1_FrameStrobe[12]
  PIN Tile_X0Y1_FrameStrobe[13]
    DIRECTION INPUT ;
    USE SIGNAL ;
    ANTENNAGATEAREA 0.789100 ;
    ANTENNADIFFAREA 2.015400 ;
    PORT
      LAYER Metal2 ;
        RECT 92.440 0.000 92.840 0.400 ;
    END
  END Tile_X0Y1_FrameStrobe[13]
  PIN Tile_X0Y1_FrameStrobe[14]
    DIRECTION INPUT ;
    USE SIGNAL ;
    ANTENNAGATEAREA 0.789100 ;
    ANTENNADIFFAREA 2.015400 ;
    PORT
      LAYER Metal2 ;
        RECT 93.400 0.000 93.800 0.400 ;
    END
  END Tile_X0Y1_FrameStrobe[14]
  PIN Tile_X0Y1_FrameStrobe[15]
    DIRECTION INPUT ;
    USE SIGNAL ;
    ANTENNAGATEAREA 0.789100 ;
    ANTENNADIFFAREA 2.015400 ;
    PORT
      LAYER Metal2 ;
        RECT 94.360 0.000 94.760 0.400 ;
    END
  END Tile_X0Y1_FrameStrobe[15]
  PIN Tile_X0Y1_FrameStrobe[16]
    DIRECTION INPUT ;
    USE SIGNAL ;
    ANTENNAGATEAREA 2.005900 ;
    ANTENNADIFFAREA 6.046200 ;
    PORT
      LAYER Metal2 ;
        RECT 95.320 0.000 95.720 0.400 ;
    END
  END Tile_X0Y1_FrameStrobe[16]
  PIN Tile_X0Y1_FrameStrobe[17]
    DIRECTION INPUT ;
    USE SIGNAL ;
    ANTENNAGATEAREA 1.397500 ;
    ANTENNADIFFAREA 4.030800 ;
    PORT
      LAYER Metal2 ;
        RECT 96.280 0.000 96.680 0.400 ;
    END
  END Tile_X0Y1_FrameStrobe[17]
  PIN Tile_X0Y1_FrameStrobe[18]
    DIRECTION INPUT ;
    USE SIGNAL ;
    ANTENNAGATEAREA 0.789100 ;
    ANTENNADIFFAREA 2.015400 ;
    PORT
      LAYER Metal2 ;
        RECT 97.240 0.000 97.640 0.400 ;
    END
  END Tile_X0Y1_FrameStrobe[18]
  PIN Tile_X0Y1_FrameStrobe[19]
    DIRECTION INPUT ;
    USE SIGNAL ;
    ANTENNAGATEAREA 0.180700 ;
    PORT
      LAYER Metal2 ;
        RECT 98.200 0.000 98.600 0.400 ;
    END
  END Tile_X0Y1_FrameStrobe[19]
  PIN Tile_X0Y1_FrameStrobe[1]
    DIRECTION INPUT ;
    USE SIGNAL ;
    ANTENNAGATEAREA 13.326300 ;
    PORT
      LAYER Metal2 ;
        RECT 80.920 0.000 81.320 0.400 ;
    END
  END Tile_X0Y1_FrameStrobe[1]
  PIN Tile_X0Y1_FrameStrobe[2]
    DIRECTION INPUT ;
    USE SIGNAL ;
    ANTENNAGATEAREA 13.326300 ;
    PORT
      LAYER Metal2 ;
        RECT 81.880 0.000 82.280 0.400 ;
    END
  END Tile_X0Y1_FrameStrobe[2]
  PIN Tile_X0Y1_FrameStrobe[3]
    DIRECTION INPUT ;
    USE SIGNAL ;
    ANTENNAGATEAREA 13.326300 ;
    PORT
      LAYER Metal2 ;
        RECT 82.840 0.000 83.240 0.400 ;
    END
  END Tile_X0Y1_FrameStrobe[3]
  PIN Tile_X0Y1_FrameStrobe[4]
    DIRECTION INPUT ;
    USE SIGNAL ;
    ANTENNAGATEAREA 13.326300 ;
    PORT
      LAYER Metal2 ;
        RECT 83.800 0.000 84.200 0.400 ;
    END
  END Tile_X0Y1_FrameStrobe[4]
  PIN Tile_X0Y1_FrameStrobe[5]
    DIRECTION INPUT ;
    USE SIGNAL ;
    ANTENNAGATEAREA 13.326300 ;
    PORT
      LAYER Metal2 ;
        RECT 84.760 0.000 85.160 0.400 ;
    END
  END Tile_X0Y1_FrameStrobe[5]
  PIN Tile_X0Y1_FrameStrobe[6]
    DIRECTION INPUT ;
    USE SIGNAL ;
    ANTENNAGATEAREA 13.326300 ;
    PORT
      LAYER Metal2 ;
        RECT 85.720 0.000 86.120 0.400 ;
    END
  END Tile_X0Y1_FrameStrobe[6]
  PIN Tile_X0Y1_FrameStrobe[7]
    DIRECTION INPUT ;
    USE SIGNAL ;
    ANTENNAGATEAREA 13.326300 ;
    PORT
      LAYER Metal2 ;
        RECT 86.680 0.000 87.080 0.400 ;
    END
  END Tile_X0Y1_FrameStrobe[7]
  PIN Tile_X0Y1_FrameStrobe[8]
    DIRECTION INPUT ;
    USE SIGNAL ;
    ANTENNAGATEAREA 13.326300 ;
    PORT
      LAYER Metal2 ;
        RECT 87.640 0.000 88.040 0.400 ;
    END
  END Tile_X0Y1_FrameStrobe[8]
  PIN Tile_X0Y1_FrameStrobe[9]
    DIRECTION INPUT ;
    USE SIGNAL ;
    ANTENNAGATEAREA 6.753500 ;
    PORT
      LAYER Metal2 ;
        RECT 88.600 0.000 89.000 0.400 ;
    END
  END Tile_X0Y1_FrameStrobe[9]
  PIN Tile_X0Y1_N1END[0]
    DIRECTION INPUT ;
    USE SIGNAL ;
    ANTENNAGATEAREA 1.311700 ;
    PORT
      LAYER Metal2 ;
        RECT 9.880 0.000 10.280 0.400 ;
    END
  END Tile_X0Y1_N1END[0]
  PIN Tile_X0Y1_N1END[1]
    DIRECTION INPUT ;
    USE SIGNAL ;
    ANTENNAGATEAREA 1.311700 ;
    PORT
      LAYER Metal2 ;
        RECT 10.840 0.000 11.240 0.400 ;
    END
  END Tile_X0Y1_N1END[1]
  PIN Tile_X0Y1_N1END[2]
    DIRECTION INPUT ;
    USE SIGNAL ;
    ANTENNAGATEAREA 1.311700 ;
    PORT
      LAYER Metal2 ;
        RECT 11.800 0.000 12.200 0.400 ;
    END
  END Tile_X0Y1_N1END[2]
  PIN Tile_X0Y1_N1END[3]
    DIRECTION INPUT ;
    USE SIGNAL ;
    ANTENNAGATEAREA 1.311700 ;
    PORT
      LAYER Metal2 ;
        RECT 12.760 0.000 13.160 0.400 ;
    END
  END Tile_X0Y1_N1END[3]
  PIN Tile_X0Y1_N2END[0]
    DIRECTION INPUT ;
    USE SIGNAL ;
    ANTENNAGATEAREA 0.213200 ;
    PORT
      LAYER Metal2 ;
        RECT 21.400 0.000 21.800 0.400 ;
    END
  END Tile_X0Y1_N2END[0]
  PIN Tile_X0Y1_N2END[1]
    DIRECTION INPUT ;
    USE SIGNAL ;
    ANTENNAGATEAREA 0.821600 ;
    ANTENNADIFFAREA 2.015400 ;
    PORT
      LAYER Metal2 ;
        RECT 22.360 0.000 22.760 0.400 ;
    END
  END Tile_X0Y1_N2END[1]
  PIN Tile_X0Y1_N2END[2]
    DIRECTION INPUT ;
    USE SIGNAL ;
    ANTENNAGATEAREA 0.910000 ;
    PORT
      LAYER Metal2 ;
        RECT 23.320 0.000 23.720 0.400 ;
    END
  END Tile_X0Y1_N2END[2]
  PIN Tile_X0Y1_N2END[3]
    DIRECTION INPUT ;
    USE SIGNAL ;
    ANTENNAGATEAREA 0.881400 ;
    PORT
      LAYER Metal2 ;
        RECT 24.280 0.000 24.680 0.400 ;
    END
  END Tile_X0Y1_N2END[3]
  PIN Tile_X0Y1_N2END[4]
    DIRECTION INPUT ;
    USE SIGNAL ;
    ANTENNAGATEAREA 0.821600 ;
    ANTENNADIFFAREA 2.015400 ;
    PORT
      LAYER Metal2 ;
        RECT 25.240 0.000 25.640 0.400 ;
    END
  END Tile_X0Y1_N2END[4]
  PIN Tile_X0Y1_N2END[5]
    DIRECTION INPUT ;
    USE SIGNAL ;
    ANTENNAGATEAREA 0.213200 ;
    PORT
      LAYER Metal2 ;
        RECT 26.200 0.000 26.600 0.400 ;
    END
  END Tile_X0Y1_N2END[5]
  PIN Tile_X0Y1_N2END[6]
    DIRECTION INPUT ;
    USE SIGNAL ;
    ANTENNAGATEAREA 0.821600 ;
    ANTENNADIFFAREA 2.015400 ;
    PORT
      LAYER Metal2 ;
        RECT 27.160 0.000 27.560 0.400 ;
    END
  END Tile_X0Y1_N2END[6]
  PIN Tile_X0Y1_N2END[7]
    DIRECTION INPUT ;
    USE SIGNAL ;
    ANTENNAGATEAREA 0.213200 ;
    PORT
      LAYER Metal2 ;
        RECT 28.120 0.000 28.520 0.400 ;
    END
  END Tile_X0Y1_N2END[7]
  PIN Tile_X0Y1_N2MID[0]
    DIRECTION INPUT ;
    USE SIGNAL ;
    ANTENNAGATEAREA 2.251600 ;
    ANTENNADIFFAREA 6.046200 ;
    PORT
      LAYER Metal2 ;
        RECT 13.720 0.000 14.120 0.400 ;
    END
  END Tile_X0Y1_N2MID[0]
  PIN Tile_X0Y1_N2MID[1]
    DIRECTION INPUT ;
    USE SIGNAL ;
    ANTENNAGATEAREA 0.426400 ;
    PORT
      LAYER Metal2 ;
        RECT 14.680 0.000 15.080 0.400 ;
    END
  END Tile_X0Y1_N2MID[1]
  PIN Tile_X0Y1_N2MID[2]
    DIRECTION INPUT ;
    USE SIGNAL ;
    ANTENNAGATEAREA 2.860000 ;
    ANTENNADIFFAREA 8.061600 ;
    PORT
      LAYER Metal2 ;
        RECT 15.640 0.000 16.040 0.400 ;
    END
  END Tile_X0Y1_N2MID[2]
  PIN Tile_X0Y1_N2MID[3]
    DIRECTION INPUT ;
    USE SIGNAL ;
    ANTENNAGATEAREA 0.426400 ;
    PORT
      LAYER Metal2 ;
        RECT 16.600 0.000 17.000 0.400 ;
    END
  END Tile_X0Y1_N2MID[3]
  PIN Tile_X0Y1_N2MID[4]
    DIRECTION INPUT ;
    USE SIGNAL ;
    ANTENNAGATEAREA 0.426400 ;
    PORT
      LAYER Metal2 ;
        RECT 17.560 0.000 17.960 0.400 ;
    END
  END Tile_X0Y1_N2MID[4]
  PIN Tile_X0Y1_N2MID[5]
    DIRECTION INPUT ;
    USE SIGNAL ;
    ANTENNAGATEAREA 0.426400 ;
    PORT
      LAYER Metal2 ;
        RECT 18.520 0.000 18.920 0.400 ;
    END
  END Tile_X0Y1_N2MID[5]
  PIN Tile_X0Y1_N2MID[6]
    DIRECTION INPUT ;
    USE SIGNAL ;
    ANTENNAGATEAREA 1.062100 ;
    PORT
      LAYER Metal2 ;
        RECT 19.480 0.000 19.880 0.400 ;
    END
  END Tile_X0Y1_N2MID[6]
  PIN Tile_X0Y1_N2MID[7]
    DIRECTION INPUT ;
    USE SIGNAL ;
    ANTENNAGATEAREA 2.860000 ;
    ANTENNADIFFAREA 8.061600 ;
    PORT
      LAYER Metal2 ;
        RECT 20.440 0.000 20.840 0.400 ;
    END
  END Tile_X0Y1_N2MID[7]
  PIN Tile_X0Y1_N4END[0]
    DIRECTION INPUT ;
    USE SIGNAL ;
    ANTENNAGATEAREA 1.066000 ;
    PORT
      LAYER Metal2 ;
        RECT 29.080 0.000 29.480 0.400 ;
    END
  END Tile_X0Y1_N4END[0]
  PIN Tile_X0Y1_N4END[10]
    DIRECTION INPUT ;
    USE SIGNAL ;
    ANTENNAGATEAREA 0.180700 ;
    PORT
      LAYER Metal2 ;
        RECT 38.680 0.000 39.080 0.400 ;
    END
  END Tile_X0Y1_N4END[10]
  PIN Tile_X0Y1_N4END[11]
    DIRECTION INPUT ;
    USE SIGNAL ;
    ANTENNAGATEAREA 0.180700 ;
    PORT
      LAYER Metal2 ;
        RECT 39.640 0.000 40.040 0.400 ;
    END
  END Tile_X0Y1_N4END[11]
  PIN Tile_X0Y1_N4END[12]
    DIRECTION INPUT ;
    USE SIGNAL ;
    ANTENNAGATEAREA 0.180700 ;
    PORT
      LAYER Metal2 ;
        RECT 40.600 0.000 41.000 0.400 ;
    END
  END Tile_X0Y1_N4END[12]
  PIN Tile_X0Y1_N4END[13]
    DIRECTION INPUT ;
    USE SIGNAL ;
    ANTENNAGATEAREA 0.180700 ;
    PORT
      LAYER Metal2 ;
        RECT 41.560 0.000 41.960 0.400 ;
    END
  END Tile_X0Y1_N4END[13]
  PIN Tile_X0Y1_N4END[14]
    DIRECTION INPUT ;
    USE SIGNAL ;
    ANTENNAGATEAREA 0.180700 ;
    PORT
      LAYER Metal2 ;
        RECT 42.520 0.000 42.920 0.400 ;
    END
  END Tile_X0Y1_N4END[14]
  PIN Tile_X0Y1_N4END[15]
    DIRECTION INPUT ;
    USE SIGNAL ;
    ANTENNAGATEAREA 0.180700 ;
    PORT
      LAYER Metal2 ;
        RECT 43.480 0.000 43.880 0.400 ;
    END
  END Tile_X0Y1_N4END[15]
  PIN Tile_X0Y1_N4END[1]
    DIRECTION INPUT ;
    USE SIGNAL ;
    ANTENNAGATEAREA 1.066000 ;
    PORT
      LAYER Metal2 ;
        RECT 30.040 0.000 30.440 0.400 ;
    END
  END Tile_X0Y1_N4END[1]
  PIN Tile_X0Y1_N4END[2]
    DIRECTION INPUT ;
    USE SIGNAL ;
    ANTENNAGATEAREA 1.066000 ;
    PORT
      LAYER Metal2 ;
        RECT 31.000 0.000 31.400 0.400 ;
    END
  END Tile_X0Y1_N4END[2]
  PIN Tile_X0Y1_N4END[3]
    DIRECTION INPUT ;
    USE SIGNAL ;
    ANTENNAGATEAREA 1.066000 ;
    PORT
      LAYER Metal2 ;
        RECT 31.960 0.000 32.360 0.400 ;
    END
  END Tile_X0Y1_N4END[3]
  PIN Tile_X0Y1_N4END[4]
    DIRECTION INPUT ;
    USE SIGNAL ;
    ANTENNAGATEAREA 1.066000 ;
    PORT
      LAYER Metal2 ;
        RECT 32.920 0.000 33.320 0.400 ;
    END
  END Tile_X0Y1_N4END[4]
  PIN Tile_X0Y1_N4END[5]
    DIRECTION INPUT ;
    USE SIGNAL ;
    ANTENNAGATEAREA 1.066000 ;
    PORT
      LAYER Metal2 ;
        RECT 33.880 0.000 34.280 0.400 ;
    END
  END Tile_X0Y1_N4END[5]
  PIN Tile_X0Y1_N4END[6]
    DIRECTION INPUT ;
    USE SIGNAL ;
    ANTENNAGATEAREA 1.066000 ;
    PORT
      LAYER Metal2 ;
        RECT 34.840 0.000 35.240 0.400 ;
    END
  END Tile_X0Y1_N4END[6]
  PIN Tile_X0Y1_N4END[7]
    DIRECTION INPUT ;
    USE SIGNAL ;
    ANTENNAGATEAREA 1.066000 ;
    PORT
      LAYER Metal2 ;
        RECT 35.800 0.000 36.200 0.400 ;
    END
  END Tile_X0Y1_N4END[7]
  PIN Tile_X0Y1_N4END[8]
    DIRECTION INPUT ;
    USE SIGNAL ;
    ANTENNAGATEAREA 0.180700 ;
    PORT
      LAYER Metal2 ;
        RECT 36.760 0.000 37.160 0.400 ;
    END
  END Tile_X0Y1_N4END[8]
  PIN Tile_X0Y1_N4END[9]
    DIRECTION INPUT ;
    USE SIGNAL ;
    ANTENNAGATEAREA 0.180700 ;
    PORT
      LAYER Metal2 ;
        RECT 37.720 0.000 38.120 0.400 ;
    END
  END Tile_X0Y1_N4END[9]
  PIN Tile_X0Y1_S1BEG[0]
    DIRECTION OUTPUT ;
    USE SIGNAL ;
    ANTENNADIFFAREA 0.708600 ;
    PORT
      LAYER Metal2 ;
        RECT 44.440 0.000 44.840 0.400 ;
    END
  END Tile_X0Y1_S1BEG[0]
  PIN Tile_X0Y1_S1BEG[1]
    DIRECTION OUTPUT ;
    USE SIGNAL ;
    ANTENNADIFFAREA 0.708600 ;
    PORT
      LAYER Metal2 ;
        RECT 45.400 0.000 45.800 0.400 ;
    END
  END Tile_X0Y1_S1BEG[1]
  PIN Tile_X0Y1_S1BEG[2]
    DIRECTION OUTPUT ;
    USE SIGNAL ;
    ANTENNADIFFAREA 0.708600 ;
    PORT
      LAYER Metal2 ;
        RECT 46.360 0.000 46.760 0.400 ;
    END
  END Tile_X0Y1_S1BEG[2]
  PIN Tile_X0Y1_S1BEG[3]
    DIRECTION OUTPUT ;
    USE SIGNAL ;
    ANTENNADIFFAREA 0.708600 ;
    PORT
      LAYER Metal2 ;
        RECT 47.320 0.000 47.720 0.400 ;
    END
  END Tile_X0Y1_S1BEG[3]
  PIN Tile_X0Y1_S2BEG[0]
    DIRECTION OUTPUT ;
    USE SIGNAL ;
    ANTENNADIFFAREA 0.708600 ;
    PORT
      LAYER Metal2 ;
        RECT 48.280 0.000 48.680 0.400 ;
    END
  END Tile_X0Y1_S2BEG[0]
  PIN Tile_X0Y1_S2BEG[1]
    DIRECTION OUTPUT ;
    USE SIGNAL ;
    ANTENNADIFFAREA 0.708600 ;
    PORT
      LAYER Metal2 ;
        RECT 49.240 0.000 49.640 0.400 ;
    END
  END Tile_X0Y1_S2BEG[1]
  PIN Tile_X0Y1_S2BEG[2]
    DIRECTION OUTPUT ;
    USE SIGNAL ;
    ANTENNADIFFAREA 0.708600 ;
    PORT
      LAYER Metal2 ;
        RECT 50.200 0.000 50.600 0.400 ;
    END
  END Tile_X0Y1_S2BEG[2]
  PIN Tile_X0Y1_S2BEG[3]
    DIRECTION OUTPUT ;
    USE SIGNAL ;
    ANTENNADIFFAREA 0.708600 ;
    PORT
      LAYER Metal2 ;
        RECT 51.160 0.000 51.560 0.400 ;
    END
  END Tile_X0Y1_S2BEG[3]
  PIN Tile_X0Y1_S2BEG[4]
    DIRECTION OUTPUT ;
    USE SIGNAL ;
    ANTENNADIFFAREA 0.708600 ;
    PORT
      LAYER Metal2 ;
        RECT 52.120 0.000 52.520 0.400 ;
    END
  END Tile_X0Y1_S2BEG[4]
  PIN Tile_X0Y1_S2BEG[5]
    DIRECTION OUTPUT ;
    USE SIGNAL ;
    ANTENNADIFFAREA 0.708600 ;
    PORT
      LAYER Metal2 ;
        RECT 53.080 0.000 53.480 0.400 ;
    END
  END Tile_X0Y1_S2BEG[5]
  PIN Tile_X0Y1_S2BEG[6]
    DIRECTION OUTPUT ;
    USE SIGNAL ;
    ANTENNADIFFAREA 0.708600 ;
    PORT
      LAYER Metal2 ;
        RECT 54.040 0.000 54.440 0.400 ;
    END
  END Tile_X0Y1_S2BEG[6]
  PIN Tile_X0Y1_S2BEG[7]
    DIRECTION OUTPUT ;
    USE SIGNAL ;
    ANTENNADIFFAREA 0.708600 ;
    PORT
      LAYER Metal2 ;
        RECT 55.000 0.000 55.400 0.400 ;
    END
  END Tile_X0Y1_S2BEG[7]
  PIN Tile_X0Y1_S2BEGb[0]
    DIRECTION OUTPUT ;
    USE SIGNAL ;
    ANTENNADIFFAREA 0.708600 ;
    PORT
      LAYER Metal2 ;
        RECT 55.960 0.000 56.360 0.400 ;
    END
  END Tile_X0Y1_S2BEGb[0]
  PIN Tile_X0Y1_S2BEGb[1]
    DIRECTION OUTPUT ;
    USE SIGNAL ;
    ANTENNADIFFAREA 0.708600 ;
    PORT
      LAYER Metal2 ;
        RECT 56.920 0.000 57.320 0.400 ;
    END
  END Tile_X0Y1_S2BEGb[1]
  PIN Tile_X0Y1_S2BEGb[2]
    DIRECTION OUTPUT ;
    USE SIGNAL ;
    ANTENNADIFFAREA 0.708600 ;
    PORT
      LAYER Metal2 ;
        RECT 57.880 0.000 58.280 0.400 ;
    END
  END Tile_X0Y1_S2BEGb[2]
  PIN Tile_X0Y1_S2BEGb[3]
    DIRECTION OUTPUT ;
    USE SIGNAL ;
    ANTENNADIFFAREA 0.708600 ;
    PORT
      LAYER Metal2 ;
        RECT 58.840 0.000 59.240 0.400 ;
    END
  END Tile_X0Y1_S2BEGb[3]
  PIN Tile_X0Y1_S2BEGb[4]
    DIRECTION OUTPUT ;
    USE SIGNAL ;
    ANTENNADIFFAREA 0.708600 ;
    PORT
      LAYER Metal2 ;
        RECT 59.800 0.000 60.200 0.400 ;
    END
  END Tile_X0Y1_S2BEGb[4]
  PIN Tile_X0Y1_S2BEGb[5]
    DIRECTION OUTPUT ;
    USE SIGNAL ;
    ANTENNADIFFAREA 0.708600 ;
    PORT
      LAYER Metal2 ;
        RECT 60.760 0.000 61.160 0.400 ;
    END
  END Tile_X0Y1_S2BEGb[5]
  PIN Tile_X0Y1_S2BEGb[6]
    DIRECTION OUTPUT ;
    USE SIGNAL ;
    ANTENNADIFFAREA 0.708600 ;
    PORT
      LAYER Metal2 ;
        RECT 61.720 0.000 62.120 0.400 ;
    END
  END Tile_X0Y1_S2BEGb[6]
  PIN Tile_X0Y1_S2BEGb[7]
    DIRECTION OUTPUT ;
    USE SIGNAL ;
    ANTENNADIFFAREA 0.708600 ;
    PORT
      LAYER Metal2 ;
        RECT 62.680 0.000 63.080 0.400 ;
    END
  END Tile_X0Y1_S2BEGb[7]
  PIN Tile_X0Y1_S4BEG[0]
    DIRECTION OUTPUT ;
    USE SIGNAL ;
    ANTENNADIFFAREA 0.708600 ;
    PORT
      LAYER Metal2 ;
        RECT 63.640 0.000 64.040 0.400 ;
    END
  END Tile_X0Y1_S4BEG[0]
  PIN Tile_X0Y1_S4BEG[10]
    DIRECTION OUTPUT ;
    USE SIGNAL ;
    ANTENNADIFFAREA 0.708600 ;
    PORT
      LAYER Metal2 ;
        RECT 73.240 0.000 73.640 0.400 ;
    END
  END Tile_X0Y1_S4BEG[10]
  PIN Tile_X0Y1_S4BEG[11]
    DIRECTION OUTPUT ;
    USE SIGNAL ;
    ANTENNADIFFAREA 0.708600 ;
    PORT
      LAYER Metal2 ;
        RECT 74.200 0.000 74.600 0.400 ;
    END
  END Tile_X0Y1_S4BEG[11]
  PIN Tile_X0Y1_S4BEG[12]
    DIRECTION OUTPUT ;
    USE SIGNAL ;
    ANTENNADIFFAREA 0.708600 ;
    PORT
      LAYER Metal2 ;
        RECT 75.160 0.000 75.560 0.400 ;
    END
  END Tile_X0Y1_S4BEG[12]
  PIN Tile_X0Y1_S4BEG[13]
    DIRECTION OUTPUT ;
    USE SIGNAL ;
    ANTENNADIFFAREA 0.708600 ;
    PORT
      LAYER Metal2 ;
        RECT 76.120 0.000 76.520 0.400 ;
    END
  END Tile_X0Y1_S4BEG[13]
  PIN Tile_X0Y1_S4BEG[14]
    DIRECTION OUTPUT ;
    USE SIGNAL ;
    ANTENNADIFFAREA 0.708600 ;
    PORT
      LAYER Metal2 ;
        RECT 77.080 0.000 77.480 0.400 ;
    END
  END Tile_X0Y1_S4BEG[14]
  PIN Tile_X0Y1_S4BEG[15]
    DIRECTION OUTPUT ;
    USE SIGNAL ;
    ANTENNADIFFAREA 0.708600 ;
    PORT
      LAYER Metal2 ;
        RECT 78.040 0.000 78.440 0.400 ;
    END
  END Tile_X0Y1_S4BEG[15]
  PIN Tile_X0Y1_S4BEG[1]
    DIRECTION OUTPUT ;
    USE SIGNAL ;
    ANTENNADIFFAREA 0.708600 ;
    PORT
      LAYER Metal2 ;
        RECT 64.600 0.000 65.000 0.400 ;
    END
  END Tile_X0Y1_S4BEG[1]
  PIN Tile_X0Y1_S4BEG[2]
    DIRECTION OUTPUT ;
    USE SIGNAL ;
    ANTENNADIFFAREA 0.708600 ;
    PORT
      LAYER Metal2 ;
        RECT 65.560 0.000 65.960 0.400 ;
    END
  END Tile_X0Y1_S4BEG[2]
  PIN Tile_X0Y1_S4BEG[3]
    DIRECTION OUTPUT ;
    USE SIGNAL ;
    ANTENNADIFFAREA 0.708600 ;
    PORT
      LAYER Metal2 ;
        RECT 66.520 0.000 66.920 0.400 ;
    END
  END Tile_X0Y1_S4BEG[3]
  PIN Tile_X0Y1_S4BEG[4]
    DIRECTION OUTPUT ;
    USE SIGNAL ;
    ANTENNADIFFAREA 0.708600 ;
    PORT
      LAYER Metal2 ;
        RECT 67.480 0.000 67.880 0.400 ;
    END
  END Tile_X0Y1_S4BEG[4]
  PIN Tile_X0Y1_S4BEG[5]
    DIRECTION OUTPUT ;
    USE SIGNAL ;
    ANTENNADIFFAREA 0.708600 ;
    PORT
      LAYER Metal2 ;
        RECT 68.440 0.000 68.840 0.400 ;
    END
  END Tile_X0Y1_S4BEG[5]
  PIN Tile_X0Y1_S4BEG[6]
    DIRECTION OUTPUT ;
    USE SIGNAL ;
    ANTENNADIFFAREA 0.708600 ;
    PORT
      LAYER Metal2 ;
        RECT 69.400 0.000 69.800 0.400 ;
    END
  END Tile_X0Y1_S4BEG[6]
  PIN Tile_X0Y1_S4BEG[7]
    DIRECTION OUTPUT ;
    USE SIGNAL ;
    ANTENNADIFFAREA 0.708600 ;
    PORT
      LAYER Metal2 ;
        RECT 70.360 0.000 70.760 0.400 ;
    END
  END Tile_X0Y1_S4BEG[7]
  PIN Tile_X0Y1_S4BEG[8]
    DIRECTION OUTPUT ;
    USE SIGNAL ;
    ANTENNADIFFAREA 0.708600 ;
    PORT
      LAYER Metal2 ;
        RECT 71.320 0.000 71.720 0.400 ;
    END
  END Tile_X0Y1_S4BEG[8]
  PIN Tile_X0Y1_S4BEG[9]
    DIRECTION OUTPUT ;
    USE SIGNAL ;
    ANTENNADIFFAREA 0.708600 ;
    PORT
      LAYER Metal2 ;
        RECT 72.280 0.000 72.680 0.400 ;
    END
  END Tile_X0Y1_S4BEG[9]
  PIN Tile_X0Y1_UserCLK
    DIRECTION INPUT ;
    USE SIGNAL ;
    ANTENNAGATEAREA 1.333800 ;
    ANTENNADIFFAREA 2.015400 ;
    PORT
      LAYER Metal2 ;
        RECT 79.000 0.000 79.400 0.400 ;
    END
  END Tile_X0Y1_UserCLK
  PIN Tile_X0Y1_W1BEG[0]
    DIRECTION OUTPUT ;
    USE SIGNAL ;
    ANTENNADIFFAREA 0.708600 ;
    PORT
      LAYER Metal3 ;
        RECT 0.000 0.220 0.400 0.620 ;
    END
  END Tile_X0Y1_W1BEG[0]
  PIN Tile_X0Y1_W1BEG[1]
    DIRECTION OUTPUT ;
    USE SIGNAL ;
    ANTENNADIFFAREA 0.708600 ;
    PORT
      LAYER Metal3 ;
        RECT 0.000 1.900 0.400 2.300 ;
    END
  END Tile_X0Y1_W1BEG[1]
  PIN Tile_X0Y1_W1BEG[2]
    DIRECTION OUTPUT ;
    USE SIGNAL ;
    ANTENNADIFFAREA 0.708600 ;
    PORT
      LAYER Metal3 ;
        RECT 0.000 3.580 0.400 3.980 ;
    END
  END Tile_X0Y1_W1BEG[2]
  PIN Tile_X0Y1_W1BEG[3]
    DIRECTION OUTPUT ;
    USE SIGNAL ;
    ANTENNADIFFAREA 0.708600 ;
    PORT
      LAYER Metal3 ;
        RECT 0.000 5.260 0.400 5.660 ;
    END
  END Tile_X0Y1_W1BEG[3]
  PIN Tile_X0Y1_W2BEG[0]
    DIRECTION OUTPUT ;
    USE SIGNAL ;
    ANTENNADIFFAREA 0.708600 ;
    PORT
      LAYER Metal3 ;
        RECT 0.000 6.940 0.400 7.340 ;
    END
  END Tile_X0Y1_W2BEG[0]
  PIN Tile_X0Y1_W2BEG[1]
    DIRECTION OUTPUT ;
    USE SIGNAL ;
    ANTENNADIFFAREA 0.708600 ;
    PORT
      LAYER Metal3 ;
        RECT 0.000 8.620 0.400 9.020 ;
    END
  END Tile_X0Y1_W2BEG[1]
  PIN Tile_X0Y1_W2BEG[2]
    DIRECTION OUTPUT ;
    USE SIGNAL ;
    ANTENNADIFFAREA 0.708600 ;
    PORT
      LAYER Metal3 ;
        RECT 0.000 10.300 0.400 10.700 ;
    END
  END Tile_X0Y1_W2BEG[2]
  PIN Tile_X0Y1_W2BEG[3]
    DIRECTION OUTPUT ;
    USE SIGNAL ;
    ANTENNADIFFAREA 0.708600 ;
    PORT
      LAYER Metal3 ;
        RECT 0.000 11.980 0.400 12.380 ;
    END
  END Tile_X0Y1_W2BEG[3]
  PIN Tile_X0Y1_W2BEG[4]
    DIRECTION OUTPUT ;
    USE SIGNAL ;
    ANTENNADIFFAREA 0.708600 ;
    PORT
      LAYER Metal3 ;
        RECT 0.000 13.660 0.400 14.060 ;
    END
  END Tile_X0Y1_W2BEG[4]
  PIN Tile_X0Y1_W2BEG[5]
    DIRECTION OUTPUT ;
    USE SIGNAL ;
    ANTENNADIFFAREA 0.708600 ;
    PORT
      LAYER Metal3 ;
        RECT 0.000 15.340 0.400 15.740 ;
    END
  END Tile_X0Y1_W2BEG[5]
  PIN Tile_X0Y1_W2BEG[6]
    DIRECTION OUTPUT ;
    USE SIGNAL ;
    ANTENNADIFFAREA 0.708600 ;
    PORT
      LAYER Metal3 ;
        RECT 0.000 17.020 0.400 17.420 ;
    END
  END Tile_X0Y1_W2BEG[6]
  PIN Tile_X0Y1_W2BEG[7]
    DIRECTION OUTPUT ;
    USE SIGNAL ;
    ANTENNADIFFAREA 0.708600 ;
    PORT
      LAYER Metal3 ;
        RECT 0.000 18.700 0.400 19.100 ;
    END
  END Tile_X0Y1_W2BEG[7]
  PIN Tile_X0Y1_W2BEGb[0]
    DIRECTION OUTPUT ;
    USE SIGNAL ;
    ANTENNADIFFAREA 0.708600 ;
    PORT
      LAYER Metal3 ;
        RECT 0.000 20.380 0.400 20.780 ;
    END
  END Tile_X0Y1_W2BEGb[0]
  PIN Tile_X0Y1_W2BEGb[1]
    DIRECTION OUTPUT ;
    USE SIGNAL ;
    ANTENNADIFFAREA 0.708600 ;
    PORT
      LAYER Metal3 ;
        RECT 0.000 22.060 0.400 22.460 ;
    END
  END Tile_X0Y1_W2BEGb[1]
  PIN Tile_X0Y1_W2BEGb[2]
    DIRECTION OUTPUT ;
    USE SIGNAL ;
    ANTENNADIFFAREA 0.708600 ;
    PORT
      LAYER Metal3 ;
        RECT 0.000 23.740 0.400 24.140 ;
    END
  END Tile_X0Y1_W2BEGb[2]
  PIN Tile_X0Y1_W2BEGb[3]
    DIRECTION OUTPUT ;
    USE SIGNAL ;
    ANTENNADIFFAREA 0.708600 ;
    PORT
      LAYER Metal3 ;
        RECT 0.000 25.420 0.400 25.820 ;
    END
  END Tile_X0Y1_W2BEGb[3]
  PIN Tile_X0Y1_W2BEGb[4]
    DIRECTION OUTPUT ;
    USE SIGNAL ;
    ANTENNADIFFAREA 0.708600 ;
    PORT
      LAYER Metal3 ;
        RECT 0.000 27.100 0.400 27.500 ;
    END
  END Tile_X0Y1_W2BEGb[4]
  PIN Tile_X0Y1_W2BEGb[5]
    DIRECTION OUTPUT ;
    USE SIGNAL ;
    ANTENNADIFFAREA 0.708600 ;
    PORT
      LAYER Metal3 ;
        RECT 0.000 28.780 0.400 29.180 ;
    END
  END Tile_X0Y1_W2BEGb[5]
  PIN Tile_X0Y1_W2BEGb[6]
    DIRECTION OUTPUT ;
    USE SIGNAL ;
    ANTENNADIFFAREA 0.708600 ;
    PORT
      LAYER Metal3 ;
        RECT 0.000 30.460 0.400 30.860 ;
    END
  END Tile_X0Y1_W2BEGb[6]
  PIN Tile_X0Y1_W2BEGb[7]
    DIRECTION OUTPUT ;
    USE SIGNAL ;
    ANTENNADIFFAREA 0.708600 ;
    PORT
      LAYER Metal3 ;
        RECT 0.000 32.140 0.400 32.540 ;
    END
  END Tile_X0Y1_W2BEGb[7]
  PIN Tile_X0Y1_W6BEG[0]
    DIRECTION OUTPUT ;
    USE SIGNAL ;
    ANTENNADIFFAREA 0.708600 ;
    PORT
      LAYER Metal3 ;
        RECT 0.000 60.700 0.400 61.100 ;
    END
  END Tile_X0Y1_W6BEG[0]
  PIN Tile_X0Y1_W6BEG[10]
    DIRECTION OUTPUT ;
    USE SIGNAL ;
    ANTENNADIFFAREA 0.708600 ;
    PORT
      LAYER Metal3 ;
        RECT 0.000 77.500 0.400 77.900 ;
    END
  END Tile_X0Y1_W6BEG[10]
  PIN Tile_X0Y1_W6BEG[11]
    DIRECTION OUTPUT ;
    USE SIGNAL ;
    ANTENNADIFFAREA 0.708600 ;
    PORT
      LAYER Metal3 ;
        RECT 0.000 79.180 0.400 79.580 ;
    END
  END Tile_X0Y1_W6BEG[11]
  PIN Tile_X0Y1_W6BEG[1]
    DIRECTION OUTPUT ;
    USE SIGNAL ;
    ANTENNADIFFAREA 0.708600 ;
    PORT
      LAYER Metal3 ;
        RECT 0.000 62.380 0.400 62.780 ;
    END
  END Tile_X0Y1_W6BEG[1]
  PIN Tile_X0Y1_W6BEG[2]
    DIRECTION OUTPUT ;
    USE SIGNAL ;
    ANTENNADIFFAREA 0.708600 ;
    PORT
      LAYER Metal3 ;
        RECT 0.000 64.060 0.400 64.460 ;
    END
  END Tile_X0Y1_W6BEG[2]
  PIN Tile_X0Y1_W6BEG[3]
    DIRECTION OUTPUT ;
    USE SIGNAL ;
    ANTENNADIFFAREA 0.708600 ;
    PORT
      LAYER Metal3 ;
        RECT 0.000 65.740 0.400 66.140 ;
    END
  END Tile_X0Y1_W6BEG[3]
  PIN Tile_X0Y1_W6BEG[4]
    DIRECTION OUTPUT ;
    USE SIGNAL ;
    ANTENNADIFFAREA 0.708600 ;
    PORT
      LAYER Metal3 ;
        RECT 0.000 67.420 0.400 67.820 ;
    END
  END Tile_X0Y1_W6BEG[4]
  PIN Tile_X0Y1_W6BEG[5]
    DIRECTION OUTPUT ;
    USE SIGNAL ;
    ANTENNADIFFAREA 0.708600 ;
    PORT
      LAYER Metal3 ;
        RECT 0.000 69.100 0.400 69.500 ;
    END
  END Tile_X0Y1_W6BEG[5]
  PIN Tile_X0Y1_W6BEG[6]
    DIRECTION OUTPUT ;
    USE SIGNAL ;
    ANTENNADIFFAREA 0.708600 ;
    PORT
      LAYER Metal3 ;
        RECT 0.000 70.780 0.400 71.180 ;
    END
  END Tile_X0Y1_W6BEG[6]
  PIN Tile_X0Y1_W6BEG[7]
    DIRECTION OUTPUT ;
    USE SIGNAL ;
    ANTENNADIFFAREA 0.708600 ;
    PORT
      LAYER Metal3 ;
        RECT 0.000 72.460 0.400 72.860 ;
    END
  END Tile_X0Y1_W6BEG[7]
  PIN Tile_X0Y1_W6BEG[8]
    DIRECTION OUTPUT ;
    USE SIGNAL ;
    ANTENNADIFFAREA 0.708600 ;
    PORT
      LAYER Metal3 ;
        RECT 0.000 74.140 0.400 74.540 ;
    END
  END Tile_X0Y1_W6BEG[8]
  PIN Tile_X0Y1_W6BEG[9]
    DIRECTION OUTPUT ;
    USE SIGNAL ;
    ANTENNADIFFAREA 0.708600 ;
    PORT
      LAYER Metal3 ;
        RECT 0.000 75.820 0.400 76.220 ;
    END
  END Tile_X0Y1_W6BEG[9]
  PIN Tile_X0Y1_WW4BEG[0]
    DIRECTION OUTPUT ;
    USE SIGNAL ;
    ANTENNADIFFAREA 0.708600 ;
    PORT
      LAYER Metal3 ;
        RECT 0.000 33.820 0.400 34.220 ;
    END
  END Tile_X0Y1_WW4BEG[0]
  PIN Tile_X0Y1_WW4BEG[10]
    DIRECTION OUTPUT ;
    USE SIGNAL ;
    ANTENNADIFFAREA 0.708600 ;
    PORT
      LAYER Metal3 ;
        RECT 0.000 50.620 0.400 51.020 ;
    END
  END Tile_X0Y1_WW4BEG[10]
  PIN Tile_X0Y1_WW4BEG[11]
    DIRECTION OUTPUT ;
    USE SIGNAL ;
    ANTENNADIFFAREA 0.708600 ;
    PORT
      LAYER Metal3 ;
        RECT 0.000 52.300 0.400 52.700 ;
    END
  END Tile_X0Y1_WW4BEG[11]
  PIN Tile_X0Y1_WW4BEG[12]
    DIRECTION OUTPUT ;
    USE SIGNAL ;
    ANTENNADIFFAREA 0.708600 ;
    PORT
      LAYER Metal3 ;
        RECT 0.000 53.980 0.400 54.380 ;
    END
  END Tile_X0Y1_WW4BEG[12]
  PIN Tile_X0Y1_WW4BEG[13]
    DIRECTION OUTPUT ;
    USE SIGNAL ;
    ANTENNADIFFAREA 0.708600 ;
    PORT
      LAYER Metal3 ;
        RECT 0.000 55.660 0.400 56.060 ;
    END
  END Tile_X0Y1_WW4BEG[13]
  PIN Tile_X0Y1_WW4BEG[14]
    DIRECTION OUTPUT ;
    USE SIGNAL ;
    ANTENNADIFFAREA 0.708600 ;
    PORT
      LAYER Metal3 ;
        RECT 0.000 57.340 0.400 57.740 ;
    END
  END Tile_X0Y1_WW4BEG[14]
  PIN Tile_X0Y1_WW4BEG[15]
    DIRECTION OUTPUT ;
    USE SIGNAL ;
    ANTENNADIFFAREA 0.708600 ;
    PORT
      LAYER Metal3 ;
        RECT 0.000 59.020 0.400 59.420 ;
    END
  END Tile_X0Y1_WW4BEG[15]
  PIN Tile_X0Y1_WW4BEG[1]
    DIRECTION OUTPUT ;
    USE SIGNAL ;
    ANTENNADIFFAREA 0.708600 ;
    PORT
      LAYER Metal3 ;
        RECT 0.000 35.500 0.400 35.900 ;
    END
  END Tile_X0Y1_WW4BEG[1]
  PIN Tile_X0Y1_WW4BEG[2]
    DIRECTION OUTPUT ;
    USE SIGNAL ;
    ANTENNADIFFAREA 0.708600 ;
    PORT
      LAYER Metal3 ;
        RECT 0.000 37.180 0.400 37.580 ;
    END
  END Tile_X0Y1_WW4BEG[2]
  PIN Tile_X0Y1_WW4BEG[3]
    DIRECTION OUTPUT ;
    USE SIGNAL ;
    ANTENNADIFFAREA 0.708600 ;
    PORT
      LAYER Metal3 ;
        RECT 0.000 38.860 0.400 39.260 ;
    END
  END Tile_X0Y1_WW4BEG[3]
  PIN Tile_X0Y1_WW4BEG[4]
    DIRECTION OUTPUT ;
    USE SIGNAL ;
    ANTENNADIFFAREA 0.708600 ;
    PORT
      LAYER Metal3 ;
        RECT 0.000 40.540 0.400 40.940 ;
    END
  END Tile_X0Y1_WW4BEG[4]
  PIN Tile_X0Y1_WW4BEG[5]
    DIRECTION OUTPUT ;
    USE SIGNAL ;
    ANTENNADIFFAREA 0.708600 ;
    PORT
      LAYER Metal3 ;
        RECT 0.000 42.220 0.400 42.620 ;
    END
  END Tile_X0Y1_WW4BEG[5]
  PIN Tile_X0Y1_WW4BEG[6]
    DIRECTION OUTPUT ;
    USE SIGNAL ;
    ANTENNADIFFAREA 0.708600 ;
    PORT
      LAYER Metal3 ;
        RECT 0.000 43.900 0.400 44.300 ;
    END
  END Tile_X0Y1_WW4BEG[6]
  PIN Tile_X0Y1_WW4BEG[7]
    DIRECTION OUTPUT ;
    USE SIGNAL ;
    ANTENNADIFFAREA 0.708600 ;
    PORT
      LAYER Metal3 ;
        RECT 0.000 45.580 0.400 45.980 ;
    END
  END Tile_X0Y1_WW4BEG[7]
  PIN Tile_X0Y1_WW4BEG[8]
    DIRECTION OUTPUT ;
    USE SIGNAL ;
    ANTENNADIFFAREA 0.708600 ;
    PORT
      LAYER Metal3 ;
        RECT 0.000 47.260 0.400 47.660 ;
    END
  END Tile_X0Y1_WW4BEG[8]
  PIN Tile_X0Y1_WW4BEG[9]
    DIRECTION OUTPUT ;
    USE SIGNAL ;
    ANTENNADIFFAREA 0.708600 ;
    PORT
      LAYER Metal3 ;
        RECT 0.000 48.940 0.400 49.340 ;
    END
  END Tile_X0Y1_WW4BEG[9]
  PIN VGND
    DIRECTION INOUT ;
    USE GROUND ;
    PORT
      LAYER TopMetal1 ;
        RECT 21.580 0.000 23.780 430.920 ;
    END
    PORT
      LAYER TopMetal1 ;
        RECT 97.180 0.000 99.380 430.920 ;
    END
  END VGND
  PIN VPWR
    DIRECTION INOUT ;
    USE POWER ;
    PORT
      LAYER TopMetal1 ;
        RECT 15.380 0.000 17.580 430.920 ;
    END
    PORT
      LAYER TopMetal1 ;
        RECT 90.980 0.000 93.180 430.920 ;
    END
  END VPWR
  OBS
      LAYER GatPoly ;
        RECT 2.880 3.630 106.560 427.290 ;
      LAYER Metal1 ;
        RECT 2.880 3.560 106.560 427.360 ;
      LAYER Metal2 ;
        RECT 0.375 430.310 9.670 430.820 ;
        RECT 10.490 430.310 10.630 430.820 ;
        RECT 11.450 430.310 11.590 430.820 ;
        RECT 12.410 430.310 12.550 430.820 ;
        RECT 13.370 430.310 13.510 430.820 ;
        RECT 14.330 430.310 14.470 430.820 ;
        RECT 15.290 430.310 15.430 430.820 ;
        RECT 16.250 430.310 16.390 430.820 ;
        RECT 17.210 430.310 17.350 430.820 ;
        RECT 18.170 430.310 18.310 430.820 ;
        RECT 19.130 430.310 19.270 430.820 ;
        RECT 20.090 430.310 20.230 430.820 ;
        RECT 21.050 430.310 21.190 430.820 ;
        RECT 22.010 430.310 22.150 430.820 ;
        RECT 22.970 430.310 23.110 430.820 ;
        RECT 23.930 430.310 24.070 430.820 ;
        RECT 24.890 430.310 25.030 430.820 ;
        RECT 25.850 430.310 25.990 430.820 ;
        RECT 26.810 430.310 26.950 430.820 ;
        RECT 27.770 430.310 27.910 430.820 ;
        RECT 28.730 430.310 28.870 430.820 ;
        RECT 29.690 430.310 29.830 430.820 ;
        RECT 30.650 430.310 30.790 430.820 ;
        RECT 31.610 430.310 31.750 430.820 ;
        RECT 32.570 430.310 32.710 430.820 ;
        RECT 33.530 430.310 33.670 430.820 ;
        RECT 34.490 430.310 34.630 430.820 ;
        RECT 35.450 430.310 35.590 430.820 ;
        RECT 36.410 430.310 36.550 430.820 ;
        RECT 37.370 430.310 37.510 430.820 ;
        RECT 38.330 430.310 38.470 430.820 ;
        RECT 39.290 430.310 39.430 430.820 ;
        RECT 40.250 430.310 40.390 430.820 ;
        RECT 41.210 430.310 41.350 430.820 ;
        RECT 42.170 430.310 42.310 430.820 ;
        RECT 43.130 430.310 43.270 430.820 ;
        RECT 44.090 430.310 44.230 430.820 ;
        RECT 45.050 430.310 45.190 430.820 ;
        RECT 46.010 430.310 46.150 430.820 ;
        RECT 46.970 430.310 47.110 430.820 ;
        RECT 47.930 430.310 48.070 430.820 ;
        RECT 48.890 430.310 49.030 430.820 ;
        RECT 49.850 430.310 49.990 430.820 ;
        RECT 50.810 430.310 50.950 430.820 ;
        RECT 51.770 430.310 51.910 430.820 ;
        RECT 52.730 430.310 52.870 430.820 ;
        RECT 53.690 430.310 53.830 430.820 ;
        RECT 54.650 430.310 54.790 430.820 ;
        RECT 55.610 430.310 55.750 430.820 ;
        RECT 56.570 430.310 56.710 430.820 ;
        RECT 57.530 430.310 57.670 430.820 ;
        RECT 58.490 430.310 58.630 430.820 ;
        RECT 59.450 430.310 59.590 430.820 ;
        RECT 60.410 430.310 60.550 430.820 ;
        RECT 61.370 430.310 61.510 430.820 ;
        RECT 62.330 430.310 62.470 430.820 ;
        RECT 63.290 430.310 63.430 430.820 ;
        RECT 64.250 430.310 64.390 430.820 ;
        RECT 65.210 430.310 65.350 430.820 ;
        RECT 66.170 430.310 66.310 430.820 ;
        RECT 67.130 430.310 67.270 430.820 ;
        RECT 68.090 430.310 68.230 430.820 ;
        RECT 69.050 430.310 69.190 430.820 ;
        RECT 70.010 430.310 70.150 430.820 ;
        RECT 70.970 430.310 71.110 430.820 ;
        RECT 71.930 430.310 72.070 430.820 ;
        RECT 72.890 430.310 73.030 430.820 ;
        RECT 73.850 430.310 73.990 430.820 ;
        RECT 74.810 430.310 74.950 430.820 ;
        RECT 75.770 430.310 75.910 430.820 ;
        RECT 76.730 430.310 76.870 430.820 ;
        RECT 77.690 430.310 77.830 430.820 ;
        RECT 78.650 430.310 78.790 430.820 ;
        RECT 79.610 430.310 79.750 430.820 ;
        RECT 80.570 430.310 80.710 430.820 ;
        RECT 81.530 430.310 81.670 430.820 ;
        RECT 82.490 430.310 82.630 430.820 ;
        RECT 83.450 430.310 83.590 430.820 ;
        RECT 84.410 430.310 84.550 430.820 ;
        RECT 85.370 430.310 85.510 430.820 ;
        RECT 86.330 430.310 86.470 430.820 ;
        RECT 87.290 430.310 87.430 430.820 ;
        RECT 88.250 430.310 88.390 430.820 ;
        RECT 89.210 430.310 89.350 430.820 ;
        RECT 90.170 430.310 90.310 430.820 ;
        RECT 91.130 430.310 91.270 430.820 ;
        RECT 92.090 430.310 92.230 430.820 ;
        RECT 93.050 430.310 93.190 430.820 ;
        RECT 94.010 430.310 94.150 430.820 ;
        RECT 94.970 430.310 95.110 430.820 ;
        RECT 95.930 430.310 96.070 430.820 ;
        RECT 96.890 430.310 97.030 430.820 ;
        RECT 97.850 430.310 97.990 430.820 ;
        RECT 98.810 430.310 109.065 430.820 ;
        RECT 0.375 0.610 109.065 430.310 ;
        RECT 0.375 0.400 9.670 0.610 ;
        RECT 10.490 0.400 10.630 0.610 ;
        RECT 11.450 0.400 11.590 0.610 ;
        RECT 12.410 0.400 12.550 0.610 ;
        RECT 13.370 0.400 13.510 0.610 ;
        RECT 14.330 0.400 14.470 0.610 ;
        RECT 15.290 0.400 15.430 0.610 ;
        RECT 16.250 0.400 16.390 0.610 ;
        RECT 17.210 0.400 17.350 0.610 ;
        RECT 18.170 0.400 18.310 0.610 ;
        RECT 19.130 0.400 19.270 0.610 ;
        RECT 20.090 0.400 20.230 0.610 ;
        RECT 21.050 0.400 21.190 0.610 ;
        RECT 22.010 0.400 22.150 0.610 ;
        RECT 22.970 0.400 23.110 0.610 ;
        RECT 23.930 0.400 24.070 0.610 ;
        RECT 24.890 0.400 25.030 0.610 ;
        RECT 25.850 0.400 25.990 0.610 ;
        RECT 26.810 0.400 26.950 0.610 ;
        RECT 27.770 0.400 27.910 0.610 ;
        RECT 28.730 0.400 28.870 0.610 ;
        RECT 29.690 0.400 29.830 0.610 ;
        RECT 30.650 0.400 30.790 0.610 ;
        RECT 31.610 0.400 31.750 0.610 ;
        RECT 32.570 0.400 32.710 0.610 ;
        RECT 33.530 0.400 33.670 0.610 ;
        RECT 34.490 0.400 34.630 0.610 ;
        RECT 35.450 0.400 35.590 0.610 ;
        RECT 36.410 0.400 36.550 0.610 ;
        RECT 37.370 0.400 37.510 0.610 ;
        RECT 38.330 0.400 38.470 0.610 ;
        RECT 39.290 0.400 39.430 0.610 ;
        RECT 40.250 0.400 40.390 0.610 ;
        RECT 41.210 0.400 41.350 0.610 ;
        RECT 42.170 0.400 42.310 0.610 ;
        RECT 43.130 0.400 43.270 0.610 ;
        RECT 44.090 0.400 44.230 0.610 ;
        RECT 45.050 0.400 45.190 0.610 ;
        RECT 46.010 0.400 46.150 0.610 ;
        RECT 46.970 0.400 47.110 0.610 ;
        RECT 47.930 0.400 48.070 0.610 ;
        RECT 48.890 0.400 49.030 0.610 ;
        RECT 49.850 0.400 49.990 0.610 ;
        RECT 50.810 0.400 50.950 0.610 ;
        RECT 51.770 0.400 51.910 0.610 ;
        RECT 52.730 0.400 52.870 0.610 ;
        RECT 53.690 0.400 53.830 0.610 ;
        RECT 54.650 0.400 54.790 0.610 ;
        RECT 55.610 0.400 55.750 0.610 ;
        RECT 56.570 0.400 56.710 0.610 ;
        RECT 57.530 0.400 57.670 0.610 ;
        RECT 58.490 0.400 58.630 0.610 ;
        RECT 59.450 0.400 59.590 0.610 ;
        RECT 60.410 0.400 60.550 0.610 ;
        RECT 61.370 0.400 61.510 0.610 ;
        RECT 62.330 0.400 62.470 0.610 ;
        RECT 63.290 0.400 63.430 0.610 ;
        RECT 64.250 0.400 64.390 0.610 ;
        RECT 65.210 0.400 65.350 0.610 ;
        RECT 66.170 0.400 66.310 0.610 ;
        RECT 67.130 0.400 67.270 0.610 ;
        RECT 68.090 0.400 68.230 0.610 ;
        RECT 69.050 0.400 69.190 0.610 ;
        RECT 70.010 0.400 70.150 0.610 ;
        RECT 70.970 0.400 71.110 0.610 ;
        RECT 71.930 0.400 72.070 0.610 ;
        RECT 72.890 0.400 73.030 0.610 ;
        RECT 73.850 0.400 73.990 0.610 ;
        RECT 74.810 0.400 74.950 0.610 ;
        RECT 75.770 0.400 75.910 0.610 ;
        RECT 76.730 0.400 76.870 0.610 ;
        RECT 77.690 0.400 77.830 0.610 ;
        RECT 78.650 0.400 78.790 0.610 ;
        RECT 79.610 0.400 79.750 0.610 ;
        RECT 80.570 0.400 80.710 0.610 ;
        RECT 81.530 0.400 81.670 0.610 ;
        RECT 82.490 0.400 82.630 0.610 ;
        RECT 83.450 0.400 83.590 0.610 ;
        RECT 84.410 0.400 84.550 0.610 ;
        RECT 85.370 0.400 85.510 0.610 ;
        RECT 86.330 0.400 86.470 0.610 ;
        RECT 87.290 0.400 87.430 0.610 ;
        RECT 88.250 0.400 88.390 0.610 ;
        RECT 89.210 0.400 89.350 0.610 ;
        RECT 90.170 0.400 90.310 0.610 ;
        RECT 91.130 0.400 91.270 0.610 ;
        RECT 92.090 0.400 92.230 0.610 ;
        RECT 93.050 0.400 93.190 0.610 ;
        RECT 94.010 0.400 94.150 0.610 ;
        RECT 94.970 0.400 95.110 0.610 ;
        RECT 95.930 0.400 96.070 0.610 ;
        RECT 96.890 0.400 97.030 0.610 ;
        RECT 97.850 0.400 97.990 0.610 ;
        RECT 98.810 0.400 109.065 0.610 ;
      LAYER Metal3 ;
        RECT 0.335 429.650 109.340 429.760 ;
        RECT 0.610 428.830 109.340 429.650 ;
        RECT 0.335 427.970 109.340 428.830 ;
        RECT 0.610 427.150 109.340 427.970 ;
        RECT 0.335 426.290 109.340 427.150 ;
        RECT 0.610 425.470 109.340 426.290 ;
        RECT 0.335 424.610 109.340 425.470 ;
        RECT 0.610 424.190 109.340 424.610 ;
        RECT 0.610 423.790 108.830 424.190 ;
        RECT 0.335 423.370 108.830 423.790 ;
        RECT 0.335 422.930 109.340 423.370 ;
        RECT 0.610 422.110 109.340 422.930 ;
        RECT 0.335 421.250 109.340 422.110 ;
        RECT 0.610 420.430 109.340 421.250 ;
        RECT 0.335 419.990 109.340 420.430 ;
        RECT 0.335 419.570 108.830 419.990 ;
        RECT 0.610 419.170 108.830 419.570 ;
        RECT 0.610 418.750 109.340 419.170 ;
        RECT 0.335 417.890 109.340 418.750 ;
        RECT 0.610 417.070 109.340 417.890 ;
        RECT 0.335 416.210 109.340 417.070 ;
        RECT 0.610 415.790 109.340 416.210 ;
        RECT 0.610 415.390 108.830 415.790 ;
        RECT 0.335 414.970 108.830 415.390 ;
        RECT 0.335 414.530 109.340 414.970 ;
        RECT 0.610 413.710 109.340 414.530 ;
        RECT 0.335 412.850 109.340 413.710 ;
        RECT 0.610 412.030 109.340 412.850 ;
        RECT 0.335 411.590 109.340 412.030 ;
        RECT 0.335 411.170 108.830 411.590 ;
        RECT 0.610 410.770 108.830 411.170 ;
        RECT 0.610 410.350 109.340 410.770 ;
        RECT 0.335 409.490 109.340 410.350 ;
        RECT 0.610 408.670 109.340 409.490 ;
        RECT 0.335 407.810 109.340 408.670 ;
        RECT 0.610 407.390 109.340 407.810 ;
        RECT 0.610 406.990 108.830 407.390 ;
        RECT 0.335 406.570 108.830 406.990 ;
        RECT 0.335 406.130 109.340 406.570 ;
        RECT 0.610 405.310 109.340 406.130 ;
        RECT 0.335 404.450 109.340 405.310 ;
        RECT 0.610 403.630 109.340 404.450 ;
        RECT 0.335 403.190 109.340 403.630 ;
        RECT 0.335 402.770 108.830 403.190 ;
        RECT 0.610 402.370 108.830 402.770 ;
        RECT 0.610 401.950 109.340 402.370 ;
        RECT 0.335 401.090 109.340 401.950 ;
        RECT 0.610 400.270 109.340 401.090 ;
        RECT 0.335 399.410 109.340 400.270 ;
        RECT 0.610 398.990 109.340 399.410 ;
        RECT 0.610 398.590 108.830 398.990 ;
        RECT 0.335 398.170 108.830 398.590 ;
        RECT 0.335 397.730 109.340 398.170 ;
        RECT 0.610 396.910 109.340 397.730 ;
        RECT 0.335 396.050 109.340 396.910 ;
        RECT 0.610 395.230 109.340 396.050 ;
        RECT 0.335 394.790 109.340 395.230 ;
        RECT 0.335 394.370 108.830 394.790 ;
        RECT 0.610 393.970 108.830 394.370 ;
        RECT 0.610 393.550 109.340 393.970 ;
        RECT 0.335 392.690 109.340 393.550 ;
        RECT 0.610 391.870 109.340 392.690 ;
        RECT 0.335 391.010 109.340 391.870 ;
        RECT 0.610 390.590 109.340 391.010 ;
        RECT 0.610 390.190 108.830 390.590 ;
        RECT 0.335 389.770 108.830 390.190 ;
        RECT 0.335 389.330 109.340 389.770 ;
        RECT 0.610 388.510 109.340 389.330 ;
        RECT 0.335 387.650 109.340 388.510 ;
        RECT 0.610 386.830 109.340 387.650 ;
        RECT 0.335 386.390 109.340 386.830 ;
        RECT 0.335 385.970 108.830 386.390 ;
        RECT 0.610 385.570 108.830 385.970 ;
        RECT 0.610 385.150 109.340 385.570 ;
        RECT 0.335 384.290 109.340 385.150 ;
        RECT 0.610 383.470 109.340 384.290 ;
        RECT 0.335 382.610 109.340 383.470 ;
        RECT 0.610 382.190 109.340 382.610 ;
        RECT 0.610 381.790 108.830 382.190 ;
        RECT 0.335 381.370 108.830 381.790 ;
        RECT 0.335 380.930 109.340 381.370 ;
        RECT 0.610 380.110 109.340 380.930 ;
        RECT 0.335 379.250 109.340 380.110 ;
        RECT 0.610 378.430 109.340 379.250 ;
        RECT 0.335 377.990 109.340 378.430 ;
        RECT 0.335 377.570 108.830 377.990 ;
        RECT 0.610 377.170 108.830 377.570 ;
        RECT 0.610 376.750 109.340 377.170 ;
        RECT 0.335 375.890 109.340 376.750 ;
        RECT 0.610 375.070 109.340 375.890 ;
        RECT 0.335 374.210 109.340 375.070 ;
        RECT 0.610 373.790 109.340 374.210 ;
        RECT 0.610 373.390 108.830 373.790 ;
        RECT 0.335 372.970 108.830 373.390 ;
        RECT 0.335 372.530 109.340 372.970 ;
        RECT 0.610 371.710 109.340 372.530 ;
        RECT 0.335 370.850 109.340 371.710 ;
        RECT 0.610 370.030 109.340 370.850 ;
        RECT 0.335 369.590 109.340 370.030 ;
        RECT 0.335 369.170 108.830 369.590 ;
        RECT 0.610 368.770 108.830 369.170 ;
        RECT 0.610 368.350 109.340 368.770 ;
        RECT 0.335 367.490 109.340 368.350 ;
        RECT 0.610 366.670 109.340 367.490 ;
        RECT 0.335 365.810 109.340 366.670 ;
        RECT 0.610 365.390 109.340 365.810 ;
        RECT 0.610 364.990 108.830 365.390 ;
        RECT 0.335 364.570 108.830 364.990 ;
        RECT 0.335 364.130 109.340 364.570 ;
        RECT 0.610 363.310 109.340 364.130 ;
        RECT 0.335 362.450 109.340 363.310 ;
        RECT 0.610 361.630 109.340 362.450 ;
        RECT 0.335 361.190 109.340 361.630 ;
        RECT 0.335 360.770 108.830 361.190 ;
        RECT 0.610 360.370 108.830 360.770 ;
        RECT 0.610 359.950 109.340 360.370 ;
        RECT 0.335 359.090 109.340 359.950 ;
        RECT 0.610 358.270 109.340 359.090 ;
        RECT 0.335 357.410 109.340 358.270 ;
        RECT 0.610 356.990 109.340 357.410 ;
        RECT 0.610 356.590 108.830 356.990 ;
        RECT 0.335 356.170 108.830 356.590 ;
        RECT 0.335 355.730 109.340 356.170 ;
        RECT 0.610 354.910 109.340 355.730 ;
        RECT 0.335 354.050 109.340 354.910 ;
        RECT 0.610 353.230 109.340 354.050 ;
        RECT 0.335 352.790 109.340 353.230 ;
        RECT 0.335 352.370 108.830 352.790 ;
        RECT 0.610 351.970 108.830 352.370 ;
        RECT 0.610 351.550 109.340 351.970 ;
        RECT 0.335 350.690 109.340 351.550 ;
        RECT 0.610 349.870 109.340 350.690 ;
        RECT 0.335 349.010 109.340 349.870 ;
        RECT 0.610 348.590 109.340 349.010 ;
        RECT 0.610 348.190 108.830 348.590 ;
        RECT 0.335 347.770 108.830 348.190 ;
        RECT 0.335 347.330 109.340 347.770 ;
        RECT 0.610 346.510 109.340 347.330 ;
        RECT 0.335 345.650 109.340 346.510 ;
        RECT 0.610 344.830 109.340 345.650 ;
        RECT 0.335 344.390 109.340 344.830 ;
        RECT 0.335 343.970 108.830 344.390 ;
        RECT 0.610 343.570 108.830 343.970 ;
        RECT 0.610 343.150 109.340 343.570 ;
        RECT 0.335 342.290 109.340 343.150 ;
        RECT 0.610 341.470 109.340 342.290 ;
        RECT 0.335 340.610 109.340 341.470 ;
        RECT 0.610 340.190 109.340 340.610 ;
        RECT 0.610 339.790 108.830 340.190 ;
        RECT 0.335 339.370 108.830 339.790 ;
        RECT 0.335 338.930 109.340 339.370 ;
        RECT 0.610 338.110 109.340 338.930 ;
        RECT 0.335 337.250 109.340 338.110 ;
        RECT 0.610 336.430 109.340 337.250 ;
        RECT 0.335 335.990 109.340 336.430 ;
        RECT 0.335 335.570 108.830 335.990 ;
        RECT 0.610 335.170 108.830 335.570 ;
        RECT 0.610 334.750 109.340 335.170 ;
        RECT 0.335 333.890 109.340 334.750 ;
        RECT 0.610 333.070 109.340 333.890 ;
        RECT 0.335 332.210 109.340 333.070 ;
        RECT 0.610 331.790 109.340 332.210 ;
        RECT 0.610 331.390 108.830 331.790 ;
        RECT 0.335 330.970 108.830 331.390 ;
        RECT 0.335 330.530 109.340 330.970 ;
        RECT 0.610 329.710 109.340 330.530 ;
        RECT 0.335 328.850 109.340 329.710 ;
        RECT 0.610 328.030 109.340 328.850 ;
        RECT 0.335 327.590 109.340 328.030 ;
        RECT 0.335 327.170 108.830 327.590 ;
        RECT 0.610 326.770 108.830 327.170 ;
        RECT 0.610 326.350 109.340 326.770 ;
        RECT 0.335 325.490 109.340 326.350 ;
        RECT 0.610 324.670 109.340 325.490 ;
        RECT 0.335 323.810 109.340 324.670 ;
        RECT 0.610 323.390 109.340 323.810 ;
        RECT 0.610 322.990 108.830 323.390 ;
        RECT 0.335 322.570 108.830 322.990 ;
        RECT 0.335 322.130 109.340 322.570 ;
        RECT 0.610 321.310 109.340 322.130 ;
        RECT 0.335 320.450 109.340 321.310 ;
        RECT 0.610 319.630 109.340 320.450 ;
        RECT 0.335 319.190 109.340 319.630 ;
        RECT 0.335 318.770 108.830 319.190 ;
        RECT 0.610 318.370 108.830 318.770 ;
        RECT 0.610 317.950 109.340 318.370 ;
        RECT 0.335 317.090 109.340 317.950 ;
        RECT 0.610 316.270 109.340 317.090 ;
        RECT 0.335 315.410 109.340 316.270 ;
        RECT 0.610 314.990 109.340 315.410 ;
        RECT 0.610 314.590 108.830 314.990 ;
        RECT 0.335 314.170 108.830 314.590 ;
        RECT 0.335 313.730 109.340 314.170 ;
        RECT 0.610 312.910 109.340 313.730 ;
        RECT 0.335 312.050 109.340 312.910 ;
        RECT 0.610 311.230 109.340 312.050 ;
        RECT 0.335 310.790 109.340 311.230 ;
        RECT 0.335 310.370 108.830 310.790 ;
        RECT 0.610 309.970 108.830 310.370 ;
        RECT 0.610 309.550 109.340 309.970 ;
        RECT 0.335 308.690 109.340 309.550 ;
        RECT 0.610 307.870 109.340 308.690 ;
        RECT 0.335 307.010 109.340 307.870 ;
        RECT 0.610 306.590 109.340 307.010 ;
        RECT 0.610 306.190 108.830 306.590 ;
        RECT 0.335 305.770 108.830 306.190 ;
        RECT 0.335 305.330 109.340 305.770 ;
        RECT 0.610 304.510 109.340 305.330 ;
        RECT 0.335 303.650 109.340 304.510 ;
        RECT 0.610 302.830 109.340 303.650 ;
        RECT 0.335 302.390 109.340 302.830 ;
        RECT 0.335 301.970 108.830 302.390 ;
        RECT 0.610 301.570 108.830 301.970 ;
        RECT 0.610 301.150 109.340 301.570 ;
        RECT 0.335 300.290 109.340 301.150 ;
        RECT 0.610 299.470 109.340 300.290 ;
        RECT 0.335 298.610 109.340 299.470 ;
        RECT 0.610 298.190 109.340 298.610 ;
        RECT 0.610 297.790 108.830 298.190 ;
        RECT 0.335 297.370 108.830 297.790 ;
        RECT 0.335 296.930 109.340 297.370 ;
        RECT 0.610 296.110 109.340 296.930 ;
        RECT 0.335 295.250 109.340 296.110 ;
        RECT 0.610 294.430 109.340 295.250 ;
        RECT 0.335 293.990 109.340 294.430 ;
        RECT 0.335 293.570 108.830 293.990 ;
        RECT 0.610 293.170 108.830 293.570 ;
        RECT 0.610 292.750 109.340 293.170 ;
        RECT 0.335 291.890 109.340 292.750 ;
        RECT 0.610 291.070 109.340 291.890 ;
        RECT 0.335 290.210 109.340 291.070 ;
        RECT 0.610 289.390 109.340 290.210 ;
        RECT 0.335 288.530 109.340 289.390 ;
        RECT 0.610 287.710 109.340 288.530 ;
        RECT 0.335 286.850 109.340 287.710 ;
        RECT 0.610 286.030 109.340 286.850 ;
        RECT 0.335 285.170 109.340 286.030 ;
        RECT 0.610 284.350 109.340 285.170 ;
        RECT 0.335 283.490 109.340 284.350 ;
        RECT 0.610 282.670 109.340 283.490 ;
        RECT 0.335 281.810 109.340 282.670 ;
        RECT 0.610 280.990 109.340 281.810 ;
        RECT 0.335 280.550 109.340 280.990 ;
        RECT 0.335 280.130 108.830 280.550 ;
        RECT 0.610 279.730 108.830 280.130 ;
        RECT 0.610 279.310 109.340 279.730 ;
        RECT 0.335 278.450 109.340 279.310 ;
        RECT 0.610 277.630 109.340 278.450 ;
        RECT 0.335 276.770 109.340 277.630 ;
        RECT 0.610 276.350 109.340 276.770 ;
        RECT 0.610 275.950 108.830 276.350 ;
        RECT 0.335 275.530 108.830 275.950 ;
        RECT 0.335 275.090 109.340 275.530 ;
        RECT 0.610 274.270 109.340 275.090 ;
        RECT 0.335 273.410 109.340 274.270 ;
        RECT 0.610 272.590 109.340 273.410 ;
        RECT 0.335 272.150 109.340 272.590 ;
        RECT 0.335 271.730 108.830 272.150 ;
        RECT 0.610 271.330 108.830 271.730 ;
        RECT 0.610 270.910 109.340 271.330 ;
        RECT 0.335 270.050 109.340 270.910 ;
        RECT 0.610 269.230 109.340 270.050 ;
        RECT 0.335 268.370 109.340 269.230 ;
        RECT 0.610 267.950 109.340 268.370 ;
        RECT 0.610 267.550 108.830 267.950 ;
        RECT 0.335 267.130 108.830 267.550 ;
        RECT 0.335 266.690 109.340 267.130 ;
        RECT 0.610 265.870 109.340 266.690 ;
        RECT 0.335 265.010 109.340 265.870 ;
        RECT 0.610 264.190 109.340 265.010 ;
        RECT 0.335 263.750 109.340 264.190 ;
        RECT 0.335 263.330 108.830 263.750 ;
        RECT 0.610 262.930 108.830 263.330 ;
        RECT 0.610 262.510 109.340 262.930 ;
        RECT 0.335 261.650 109.340 262.510 ;
        RECT 0.610 260.830 109.340 261.650 ;
        RECT 0.335 259.970 109.340 260.830 ;
        RECT 0.610 259.550 109.340 259.970 ;
        RECT 0.610 259.150 108.830 259.550 ;
        RECT 0.335 258.730 108.830 259.150 ;
        RECT 0.335 258.290 109.340 258.730 ;
        RECT 0.610 257.470 109.340 258.290 ;
        RECT 0.335 256.610 109.340 257.470 ;
        RECT 0.610 255.790 109.340 256.610 ;
        RECT 0.335 255.350 109.340 255.790 ;
        RECT 0.335 254.930 108.830 255.350 ;
        RECT 0.610 254.530 108.830 254.930 ;
        RECT 0.610 254.110 109.340 254.530 ;
        RECT 0.335 253.250 109.340 254.110 ;
        RECT 0.610 252.430 109.340 253.250 ;
        RECT 0.335 251.570 109.340 252.430 ;
        RECT 0.610 251.150 109.340 251.570 ;
        RECT 0.610 250.750 108.830 251.150 ;
        RECT 0.335 250.330 108.830 250.750 ;
        RECT 0.335 249.890 109.340 250.330 ;
        RECT 0.610 249.070 109.340 249.890 ;
        RECT 0.335 248.210 109.340 249.070 ;
        RECT 0.610 247.390 109.340 248.210 ;
        RECT 0.335 246.950 109.340 247.390 ;
        RECT 0.335 246.530 108.830 246.950 ;
        RECT 0.610 246.130 108.830 246.530 ;
        RECT 0.610 245.710 109.340 246.130 ;
        RECT 0.335 244.850 109.340 245.710 ;
        RECT 0.610 244.030 109.340 244.850 ;
        RECT 0.335 243.170 109.340 244.030 ;
        RECT 0.610 242.750 109.340 243.170 ;
        RECT 0.610 242.350 108.830 242.750 ;
        RECT 0.335 241.930 108.830 242.350 ;
        RECT 0.335 241.490 109.340 241.930 ;
        RECT 0.610 240.670 109.340 241.490 ;
        RECT 0.335 239.810 109.340 240.670 ;
        RECT 0.610 238.990 109.340 239.810 ;
        RECT 0.335 238.550 109.340 238.990 ;
        RECT 0.335 238.130 108.830 238.550 ;
        RECT 0.610 237.730 108.830 238.130 ;
        RECT 0.610 237.310 109.340 237.730 ;
        RECT 0.335 236.450 109.340 237.310 ;
        RECT 0.610 235.630 109.340 236.450 ;
        RECT 0.335 234.770 109.340 235.630 ;
        RECT 0.610 234.350 109.340 234.770 ;
        RECT 0.610 233.950 108.830 234.350 ;
        RECT 0.335 233.530 108.830 233.950 ;
        RECT 0.335 233.090 109.340 233.530 ;
        RECT 0.610 232.270 109.340 233.090 ;
        RECT 0.335 231.410 109.340 232.270 ;
        RECT 0.610 230.590 109.340 231.410 ;
        RECT 0.335 230.150 109.340 230.590 ;
        RECT 0.335 229.730 108.830 230.150 ;
        RECT 0.610 229.330 108.830 229.730 ;
        RECT 0.610 228.910 109.340 229.330 ;
        RECT 0.335 228.050 109.340 228.910 ;
        RECT 0.610 227.230 109.340 228.050 ;
        RECT 0.335 226.370 109.340 227.230 ;
        RECT 0.610 225.950 109.340 226.370 ;
        RECT 0.610 225.550 108.830 225.950 ;
        RECT 0.335 225.130 108.830 225.550 ;
        RECT 0.335 224.690 109.340 225.130 ;
        RECT 0.610 223.870 109.340 224.690 ;
        RECT 0.335 223.010 109.340 223.870 ;
        RECT 0.610 222.190 109.340 223.010 ;
        RECT 0.335 221.750 109.340 222.190 ;
        RECT 0.335 221.330 108.830 221.750 ;
        RECT 0.610 220.930 108.830 221.330 ;
        RECT 0.610 220.510 109.340 220.930 ;
        RECT 0.335 219.650 109.340 220.510 ;
        RECT 0.610 218.830 109.340 219.650 ;
        RECT 0.335 217.970 109.340 218.830 ;
        RECT 0.610 217.550 109.340 217.970 ;
        RECT 0.610 217.150 108.830 217.550 ;
        RECT 0.335 216.730 108.830 217.150 ;
        RECT 0.335 216.290 109.340 216.730 ;
        RECT 0.610 215.470 109.340 216.290 ;
        RECT 0.335 214.190 109.340 215.470 ;
        RECT 0.610 213.370 109.340 214.190 ;
        RECT 0.335 213.350 109.340 213.370 ;
        RECT 0.335 212.530 108.830 213.350 ;
        RECT 0.335 212.510 109.340 212.530 ;
        RECT 0.610 211.690 109.340 212.510 ;
        RECT 0.335 210.830 109.340 211.690 ;
        RECT 0.610 210.010 109.340 210.830 ;
        RECT 0.335 209.150 109.340 210.010 ;
        RECT 0.610 208.330 108.830 209.150 ;
        RECT 0.335 207.470 109.340 208.330 ;
        RECT 0.610 206.650 109.340 207.470 ;
        RECT 0.335 205.790 109.340 206.650 ;
        RECT 0.610 204.970 109.340 205.790 ;
        RECT 0.335 204.950 109.340 204.970 ;
        RECT 0.335 204.130 108.830 204.950 ;
        RECT 0.335 204.110 109.340 204.130 ;
        RECT 0.610 203.290 109.340 204.110 ;
        RECT 0.335 202.430 109.340 203.290 ;
        RECT 0.610 201.610 109.340 202.430 ;
        RECT 0.335 200.750 109.340 201.610 ;
        RECT 0.610 199.930 108.830 200.750 ;
        RECT 0.335 199.070 109.340 199.930 ;
        RECT 0.610 198.250 109.340 199.070 ;
        RECT 0.335 197.390 109.340 198.250 ;
        RECT 0.610 196.570 109.340 197.390 ;
        RECT 0.335 196.550 109.340 196.570 ;
        RECT 0.335 195.730 108.830 196.550 ;
        RECT 0.335 195.710 109.340 195.730 ;
        RECT 0.610 194.890 109.340 195.710 ;
        RECT 0.335 194.030 109.340 194.890 ;
        RECT 0.610 193.210 109.340 194.030 ;
        RECT 0.335 192.350 109.340 193.210 ;
        RECT 0.610 191.530 108.830 192.350 ;
        RECT 0.335 190.670 109.340 191.530 ;
        RECT 0.610 189.850 109.340 190.670 ;
        RECT 0.335 188.990 109.340 189.850 ;
        RECT 0.610 188.170 109.340 188.990 ;
        RECT 0.335 188.150 109.340 188.170 ;
        RECT 0.335 187.330 108.830 188.150 ;
        RECT 0.335 187.310 109.340 187.330 ;
        RECT 0.610 186.490 109.340 187.310 ;
        RECT 0.335 185.630 109.340 186.490 ;
        RECT 0.610 184.810 109.340 185.630 ;
        RECT 0.335 183.950 109.340 184.810 ;
        RECT 0.610 183.130 108.830 183.950 ;
        RECT 0.335 182.270 109.340 183.130 ;
        RECT 0.610 181.450 109.340 182.270 ;
        RECT 0.335 180.590 109.340 181.450 ;
        RECT 0.610 179.770 109.340 180.590 ;
        RECT 0.335 179.750 109.340 179.770 ;
        RECT 0.335 178.930 108.830 179.750 ;
        RECT 0.335 178.910 109.340 178.930 ;
        RECT 0.610 178.090 109.340 178.910 ;
        RECT 0.335 177.230 109.340 178.090 ;
        RECT 0.610 176.410 109.340 177.230 ;
        RECT 0.335 175.550 109.340 176.410 ;
        RECT 0.610 174.730 108.830 175.550 ;
        RECT 0.335 173.870 109.340 174.730 ;
        RECT 0.610 173.050 109.340 173.870 ;
        RECT 0.335 172.190 109.340 173.050 ;
        RECT 0.610 171.370 109.340 172.190 ;
        RECT 0.335 171.350 109.340 171.370 ;
        RECT 0.335 170.530 108.830 171.350 ;
        RECT 0.335 170.510 109.340 170.530 ;
        RECT 0.610 169.690 109.340 170.510 ;
        RECT 0.335 168.830 109.340 169.690 ;
        RECT 0.610 168.010 109.340 168.830 ;
        RECT 0.335 167.150 109.340 168.010 ;
        RECT 0.610 166.330 108.830 167.150 ;
        RECT 0.335 165.470 109.340 166.330 ;
        RECT 0.610 164.650 109.340 165.470 ;
        RECT 0.335 163.790 109.340 164.650 ;
        RECT 0.610 162.970 109.340 163.790 ;
        RECT 0.335 162.950 109.340 162.970 ;
        RECT 0.335 162.130 108.830 162.950 ;
        RECT 0.335 162.110 109.340 162.130 ;
        RECT 0.610 161.290 109.340 162.110 ;
        RECT 0.335 160.430 109.340 161.290 ;
        RECT 0.610 159.610 109.340 160.430 ;
        RECT 0.335 158.750 109.340 159.610 ;
        RECT 0.610 157.930 108.830 158.750 ;
        RECT 0.335 157.070 109.340 157.930 ;
        RECT 0.610 156.250 109.340 157.070 ;
        RECT 0.335 155.390 109.340 156.250 ;
        RECT 0.610 154.570 109.340 155.390 ;
        RECT 0.335 154.550 109.340 154.570 ;
        RECT 0.335 153.730 108.830 154.550 ;
        RECT 0.335 153.710 109.340 153.730 ;
        RECT 0.610 152.890 109.340 153.710 ;
        RECT 0.335 152.030 109.340 152.890 ;
        RECT 0.610 151.210 109.340 152.030 ;
        RECT 0.335 150.350 109.340 151.210 ;
        RECT 0.610 149.530 108.830 150.350 ;
        RECT 0.335 148.670 109.340 149.530 ;
        RECT 0.610 147.850 109.340 148.670 ;
        RECT 0.335 146.990 109.340 147.850 ;
        RECT 0.610 146.170 109.340 146.990 ;
        RECT 0.335 145.310 109.340 146.170 ;
        RECT 0.610 144.490 109.340 145.310 ;
        RECT 0.335 143.630 109.340 144.490 ;
        RECT 0.610 142.810 109.340 143.630 ;
        RECT 0.335 141.950 109.340 142.810 ;
        RECT 0.610 141.130 109.340 141.950 ;
        RECT 0.335 140.270 109.340 141.130 ;
        RECT 0.610 139.450 109.340 140.270 ;
        RECT 0.335 138.590 109.340 139.450 ;
        RECT 0.610 137.770 109.340 138.590 ;
        RECT 0.335 136.910 109.340 137.770 ;
        RECT 0.610 136.090 109.340 136.910 ;
        RECT 0.335 135.230 109.340 136.090 ;
        RECT 0.610 134.410 109.340 135.230 ;
        RECT 0.335 133.550 109.340 134.410 ;
        RECT 0.610 132.730 109.340 133.550 ;
        RECT 0.335 131.870 109.340 132.730 ;
        RECT 0.610 131.050 109.340 131.870 ;
        RECT 0.335 130.190 109.340 131.050 ;
        RECT 0.610 129.370 109.340 130.190 ;
        RECT 0.335 128.510 109.340 129.370 ;
        RECT 0.610 127.690 109.340 128.510 ;
        RECT 0.335 126.830 109.340 127.690 ;
        RECT 0.610 126.010 109.340 126.830 ;
        RECT 0.335 125.150 109.340 126.010 ;
        RECT 0.610 124.330 109.340 125.150 ;
        RECT 0.335 123.470 109.340 124.330 ;
        RECT 0.610 122.650 109.340 123.470 ;
        RECT 0.335 121.790 109.340 122.650 ;
        RECT 0.610 120.970 109.340 121.790 ;
        RECT 0.335 120.110 109.340 120.970 ;
        RECT 0.610 119.290 109.340 120.110 ;
        RECT 0.335 119.270 109.340 119.290 ;
        RECT 0.335 118.450 108.830 119.270 ;
        RECT 0.335 118.430 109.340 118.450 ;
        RECT 0.610 117.610 108.830 118.430 ;
        RECT 0.335 117.590 109.340 117.610 ;
        RECT 0.335 116.770 108.830 117.590 ;
        RECT 0.335 116.750 109.340 116.770 ;
        RECT 0.610 115.930 108.830 116.750 ;
        RECT 0.335 115.910 109.340 115.930 ;
        RECT 0.335 115.090 108.830 115.910 ;
        RECT 0.335 115.070 109.340 115.090 ;
        RECT 0.610 114.250 108.830 115.070 ;
        RECT 0.335 114.230 109.340 114.250 ;
        RECT 0.335 113.410 108.830 114.230 ;
        RECT 0.335 113.390 109.340 113.410 ;
        RECT 0.610 112.570 108.830 113.390 ;
        RECT 0.335 112.550 109.340 112.570 ;
        RECT 0.335 111.730 108.830 112.550 ;
        RECT 0.335 111.710 109.340 111.730 ;
        RECT 0.610 110.890 108.830 111.710 ;
        RECT 0.335 110.870 109.340 110.890 ;
        RECT 0.335 110.050 108.830 110.870 ;
        RECT 0.335 110.030 109.340 110.050 ;
        RECT 0.610 109.210 108.830 110.030 ;
        RECT 0.335 109.190 109.340 109.210 ;
        RECT 0.335 108.370 108.830 109.190 ;
        RECT 0.335 108.350 109.340 108.370 ;
        RECT 0.610 107.530 108.830 108.350 ;
        RECT 0.335 107.510 109.340 107.530 ;
        RECT 0.335 106.690 108.830 107.510 ;
        RECT 0.335 106.670 109.340 106.690 ;
        RECT 0.610 105.850 108.830 106.670 ;
        RECT 0.335 105.830 109.340 105.850 ;
        RECT 0.335 105.010 108.830 105.830 ;
        RECT 0.335 104.990 109.340 105.010 ;
        RECT 0.610 104.170 108.830 104.990 ;
        RECT 0.335 104.150 109.340 104.170 ;
        RECT 0.335 103.330 108.830 104.150 ;
        RECT 0.335 103.310 109.340 103.330 ;
        RECT 0.610 102.490 108.830 103.310 ;
        RECT 0.335 102.470 109.340 102.490 ;
        RECT 0.335 101.650 108.830 102.470 ;
        RECT 0.335 101.630 109.340 101.650 ;
        RECT 0.610 100.810 108.830 101.630 ;
        RECT 0.335 100.790 109.340 100.810 ;
        RECT 0.335 99.970 108.830 100.790 ;
        RECT 0.335 99.950 109.340 99.970 ;
        RECT 0.610 99.130 108.830 99.950 ;
        RECT 0.335 99.110 109.340 99.130 ;
        RECT 0.335 98.290 108.830 99.110 ;
        RECT 0.335 98.270 109.340 98.290 ;
        RECT 0.610 97.450 108.830 98.270 ;
        RECT 0.335 97.430 109.340 97.450 ;
        RECT 0.335 96.610 108.830 97.430 ;
        RECT 0.335 96.590 109.340 96.610 ;
        RECT 0.610 95.770 108.830 96.590 ;
        RECT 0.335 95.750 109.340 95.770 ;
        RECT 0.335 94.930 108.830 95.750 ;
        RECT 0.335 94.910 109.340 94.930 ;
        RECT 0.610 94.090 108.830 94.910 ;
        RECT 0.335 94.070 109.340 94.090 ;
        RECT 0.335 93.250 108.830 94.070 ;
        RECT 0.335 93.230 109.340 93.250 ;
        RECT 0.610 92.410 108.830 93.230 ;
        RECT 0.335 92.390 109.340 92.410 ;
        RECT 0.335 91.570 108.830 92.390 ;
        RECT 0.335 91.550 109.340 91.570 ;
        RECT 0.610 90.730 108.830 91.550 ;
        RECT 0.335 90.710 109.340 90.730 ;
        RECT 0.335 89.890 108.830 90.710 ;
        RECT 0.335 89.870 109.340 89.890 ;
        RECT 0.610 89.050 108.830 89.870 ;
        RECT 0.335 89.030 109.340 89.050 ;
        RECT 0.335 88.210 108.830 89.030 ;
        RECT 0.335 88.190 109.340 88.210 ;
        RECT 0.610 87.370 108.830 88.190 ;
        RECT 0.335 87.350 109.340 87.370 ;
        RECT 0.335 86.530 108.830 87.350 ;
        RECT 0.335 86.510 109.340 86.530 ;
        RECT 0.610 85.690 108.830 86.510 ;
        RECT 0.335 85.670 109.340 85.690 ;
        RECT 0.335 84.850 108.830 85.670 ;
        RECT 0.335 84.830 109.340 84.850 ;
        RECT 0.610 84.010 108.830 84.830 ;
        RECT 0.335 83.990 109.340 84.010 ;
        RECT 0.335 83.170 108.830 83.990 ;
        RECT 0.335 83.150 109.340 83.170 ;
        RECT 0.610 82.330 108.830 83.150 ;
        RECT 0.335 82.310 109.340 82.330 ;
        RECT 0.335 81.490 108.830 82.310 ;
        RECT 0.335 81.470 109.340 81.490 ;
        RECT 0.610 80.650 108.830 81.470 ;
        RECT 0.335 80.630 109.340 80.650 ;
        RECT 0.335 79.810 108.830 80.630 ;
        RECT 0.335 79.790 109.340 79.810 ;
        RECT 0.610 78.970 108.830 79.790 ;
        RECT 0.335 78.950 109.340 78.970 ;
        RECT 0.335 78.130 108.830 78.950 ;
        RECT 0.335 78.110 109.340 78.130 ;
        RECT 0.610 77.290 108.830 78.110 ;
        RECT 0.335 77.270 109.340 77.290 ;
        RECT 0.335 76.450 108.830 77.270 ;
        RECT 0.335 76.430 109.340 76.450 ;
        RECT 0.610 75.610 108.830 76.430 ;
        RECT 0.335 75.590 109.340 75.610 ;
        RECT 0.335 74.770 108.830 75.590 ;
        RECT 0.335 74.750 109.340 74.770 ;
        RECT 0.610 73.930 108.830 74.750 ;
        RECT 0.335 73.910 109.340 73.930 ;
        RECT 0.335 73.090 108.830 73.910 ;
        RECT 0.335 73.070 109.340 73.090 ;
        RECT 0.610 72.250 108.830 73.070 ;
        RECT 0.335 72.230 109.340 72.250 ;
        RECT 0.335 71.410 108.830 72.230 ;
        RECT 0.335 71.390 109.340 71.410 ;
        RECT 0.610 70.570 108.830 71.390 ;
        RECT 0.335 70.550 109.340 70.570 ;
        RECT 0.335 69.730 108.830 70.550 ;
        RECT 0.335 69.710 109.340 69.730 ;
        RECT 0.610 68.890 108.830 69.710 ;
        RECT 0.335 68.870 109.340 68.890 ;
        RECT 0.335 68.050 108.830 68.870 ;
        RECT 0.335 68.030 109.340 68.050 ;
        RECT 0.610 67.210 108.830 68.030 ;
        RECT 0.335 67.190 109.340 67.210 ;
        RECT 0.335 66.370 108.830 67.190 ;
        RECT 0.335 66.350 109.340 66.370 ;
        RECT 0.610 65.530 108.830 66.350 ;
        RECT 0.335 65.510 109.340 65.530 ;
        RECT 0.335 64.690 108.830 65.510 ;
        RECT 0.335 64.670 109.340 64.690 ;
        RECT 0.610 63.850 108.830 64.670 ;
        RECT 0.335 63.830 109.340 63.850 ;
        RECT 0.335 63.010 108.830 63.830 ;
        RECT 0.335 62.990 109.340 63.010 ;
        RECT 0.610 62.170 108.830 62.990 ;
        RECT 0.335 62.150 109.340 62.170 ;
        RECT 0.335 61.330 108.830 62.150 ;
        RECT 0.335 61.310 109.340 61.330 ;
        RECT 0.610 60.490 108.830 61.310 ;
        RECT 0.335 60.470 109.340 60.490 ;
        RECT 0.335 59.650 108.830 60.470 ;
        RECT 0.335 59.630 109.340 59.650 ;
        RECT 0.610 58.810 108.830 59.630 ;
        RECT 0.335 58.790 109.340 58.810 ;
        RECT 0.335 57.970 108.830 58.790 ;
        RECT 0.335 57.950 109.340 57.970 ;
        RECT 0.610 57.130 108.830 57.950 ;
        RECT 0.335 57.110 109.340 57.130 ;
        RECT 0.335 56.290 108.830 57.110 ;
        RECT 0.335 56.270 109.340 56.290 ;
        RECT 0.610 55.450 108.830 56.270 ;
        RECT 0.335 55.430 109.340 55.450 ;
        RECT 0.335 54.610 108.830 55.430 ;
        RECT 0.335 54.590 109.340 54.610 ;
        RECT 0.610 53.770 108.830 54.590 ;
        RECT 0.335 53.750 109.340 53.770 ;
        RECT 0.335 52.930 108.830 53.750 ;
        RECT 0.335 52.910 109.340 52.930 ;
        RECT 0.610 52.090 108.830 52.910 ;
        RECT 0.335 52.070 109.340 52.090 ;
        RECT 0.335 51.250 108.830 52.070 ;
        RECT 0.335 51.230 109.340 51.250 ;
        RECT 0.610 50.410 108.830 51.230 ;
        RECT 0.335 50.390 109.340 50.410 ;
        RECT 0.335 49.570 108.830 50.390 ;
        RECT 0.335 49.550 109.340 49.570 ;
        RECT 0.610 48.730 108.830 49.550 ;
        RECT 0.335 48.710 109.340 48.730 ;
        RECT 0.335 47.890 108.830 48.710 ;
        RECT 0.335 47.870 109.340 47.890 ;
        RECT 0.610 47.050 108.830 47.870 ;
        RECT 0.335 47.030 109.340 47.050 ;
        RECT 0.335 46.210 108.830 47.030 ;
        RECT 0.335 46.190 109.340 46.210 ;
        RECT 0.610 45.370 108.830 46.190 ;
        RECT 0.335 45.350 109.340 45.370 ;
        RECT 0.335 44.530 108.830 45.350 ;
        RECT 0.335 44.510 109.340 44.530 ;
        RECT 0.610 43.690 108.830 44.510 ;
        RECT 0.335 43.670 109.340 43.690 ;
        RECT 0.335 42.850 108.830 43.670 ;
        RECT 0.335 42.830 109.340 42.850 ;
        RECT 0.610 42.010 108.830 42.830 ;
        RECT 0.335 41.990 109.340 42.010 ;
        RECT 0.335 41.170 108.830 41.990 ;
        RECT 0.335 41.150 109.340 41.170 ;
        RECT 0.610 40.330 108.830 41.150 ;
        RECT 0.335 40.310 109.340 40.330 ;
        RECT 0.335 39.490 108.830 40.310 ;
        RECT 0.335 39.470 109.340 39.490 ;
        RECT 0.610 38.650 108.830 39.470 ;
        RECT 0.335 38.630 109.340 38.650 ;
        RECT 0.335 37.810 108.830 38.630 ;
        RECT 0.335 37.790 109.340 37.810 ;
        RECT 0.610 36.970 108.830 37.790 ;
        RECT 0.335 36.950 109.340 36.970 ;
        RECT 0.335 36.130 108.830 36.950 ;
        RECT 0.335 36.110 109.340 36.130 ;
        RECT 0.610 35.290 108.830 36.110 ;
        RECT 0.335 35.270 109.340 35.290 ;
        RECT 0.335 34.450 108.830 35.270 ;
        RECT 0.335 34.430 109.340 34.450 ;
        RECT 0.610 33.610 108.830 34.430 ;
        RECT 0.335 33.590 109.340 33.610 ;
        RECT 0.335 32.770 108.830 33.590 ;
        RECT 0.335 32.750 109.340 32.770 ;
        RECT 0.610 31.930 108.830 32.750 ;
        RECT 0.335 31.910 109.340 31.930 ;
        RECT 0.335 31.090 108.830 31.910 ;
        RECT 0.335 31.070 109.340 31.090 ;
        RECT 0.610 30.250 108.830 31.070 ;
        RECT 0.335 30.230 109.340 30.250 ;
        RECT 0.335 29.410 108.830 30.230 ;
        RECT 0.335 29.390 109.340 29.410 ;
        RECT 0.610 28.570 108.830 29.390 ;
        RECT 0.335 28.550 109.340 28.570 ;
        RECT 0.335 27.730 108.830 28.550 ;
        RECT 0.335 27.710 109.340 27.730 ;
        RECT 0.610 26.890 108.830 27.710 ;
        RECT 0.335 26.870 109.340 26.890 ;
        RECT 0.335 26.050 108.830 26.870 ;
        RECT 0.335 26.030 109.340 26.050 ;
        RECT 0.610 25.210 108.830 26.030 ;
        RECT 0.335 25.190 109.340 25.210 ;
        RECT 0.335 24.370 108.830 25.190 ;
        RECT 0.335 24.350 109.340 24.370 ;
        RECT 0.610 23.530 109.340 24.350 ;
        RECT 0.335 22.670 109.340 23.530 ;
        RECT 0.610 21.850 109.340 22.670 ;
        RECT 0.335 20.990 109.340 21.850 ;
        RECT 0.610 20.170 109.340 20.990 ;
        RECT 0.335 19.310 109.340 20.170 ;
        RECT 0.610 18.490 109.340 19.310 ;
        RECT 0.335 17.630 109.340 18.490 ;
        RECT 0.610 16.810 109.340 17.630 ;
        RECT 0.335 15.950 109.340 16.810 ;
        RECT 0.610 15.130 109.340 15.950 ;
        RECT 0.335 14.270 109.340 15.130 ;
        RECT 0.610 13.450 109.340 14.270 ;
        RECT 0.335 12.590 109.340 13.450 ;
        RECT 0.610 11.770 109.340 12.590 ;
        RECT 0.335 10.910 109.340 11.770 ;
        RECT 0.610 10.090 109.340 10.910 ;
        RECT 0.335 9.230 109.340 10.090 ;
        RECT 0.610 8.410 109.340 9.230 ;
        RECT 0.335 7.550 109.340 8.410 ;
        RECT 0.610 6.730 109.340 7.550 ;
        RECT 0.335 5.870 109.340 6.730 ;
        RECT 0.610 5.050 109.340 5.870 ;
        RECT 0.335 4.190 109.340 5.050 ;
        RECT 0.610 3.370 109.340 4.190 ;
        RECT 0.335 2.510 109.340 3.370 ;
        RECT 0.610 1.690 109.340 2.510 ;
        RECT 0.335 0.830 109.340 1.690 ;
        RECT 0.610 0.315 109.340 0.830 ;
      LAYER Metal4 ;
        RECT 0.380 0.270 109.065 427.285 ;
      LAYER Metal5 ;
        RECT 0.815 0.320 109.105 427.450 ;
      LAYER TopMetal1 ;
        RECT 5.380 5.060 13.740 418.300 ;
        RECT 19.220 5.060 19.940 418.300 ;
        RECT 25.420 5.060 89.340 418.300 ;
        RECT 94.820 5.060 95.540 418.300 ;
        RECT 101.020 5.060 107.340 418.300 ;
  END
END IHP_SRAM
END LIBRARY

